VERSION 5.8 ;
BUSBITCHARS "[]" ;
DIVIDERCHAR "/" ;
UNITS
    DATABASE MICRONS 1000 ;
END UNITS

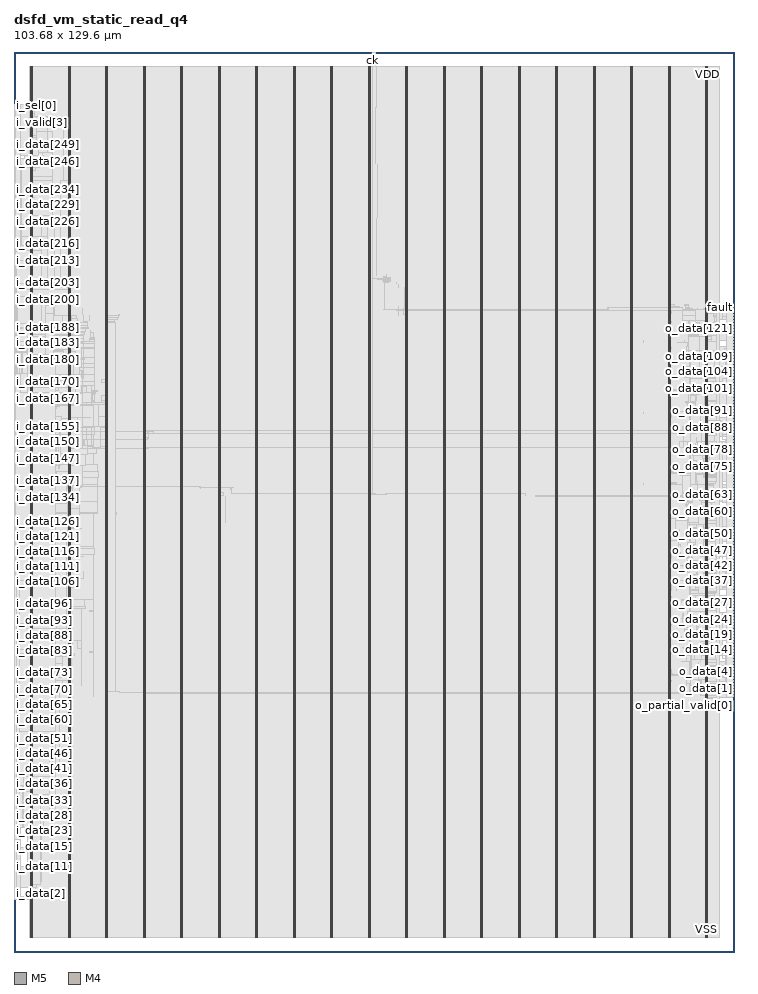
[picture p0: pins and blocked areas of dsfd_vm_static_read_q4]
MACRO dsfd_vm_static_read_q4
  FOREIGN dsfd_vm_static_read_q4 0 0 ;
  CLASS BLOCK ;
  SIZE 103.68 BY 129.6 ;
  PIN ck
    DIRECTION INPUT ;
    USE SIGNAL ;
    PORT
      LAYER M5 ;
        RECT  51.6 129.516 51.624 129.6 ;
    END
  END ck
  PIN fault
    DIRECTION OUTPUT ;
    USE SIGNAL ;
    PORT
      LAYER M4 ;
        RECT  103.596 92.832 103.68 92.856 ;
    END
  END fault
  PIN i_data[0]
    DIRECTION INPUT ;
    USE SIGNAL ;
    PORT
      LAYER M4 ;
        RECT  0 7.536 0.084 7.56 ;
    END
  END i_data[0]
  PIN i_data[100]
    DIRECTION INPUT ;
    USE SIGNAL ;
    PORT
      LAYER M4 ;
        RECT  0 50.736 0.084 50.76 ;
    END
  END i_data[100]
  PIN i_data[101]
    DIRECTION INPUT ;
    USE SIGNAL ;
    PORT
      LAYER M4 ;
        RECT  0 51.168 0.084 51.192 ;
    END
  END i_data[101]
  PIN i_data[102]
    DIRECTION INPUT ;
    USE SIGNAL ;
    PORT
      LAYER M4 ;
        RECT  0 51.6 0.084 51.624 ;
    END
  END i_data[102]
  PIN i_data[103]
    DIRECTION INPUT ;
    USE SIGNAL ;
    PORT
      LAYER M4 ;
        RECT  0 52.032 0.084 52.056 ;
    END
  END i_data[103]
  PIN i_data[104]
    DIRECTION INPUT ;
    USE SIGNAL ;
    PORT
      LAYER M4 ;
        RECT  0 52.464 0.084 52.488 ;
    END
  END i_data[104]
  PIN i_data[105]
    DIRECTION INPUT ;
    USE SIGNAL ;
    PORT
      LAYER M4 ;
        RECT  0 52.896 0.084 52.92 ;
    END
  END i_data[105]
  PIN i_data[106]
    DIRECTION INPUT ;
    USE SIGNAL ;
    PORT
      LAYER M4 ;
        RECT  0 53.328 0.084 53.352 ;
    END
  END i_data[106]
  PIN i_data[107]
    DIRECTION INPUT ;
    USE SIGNAL ;
    PORT
      LAYER M4 ;
        RECT  0 53.76 0.084 53.784 ;
    END
  END i_data[107]
  PIN i_data[108]
    DIRECTION INPUT ;
    USE SIGNAL ;
    PORT
      LAYER M4 ;
        RECT  0 54.192 0.084 54.216 ;
    END
  END i_data[108]
  PIN i_data[109]
    DIRECTION INPUT ;
    USE SIGNAL ;
    PORT
      LAYER M4 ;
        RECT  0 54.624 0.084 54.648 ;
    END
  END i_data[109]
  PIN i_data[10]
    DIRECTION INPUT ;
    USE SIGNAL ;
    PORT
      LAYER M4 ;
        RECT  0 11.856 0.084 11.88 ;
    END
  END i_data[10]
  PIN i_data[110]
    DIRECTION INPUT ;
    USE SIGNAL ;
    PORT
      LAYER M4 ;
        RECT  0 55.056 0.084 55.08 ;
    END
  END i_data[110]
  PIN i_data[111]
    DIRECTION INPUT ;
    USE SIGNAL ;
    PORT
      LAYER M4 ;
        RECT  0 55.488 0.084 55.512 ;
    END
  END i_data[111]
  PIN i_data[112]
    DIRECTION INPUT ;
    USE SIGNAL ;
    PORT
      LAYER M4 ;
        RECT  0 55.92 0.084 55.944 ;
    END
  END i_data[112]
  PIN i_data[113]
    DIRECTION INPUT ;
    USE SIGNAL ;
    PORT
      LAYER M4 ;
        RECT  0 56.352 0.084 56.376 ;
    END
  END i_data[113]
  PIN i_data[114]
    DIRECTION INPUT ;
    USE SIGNAL ;
    PORT
      LAYER M4 ;
        RECT  0 56.784 0.084 56.808 ;
    END
  END i_data[114]
  PIN i_data[115]
    DIRECTION INPUT ;
    USE SIGNAL ;
    PORT
      LAYER M4 ;
        RECT  0 57.216 0.084 57.24 ;
    END
  END i_data[115]
  PIN i_data[116]
    DIRECTION INPUT ;
    USE SIGNAL ;
    PORT
      LAYER M4 ;
        RECT  0 57.648 0.084 57.672 ;
    END
  END i_data[116]
  PIN i_data[117]
    DIRECTION INPUT ;
    USE SIGNAL ;
    PORT
      LAYER M4 ;
        RECT  0 58.08 0.084 58.104 ;
    END
  END i_data[117]
  PIN i_data[118]
    DIRECTION INPUT ;
    USE SIGNAL ;
    PORT
      LAYER M4 ;
        RECT  0 58.512 0.084 58.536 ;
    END
  END i_data[118]
  PIN i_data[119]
    DIRECTION INPUT ;
    USE SIGNAL ;
    PORT
      LAYER M4 ;
        RECT  0 58.944 0.084 58.968 ;
    END
  END i_data[119]
  PIN i_data[11]
    DIRECTION INPUT ;
    USE SIGNAL ;
    PORT
      LAYER M4 ;
        RECT  0 12.288 0.084 12.312 ;
    END
  END i_data[11]
  PIN i_data[120]
    DIRECTION INPUT ;
    USE SIGNAL ;
    PORT
      LAYER M4 ;
        RECT  0 59.376 0.084 59.4 ;
    END
  END i_data[120]
  PIN i_data[121]
    DIRECTION INPUT ;
    USE SIGNAL ;
    PORT
      LAYER M4 ;
        RECT  0 59.808 0.084 59.832 ;
    END
  END i_data[121]
  PIN i_data[122]
    DIRECTION INPUT ;
    USE SIGNAL ;
    PORT
      LAYER M4 ;
        RECT  0 60.24 0.084 60.264 ;
    END
  END i_data[122]
  PIN i_data[123]
    DIRECTION INPUT ;
    USE SIGNAL ;
    PORT
      LAYER M4 ;
        RECT  0 60.672 0.084 60.696 ;
    END
  END i_data[123]
  PIN i_data[124]
    DIRECTION INPUT ;
    USE SIGNAL ;
    PORT
      LAYER M4 ;
        RECT  0 61.104 0.084 61.128 ;
    END
  END i_data[124]
  PIN i_data[125]
    DIRECTION INPUT ;
    USE SIGNAL ;
    PORT
      LAYER M4 ;
        RECT  0 61.536 0.084 61.56 ;
    END
  END i_data[125]
  PIN i_data[126]
    DIRECTION INPUT ;
    USE SIGNAL ;
    PORT
      LAYER M4 ;
        RECT  0 61.968 0.084 61.992 ;
    END
  END i_data[126]
  PIN i_data[127]
    DIRECTION INPUT ;
    USE SIGNAL ;
    PORT
      LAYER M4 ;
        RECT  0 62.4 0.084 62.424 ;
    END
  END i_data[127]
  PIN i_data[128]
    DIRECTION INPUT ;
    USE SIGNAL ;
    PORT
      LAYER M4 ;
        RECT  0 62.832 0.084 62.856 ;
    END
  END i_data[128]
  PIN i_data[129]
    DIRECTION INPUT ;
    USE SIGNAL ;
    PORT
      LAYER M4 ;
        RECT  0 63.264 0.084 63.288 ;
    END
  END i_data[129]
  PIN i_data[12]
    DIRECTION INPUT ;
    USE SIGNAL ;
    PORT
      LAYER M4 ;
        RECT  0 12.72 0.084 12.744 ;
    END
  END i_data[12]
  PIN i_data[130]
    DIRECTION INPUT ;
    USE SIGNAL ;
    PORT
      LAYER M4 ;
        RECT  0 63.696 0.084 63.72 ;
    END
  END i_data[130]
  PIN i_data[131]
    DIRECTION INPUT ;
    USE SIGNAL ;
    PORT
      LAYER M4 ;
        RECT  0 64.128 0.084 64.152 ;
    END
  END i_data[131]
  PIN i_data[132]
    DIRECTION INPUT ;
    USE SIGNAL ;
    PORT
      LAYER M4 ;
        RECT  0 64.56 0.084 64.584 ;
    END
  END i_data[132]
  PIN i_data[133]
    DIRECTION INPUT ;
    USE SIGNAL ;
    PORT
      LAYER M4 ;
        RECT  0 64.992 0.084 65.016 ;
    END
  END i_data[133]
  PIN i_data[134]
    DIRECTION INPUT ;
    USE SIGNAL ;
    PORT
      LAYER M4 ;
        RECT  0 65.424 0.084 65.448 ;
    END
  END i_data[134]
  PIN i_data[135]
    DIRECTION INPUT ;
    USE SIGNAL ;
    PORT
      LAYER M4 ;
        RECT  0 65.856 0.084 65.88 ;
    END
  END i_data[135]
  PIN i_data[136]
    DIRECTION INPUT ;
    USE SIGNAL ;
    PORT
      LAYER M4 ;
        RECT  0 66.288 0.084 66.312 ;
    END
  END i_data[136]
  PIN i_data[137]
    DIRECTION INPUT ;
    USE SIGNAL ;
    PORT
      LAYER M4 ;
        RECT  0 66.72 0.084 66.744 ;
    END
  END i_data[137]
  PIN i_data[138]
    DIRECTION INPUT ;
    USE SIGNAL ;
    PORT
      LAYER M4 ;
        RECT  0 67.152 0.084 67.176 ;
    END
  END i_data[138]
  PIN i_data[139]
    DIRECTION INPUT ;
    USE SIGNAL ;
    PORT
      LAYER M4 ;
        RECT  0 67.584 0.084 67.608 ;
    END
  END i_data[139]
  PIN i_data[13]
    DIRECTION INPUT ;
    USE SIGNAL ;
    PORT
      LAYER M4 ;
        RECT  0 13.152 0.084 13.176 ;
    END
  END i_data[13]
  PIN i_data[140]
    DIRECTION INPUT ;
    USE SIGNAL ;
    PORT
      LAYER M4 ;
        RECT  0 68.016 0.084 68.04 ;
    END
  END i_data[140]
  PIN i_data[141]
    DIRECTION INPUT ;
    USE SIGNAL ;
    PORT
      LAYER M4 ;
        RECT  0 68.448 0.084 68.472 ;
    END
  END i_data[141]
  PIN i_data[142]
    DIRECTION INPUT ;
    USE SIGNAL ;
    PORT
      LAYER M4 ;
        RECT  0 68.88 0.084 68.904 ;
    END
  END i_data[142]
  PIN i_data[143]
    DIRECTION INPUT ;
    USE SIGNAL ;
    PORT
      LAYER M4 ;
        RECT  0 69.312 0.084 69.336 ;
    END
  END i_data[143]
  PIN i_data[144]
    DIRECTION INPUT ;
    USE SIGNAL ;
    PORT
      LAYER M4 ;
        RECT  0 69.744 0.084 69.768 ;
    END
  END i_data[144]
  PIN i_data[145]
    DIRECTION INPUT ;
    USE SIGNAL ;
    PORT
      LAYER M4 ;
        RECT  0 70.176 0.084 70.2 ;
    END
  END i_data[145]
  PIN i_data[146]
    DIRECTION INPUT ;
    USE SIGNAL ;
    PORT
      LAYER M4 ;
        RECT  0 70.608 0.084 70.632 ;
    END
  END i_data[146]
  PIN i_data[147]
    DIRECTION INPUT ;
    USE SIGNAL ;
    PORT
      LAYER M4 ;
        RECT  0 71.04 0.084 71.064 ;
    END
  END i_data[147]
  PIN i_data[148]
    DIRECTION INPUT ;
    USE SIGNAL ;
    PORT
      LAYER M4 ;
        RECT  0 71.472 0.084 71.496 ;
    END
  END i_data[148]
  PIN i_data[149]
    DIRECTION INPUT ;
    USE SIGNAL ;
    PORT
      LAYER M4 ;
        RECT  0 71.904 0.084 71.928 ;
    END
  END i_data[149]
  PIN i_data[14]
    DIRECTION INPUT ;
    USE SIGNAL ;
    PORT
      LAYER M4 ;
        RECT  0 13.584 0.084 13.608 ;
    END
  END i_data[14]
  PIN i_data[150]
    DIRECTION INPUT ;
    USE SIGNAL ;
    PORT
      LAYER M4 ;
        RECT  0 72.336 0.084 72.36 ;
    END
  END i_data[150]
  PIN i_data[151]
    DIRECTION INPUT ;
    USE SIGNAL ;
    PORT
      LAYER M4 ;
        RECT  0 72.768 0.084 72.792 ;
    END
  END i_data[151]
  PIN i_data[152]
    DIRECTION INPUT ;
    USE SIGNAL ;
    PORT
      LAYER M4 ;
        RECT  0 73.2 0.084 73.224 ;
    END
  END i_data[152]
  PIN i_data[153]
    DIRECTION INPUT ;
    USE SIGNAL ;
    PORT
      LAYER M4 ;
        RECT  0 73.632 0.084 73.656 ;
    END
  END i_data[153]
  PIN i_data[154]
    DIRECTION INPUT ;
    USE SIGNAL ;
    PORT
      LAYER M4 ;
        RECT  0 74.064 0.084 74.088 ;
    END
  END i_data[154]
  PIN i_data[155]
    DIRECTION INPUT ;
    USE SIGNAL ;
    PORT
      LAYER M4 ;
        RECT  0 74.496 0.084 74.52 ;
    END
  END i_data[155]
  PIN i_data[156]
    DIRECTION INPUT ;
    USE SIGNAL ;
    PORT
      LAYER M4 ;
        RECT  0 74.928 0.084 74.952 ;
    END
  END i_data[156]
  PIN i_data[157]
    DIRECTION INPUT ;
    USE SIGNAL ;
    PORT
      LAYER M4 ;
        RECT  0 75.36 0.084 75.384 ;
    END
  END i_data[157]
  PIN i_data[158]
    DIRECTION INPUT ;
    USE SIGNAL ;
    PORT
      LAYER M4 ;
        RECT  0 75.792 0.084 75.816 ;
    END
  END i_data[158]
  PIN i_data[159]
    DIRECTION INPUT ;
    USE SIGNAL ;
    PORT
      LAYER M4 ;
        RECT  0 76.224 0.084 76.248 ;
    END
  END i_data[159]
  PIN i_data[15]
    DIRECTION INPUT ;
    USE SIGNAL ;
    PORT
      LAYER M4 ;
        RECT  0 14.016 0.084 14.04 ;
    END
  END i_data[15]
  PIN i_data[160]
    DIRECTION INPUT ;
    USE SIGNAL ;
    PORT
      LAYER M4 ;
        RECT  0 76.656 0.084 76.68 ;
    END
  END i_data[160]
  PIN i_data[161]
    DIRECTION INPUT ;
    USE SIGNAL ;
    PORT
      LAYER M4 ;
        RECT  0 77.088 0.084 77.112 ;
    END
  END i_data[161]
  PIN i_data[162]
    DIRECTION INPUT ;
    USE SIGNAL ;
    PORT
      LAYER M4 ;
        RECT  0 77.52 0.084 77.544 ;
    END
  END i_data[162]
  PIN i_data[163]
    DIRECTION INPUT ;
    USE SIGNAL ;
    PORT
      LAYER M4 ;
        RECT  0 77.952 0.084 77.976 ;
    END
  END i_data[163]
  PIN i_data[164]
    DIRECTION INPUT ;
    USE SIGNAL ;
    PORT
      LAYER M4 ;
        RECT  0 78.384 0.084 78.408 ;
    END
  END i_data[164]
  PIN i_data[165]
    DIRECTION INPUT ;
    USE SIGNAL ;
    PORT
      LAYER M4 ;
        RECT  0 78.816 0.084 78.84 ;
    END
  END i_data[165]
  PIN i_data[166]
    DIRECTION INPUT ;
    USE SIGNAL ;
    PORT
      LAYER M4 ;
        RECT  0 79.248 0.084 79.272 ;
    END
  END i_data[166]
  PIN i_data[167]
    DIRECTION INPUT ;
    USE SIGNAL ;
    PORT
      LAYER M4 ;
        RECT  0 79.68 0.084 79.704 ;
    END
  END i_data[167]
  PIN i_data[168]
    DIRECTION INPUT ;
    USE SIGNAL ;
    PORT
      LAYER M4 ;
        RECT  0 80.112 0.084 80.136 ;
    END
  END i_data[168]
  PIN i_data[169]
    DIRECTION INPUT ;
    USE SIGNAL ;
    PORT
      LAYER M4 ;
        RECT  0 80.544 0.084 80.568 ;
    END
  END i_data[169]
  PIN i_data[16]
    DIRECTION INPUT ;
    USE SIGNAL ;
    PORT
      LAYER M4 ;
        RECT  0 14.448 0.084 14.472 ;
    END
  END i_data[16]
  PIN i_data[170]
    DIRECTION INPUT ;
    USE SIGNAL ;
    PORT
      LAYER M4 ;
        RECT  0 80.976 0.084 81 ;
    END
  END i_data[170]
  PIN i_data[171]
    DIRECTION INPUT ;
    USE SIGNAL ;
    PORT
      LAYER M4 ;
        RECT  0 81.408 0.084 81.432 ;
    END
  END i_data[171]
  PIN i_data[172]
    DIRECTION INPUT ;
    USE SIGNAL ;
    PORT
      LAYER M4 ;
        RECT  0 81.84 0.084 81.864 ;
    END
  END i_data[172]
  PIN i_data[173]
    DIRECTION INPUT ;
    USE SIGNAL ;
    PORT
      LAYER M4 ;
        RECT  0 82.272 0.084 82.296 ;
    END
  END i_data[173]
  PIN i_data[174]
    DIRECTION INPUT ;
    USE SIGNAL ;
    PORT
      LAYER M4 ;
        RECT  0 82.704 0.084 82.728 ;
    END
  END i_data[174]
  PIN i_data[175]
    DIRECTION INPUT ;
    USE SIGNAL ;
    PORT
      LAYER M4 ;
        RECT  0 83.136 0.084 83.16 ;
    END
  END i_data[175]
  PIN i_data[176]
    DIRECTION INPUT ;
    USE SIGNAL ;
    PORT
      LAYER M4 ;
        RECT  0 83.568 0.084 83.592 ;
    END
  END i_data[176]
  PIN i_data[177]
    DIRECTION INPUT ;
    USE SIGNAL ;
    PORT
      LAYER M4 ;
        RECT  0 84 0.084 84.024 ;
    END
  END i_data[177]
  PIN i_data[178]
    DIRECTION INPUT ;
    USE SIGNAL ;
    PORT
      LAYER M4 ;
        RECT  0 84.432 0.084 84.456 ;
    END
  END i_data[178]
  PIN i_data[179]
    DIRECTION INPUT ;
    USE SIGNAL ;
    PORT
      LAYER M4 ;
        RECT  0 84.864 0.084 84.888 ;
    END
  END i_data[179]
  PIN i_data[17]
    DIRECTION INPUT ;
    USE SIGNAL ;
    PORT
      LAYER M4 ;
        RECT  0 14.88 0.084 14.904 ;
    END
  END i_data[17]
  PIN i_data[180]
    DIRECTION INPUT ;
    USE SIGNAL ;
    PORT
      LAYER M4 ;
        RECT  0 85.296 0.084 85.32 ;
    END
  END i_data[180]
  PIN i_data[181]
    DIRECTION INPUT ;
    USE SIGNAL ;
    PORT
      LAYER M4 ;
        RECT  0 85.728 0.084 85.752 ;
    END
  END i_data[181]
  PIN i_data[182]
    DIRECTION INPUT ;
    USE SIGNAL ;
    PORT
      LAYER M4 ;
        RECT  0 86.16 0.084 86.184 ;
    END
  END i_data[182]
  PIN i_data[183]
    DIRECTION INPUT ;
    USE SIGNAL ;
    PORT
      LAYER M4 ;
        RECT  0 86.592 0.084 86.616 ;
    END
  END i_data[183]
  PIN i_data[184]
    DIRECTION INPUT ;
    USE SIGNAL ;
    PORT
      LAYER M4 ;
        RECT  0 87.024 0.084 87.048 ;
    END
  END i_data[184]
  PIN i_data[185]
    DIRECTION INPUT ;
    USE SIGNAL ;
    PORT
      LAYER M4 ;
        RECT  0 87.456 0.084 87.48 ;
    END
  END i_data[185]
  PIN i_data[186]
    DIRECTION INPUT ;
    USE SIGNAL ;
    PORT
      LAYER M4 ;
        RECT  0 87.888 0.084 87.912 ;
    END
  END i_data[186]
  PIN i_data[187]
    DIRECTION INPUT ;
    USE SIGNAL ;
    PORT
      LAYER M4 ;
        RECT  0 88.32 0.084 88.344 ;
    END
  END i_data[187]
  PIN i_data[188]
    DIRECTION INPUT ;
    USE SIGNAL ;
    PORT
      LAYER M4 ;
        RECT  0 88.752 0.084 88.776 ;
    END
  END i_data[188]
  PIN i_data[189]
    DIRECTION INPUT ;
    USE SIGNAL ;
    PORT
      LAYER M4 ;
        RECT  0 89.184 0.084 89.208 ;
    END
  END i_data[189]
  PIN i_data[18]
    DIRECTION INPUT ;
    USE SIGNAL ;
    PORT
      LAYER M4 ;
        RECT  0 15.312 0.084 15.336 ;
    END
  END i_data[18]
  PIN i_data[190]
    DIRECTION INPUT ;
    USE SIGNAL ;
    PORT
      LAYER M4 ;
        RECT  0 89.616 0.084 89.64 ;
    END
  END i_data[190]
  PIN i_data[191]
    DIRECTION INPUT ;
    USE SIGNAL ;
    PORT
      LAYER M4 ;
        RECT  0 90.048 0.084 90.072 ;
    END
  END i_data[191]
  PIN i_data[192]
    DIRECTION INPUT ;
    USE SIGNAL ;
    PORT
      LAYER M4 ;
        RECT  0 90.48 0.084 90.504 ;
    END
  END i_data[192]
  PIN i_data[193]
    DIRECTION INPUT ;
    USE SIGNAL ;
    PORT
      LAYER M4 ;
        RECT  0 90.912 0.084 90.936 ;
    END
  END i_data[193]
  PIN i_data[194]
    DIRECTION INPUT ;
    USE SIGNAL ;
    PORT
      LAYER M4 ;
        RECT  0 91.344 0.084 91.368 ;
    END
  END i_data[194]
  PIN i_data[195]
    DIRECTION INPUT ;
    USE SIGNAL ;
    PORT
      LAYER M4 ;
        RECT  0 91.776 0.084 91.8 ;
    END
  END i_data[195]
  PIN i_data[196]
    DIRECTION INPUT ;
    USE SIGNAL ;
    PORT
      LAYER M4 ;
        RECT  0 92.208 0.084 92.232 ;
    END
  END i_data[196]
  PIN i_data[197]
    DIRECTION INPUT ;
    USE SIGNAL ;
    PORT
      LAYER M4 ;
        RECT  0 92.64 0.084 92.664 ;
    END
  END i_data[197]
  PIN i_data[198]
    DIRECTION INPUT ;
    USE SIGNAL ;
    PORT
      LAYER M4 ;
        RECT  0 93.072 0.084 93.096 ;
    END
  END i_data[198]
  PIN i_data[199]
    DIRECTION INPUT ;
    USE SIGNAL ;
    PORT
      LAYER M4 ;
        RECT  0 93.504 0.084 93.528 ;
    END
  END i_data[199]
  PIN i_data[19]
    DIRECTION INPUT ;
    USE SIGNAL ;
    PORT
      LAYER M4 ;
        RECT  0 15.744 0.084 15.768 ;
    END
  END i_data[19]
  PIN i_data[1]
    DIRECTION INPUT ;
    USE SIGNAL ;
    PORT
      LAYER M4 ;
        RECT  0 7.968 0.084 7.992 ;
    END
  END i_data[1]
  PIN i_data[200]
    DIRECTION INPUT ;
    USE SIGNAL ;
    PORT
      LAYER M4 ;
        RECT  0 93.936 0.084 93.96 ;
    END
  END i_data[200]
  PIN i_data[201]
    DIRECTION INPUT ;
    USE SIGNAL ;
    PORT
      LAYER M4 ;
        RECT  0 94.368 0.084 94.392 ;
    END
  END i_data[201]
  PIN i_data[202]
    DIRECTION INPUT ;
    USE SIGNAL ;
    PORT
      LAYER M4 ;
        RECT  0 94.8 0.084 94.824 ;
    END
  END i_data[202]
  PIN i_data[203]
    DIRECTION INPUT ;
    USE SIGNAL ;
    PORT
      LAYER M4 ;
        RECT  0 95.232 0.084 95.256 ;
    END
  END i_data[203]
  PIN i_data[204]
    DIRECTION INPUT ;
    USE SIGNAL ;
    PORT
      LAYER M4 ;
        RECT  0 95.664 0.084 95.688 ;
    END
  END i_data[204]
  PIN i_data[205]
    DIRECTION INPUT ;
    USE SIGNAL ;
    PORT
      LAYER M4 ;
        RECT  0 96.096 0.084 96.12 ;
    END
  END i_data[205]
  PIN i_data[206]
    DIRECTION INPUT ;
    USE SIGNAL ;
    PORT
      LAYER M4 ;
        RECT  0 96.528 0.084 96.552 ;
    END
  END i_data[206]
  PIN i_data[207]
    DIRECTION INPUT ;
    USE SIGNAL ;
    PORT
      LAYER M4 ;
        RECT  0 96.96 0.084 96.984 ;
    END
  END i_data[207]
  PIN i_data[208]
    DIRECTION INPUT ;
    USE SIGNAL ;
    PORT
      LAYER M4 ;
        RECT  0 97.392 0.084 97.416 ;
    END
  END i_data[208]
  PIN i_data[209]
    DIRECTION INPUT ;
    USE SIGNAL ;
    PORT
      LAYER M4 ;
        RECT  0 97.824 0.084 97.848 ;
    END
  END i_data[209]
  PIN i_data[20]
    DIRECTION INPUT ;
    USE SIGNAL ;
    PORT
      LAYER M4 ;
        RECT  0 16.176 0.084 16.2 ;
    END
  END i_data[20]
  PIN i_data[210]
    DIRECTION INPUT ;
    USE SIGNAL ;
    PORT
      LAYER M4 ;
        RECT  0 98.256 0.084 98.28 ;
    END
  END i_data[210]
  PIN i_data[211]
    DIRECTION INPUT ;
    USE SIGNAL ;
    PORT
      LAYER M4 ;
        RECT  0 98.688 0.084 98.712 ;
    END
  END i_data[211]
  PIN i_data[212]
    DIRECTION INPUT ;
    USE SIGNAL ;
    PORT
      LAYER M4 ;
        RECT  0 99.12 0.084 99.144 ;
    END
  END i_data[212]
  PIN i_data[213]
    DIRECTION INPUT ;
    USE SIGNAL ;
    PORT
      LAYER M4 ;
        RECT  0 99.552 0.084 99.576 ;
    END
  END i_data[213]
  PIN i_data[214]
    DIRECTION INPUT ;
    USE SIGNAL ;
    PORT
      LAYER M4 ;
        RECT  0 99.984 0.084 100.008 ;
    END
  END i_data[214]
  PIN i_data[215]
    DIRECTION INPUT ;
    USE SIGNAL ;
    PORT
      LAYER M4 ;
        RECT  0 100.416 0.084 100.44 ;
    END
  END i_data[215]
  PIN i_data[216]
    DIRECTION INPUT ;
    USE SIGNAL ;
    PORT
      LAYER M4 ;
        RECT  0 100.848 0.084 100.872 ;
    END
  END i_data[216]
  PIN i_data[217]
    DIRECTION INPUT ;
    USE SIGNAL ;
    PORT
      LAYER M4 ;
        RECT  0 101.28 0.084 101.304 ;
    END
  END i_data[217]
  PIN i_data[218]
    DIRECTION INPUT ;
    USE SIGNAL ;
    PORT
      LAYER M4 ;
        RECT  0 101.712 0.084 101.736 ;
    END
  END i_data[218]
  PIN i_data[219]
    DIRECTION INPUT ;
    USE SIGNAL ;
    PORT
      LAYER M4 ;
        RECT  0 102.144 0.084 102.168 ;
    END
  END i_data[219]
  PIN i_data[21]
    DIRECTION INPUT ;
    USE SIGNAL ;
    PORT
      LAYER M4 ;
        RECT  0 16.608 0.084 16.632 ;
    END
  END i_data[21]
  PIN i_data[220]
    DIRECTION INPUT ;
    USE SIGNAL ;
    PORT
      LAYER M4 ;
        RECT  0 102.576 0.084 102.6 ;
    END
  END i_data[220]
  PIN i_data[221]
    DIRECTION INPUT ;
    USE SIGNAL ;
    PORT
      LAYER M4 ;
        RECT  0 103.008 0.084 103.032 ;
    END
  END i_data[221]
  PIN i_data[222]
    DIRECTION INPUT ;
    USE SIGNAL ;
    PORT
      LAYER M4 ;
        RECT  0 103.44 0.084 103.464 ;
    END
  END i_data[222]
  PIN i_data[223]
    DIRECTION INPUT ;
    USE SIGNAL ;
    PORT
      LAYER M4 ;
        RECT  0 103.872 0.084 103.896 ;
    END
  END i_data[223]
  PIN i_data[224]
    DIRECTION INPUT ;
    USE SIGNAL ;
    PORT
      LAYER M4 ;
        RECT  0 104.304 0.084 104.328 ;
    END
  END i_data[224]
  PIN i_data[225]
    DIRECTION INPUT ;
    USE SIGNAL ;
    PORT
      LAYER M4 ;
        RECT  0 104.736 0.084 104.76 ;
    END
  END i_data[225]
  PIN i_data[226]
    DIRECTION INPUT ;
    USE SIGNAL ;
    PORT
      LAYER M4 ;
        RECT  0 105.168 0.084 105.192 ;
    END
  END i_data[226]
  PIN i_data[227]
    DIRECTION INPUT ;
    USE SIGNAL ;
    PORT
      LAYER M4 ;
        RECT  0 105.6 0.084 105.624 ;
    END
  END i_data[227]
  PIN i_data[228]
    DIRECTION INPUT ;
    USE SIGNAL ;
    PORT
      LAYER M4 ;
        RECT  0 106.032 0.084 106.056 ;
    END
  END i_data[228]
  PIN i_data[229]
    DIRECTION INPUT ;
    USE SIGNAL ;
    PORT
      LAYER M4 ;
        RECT  0 106.464 0.084 106.488 ;
    END
  END i_data[229]
  PIN i_data[22]
    DIRECTION INPUT ;
    USE SIGNAL ;
    PORT
      LAYER M4 ;
        RECT  0 17.04 0.084 17.064 ;
    END
  END i_data[22]
  PIN i_data[230]
    DIRECTION INPUT ;
    USE SIGNAL ;
    PORT
      LAYER M4 ;
        RECT  0 106.896 0.084 106.92 ;
    END
  END i_data[230]
  PIN i_data[231]
    DIRECTION INPUT ;
    USE SIGNAL ;
    PORT
      LAYER M4 ;
        RECT  0 107.328 0.084 107.352 ;
    END
  END i_data[231]
  PIN i_data[232]
    DIRECTION INPUT ;
    USE SIGNAL ;
    PORT
      LAYER M4 ;
        RECT  0 107.76 0.084 107.784 ;
    END
  END i_data[232]
  PIN i_data[233]
    DIRECTION INPUT ;
    USE SIGNAL ;
    PORT
      LAYER M4 ;
        RECT  0 108.192 0.084 108.216 ;
    END
  END i_data[233]
  PIN i_data[234]
    DIRECTION INPUT ;
    USE SIGNAL ;
    PORT
      LAYER M4 ;
        RECT  0 108.624 0.084 108.648 ;
    END
  END i_data[234]
  PIN i_data[235]
    DIRECTION INPUT ;
    USE SIGNAL ;
    PORT
      LAYER M4 ;
        RECT  0 109.056 0.084 109.08 ;
    END
  END i_data[235]
  PIN i_data[236]
    DIRECTION INPUT ;
    USE SIGNAL ;
    PORT
      LAYER M4 ;
        RECT  0 109.488 0.084 109.512 ;
    END
  END i_data[236]
  PIN i_data[237]
    DIRECTION INPUT ;
    USE SIGNAL ;
    PORT
      LAYER M4 ;
        RECT  0 109.92 0.084 109.944 ;
    END
  END i_data[237]
  PIN i_data[238]
    DIRECTION INPUT ;
    USE SIGNAL ;
    PORT
      LAYER M4 ;
        RECT  0 110.352 0.084 110.376 ;
    END
  END i_data[238]
  PIN i_data[239]
    DIRECTION INPUT ;
    USE SIGNAL ;
    PORT
      LAYER M4 ;
        RECT  0 110.784 0.084 110.808 ;
    END
  END i_data[239]
  PIN i_data[23]
    DIRECTION INPUT ;
    USE SIGNAL ;
    PORT
      LAYER M4 ;
        RECT  0 17.472 0.084 17.496 ;
    END
  END i_data[23]
  PIN i_data[240]
    DIRECTION INPUT ;
    USE SIGNAL ;
    PORT
      LAYER M4 ;
        RECT  0 111.216 0.084 111.24 ;
    END
  END i_data[240]
  PIN i_data[241]
    DIRECTION INPUT ;
    USE SIGNAL ;
    PORT
      LAYER M4 ;
        RECT  0 111.648 0.084 111.672 ;
    END
  END i_data[241]
  PIN i_data[242]
    DIRECTION INPUT ;
    USE SIGNAL ;
    PORT
      LAYER M4 ;
        RECT  0 112.08 0.084 112.104 ;
    END
  END i_data[242]
  PIN i_data[243]
    DIRECTION INPUT ;
    USE SIGNAL ;
    PORT
      LAYER M4 ;
        RECT  0 112.512 0.084 112.536 ;
    END
  END i_data[243]
  PIN i_data[244]
    DIRECTION INPUT ;
    USE SIGNAL ;
    PORT
      LAYER M4 ;
        RECT  0 112.944 0.084 112.968 ;
    END
  END i_data[244]
  PIN i_data[245]
    DIRECTION INPUT ;
    USE SIGNAL ;
    PORT
      LAYER M4 ;
        RECT  0 113.376 0.084 113.4 ;
    END
  END i_data[245]
  PIN i_data[246]
    DIRECTION INPUT ;
    USE SIGNAL ;
    PORT
      LAYER M4 ;
        RECT  0 113.808 0.084 113.832 ;
    END
  END i_data[246]
  PIN i_data[247]
    DIRECTION INPUT ;
    USE SIGNAL ;
    PORT
      LAYER M4 ;
        RECT  0 114.24 0.084 114.264 ;
    END
  END i_data[247]
  PIN i_data[248]
    DIRECTION INPUT ;
    USE SIGNAL ;
    PORT
      LAYER M4 ;
        RECT  0 114.672 0.084 114.696 ;
    END
  END i_data[248]
  PIN i_data[249]
    DIRECTION INPUT ;
    USE SIGNAL ;
    PORT
      LAYER M4 ;
        RECT  0 115.104 0.084 115.128 ;
    END
  END i_data[249]
  PIN i_data[24]
    DIRECTION INPUT ;
    USE SIGNAL ;
    PORT
      LAYER M4 ;
        RECT  0 17.904 0.084 17.928 ;
    END
  END i_data[24]
  PIN i_data[250]
    DIRECTION INPUT ;
    USE SIGNAL ;
    PORT
      LAYER M4 ;
        RECT  0 115.536 0.084 115.56 ;
    END
  END i_data[250]
  PIN i_data[251]
    DIRECTION INPUT ;
    USE SIGNAL ;
    PORT
      LAYER M4 ;
        RECT  0 115.968 0.084 115.992 ;
    END
  END i_data[251]
  PIN i_data[252]
    DIRECTION INPUT ;
    USE SIGNAL ;
    PORT
      LAYER M4 ;
        RECT  0 116.4 0.084 116.424 ;
    END
  END i_data[252]
  PIN i_data[253]
    DIRECTION INPUT ;
    USE SIGNAL ;
    PORT
      LAYER M4 ;
        RECT  0 116.832 0.084 116.856 ;
    END
  END i_data[253]
  PIN i_data[254]
    DIRECTION INPUT ;
    USE SIGNAL ;
    PORT
      LAYER M4 ;
        RECT  0 117.264 0.084 117.288 ;
    END
  END i_data[254]
  PIN i_data[255]
    DIRECTION INPUT ;
    USE SIGNAL ;
    PORT
      LAYER M4 ;
        RECT  0 117.696 0.084 117.72 ;
    END
  END i_data[255]
  PIN i_data[25]
    DIRECTION INPUT ;
    USE SIGNAL ;
    PORT
      LAYER M4 ;
        RECT  0 18.336 0.084 18.36 ;
    END
  END i_data[25]
  PIN i_data[26]
    DIRECTION INPUT ;
    USE SIGNAL ;
    PORT
      LAYER M4 ;
        RECT  0 18.768 0.084 18.792 ;
    END
  END i_data[26]
  PIN i_data[27]
    DIRECTION INPUT ;
    USE SIGNAL ;
    PORT
      LAYER M4 ;
        RECT  0 19.2 0.084 19.224 ;
    END
  END i_data[27]
  PIN i_data[28]
    DIRECTION INPUT ;
    USE SIGNAL ;
    PORT
      LAYER M4 ;
        RECT  0 19.632 0.084 19.656 ;
    END
  END i_data[28]
  PIN i_data[29]
    DIRECTION INPUT ;
    USE SIGNAL ;
    PORT
      LAYER M4 ;
        RECT  0 20.064 0.084 20.088 ;
    END
  END i_data[29]
  PIN i_data[2]
    DIRECTION INPUT ;
    USE SIGNAL ;
    PORT
      LAYER M4 ;
        RECT  0 8.4 0.084 8.424 ;
    END
  END i_data[2]
  PIN i_data[30]
    DIRECTION INPUT ;
    USE SIGNAL ;
    PORT
      LAYER M4 ;
        RECT  0 20.496 0.084 20.52 ;
    END
  END i_data[30]
  PIN i_data[31]
    DIRECTION INPUT ;
    USE SIGNAL ;
    PORT
      LAYER M4 ;
        RECT  0 20.928 0.084 20.952 ;
    END
  END i_data[31]
  PIN i_data[32]
    DIRECTION INPUT ;
    USE SIGNAL ;
    PORT
      LAYER M4 ;
        RECT  0 21.36 0.084 21.384 ;
    END
  END i_data[32]
  PIN i_data[33]
    DIRECTION INPUT ;
    USE SIGNAL ;
    PORT
      LAYER M4 ;
        RECT  0 21.792 0.084 21.816 ;
    END
  END i_data[33]
  PIN i_data[34]
    DIRECTION INPUT ;
    USE SIGNAL ;
    PORT
      LAYER M4 ;
        RECT  0 22.224 0.084 22.248 ;
    END
  END i_data[34]
  PIN i_data[35]
    DIRECTION INPUT ;
    USE SIGNAL ;
    PORT
      LAYER M4 ;
        RECT  0 22.656 0.084 22.68 ;
    END
  END i_data[35]
  PIN i_data[36]
    DIRECTION INPUT ;
    USE SIGNAL ;
    PORT
      LAYER M4 ;
        RECT  0 23.088 0.084 23.112 ;
    END
  END i_data[36]
  PIN i_data[37]
    DIRECTION INPUT ;
    USE SIGNAL ;
    PORT
      LAYER M4 ;
        RECT  0 23.52 0.084 23.544 ;
    END
  END i_data[37]
  PIN i_data[38]
    DIRECTION INPUT ;
    USE SIGNAL ;
    PORT
      LAYER M4 ;
        RECT  0 23.952 0.084 23.976 ;
    END
  END i_data[38]
  PIN i_data[39]
    DIRECTION INPUT ;
    USE SIGNAL ;
    PORT
      LAYER M4 ;
        RECT  0 24.384 0.084 24.408 ;
    END
  END i_data[39]
  PIN i_data[3]
    DIRECTION INPUT ;
    USE SIGNAL ;
    PORT
      LAYER M4 ;
        RECT  0 8.832 0.084 8.856 ;
    END
  END i_data[3]
  PIN i_data[40]
    DIRECTION INPUT ;
    USE SIGNAL ;
    PORT
      LAYER M4 ;
        RECT  0 24.816 0.084 24.84 ;
    END
  END i_data[40]
  PIN i_data[41]
    DIRECTION INPUT ;
    USE SIGNAL ;
    PORT
      LAYER M4 ;
        RECT  0 25.248 0.084 25.272 ;
    END
  END i_data[41]
  PIN i_data[42]
    DIRECTION INPUT ;
    USE SIGNAL ;
    PORT
      LAYER M4 ;
        RECT  0 25.68 0.084 25.704 ;
    END
  END i_data[42]
  PIN i_data[43]
    DIRECTION INPUT ;
    USE SIGNAL ;
    PORT
      LAYER M4 ;
        RECT  0 26.112 0.084 26.136 ;
    END
  END i_data[43]
  PIN i_data[44]
    DIRECTION INPUT ;
    USE SIGNAL ;
    PORT
      LAYER M4 ;
        RECT  0 26.544 0.084 26.568 ;
    END
  END i_data[44]
  PIN i_data[45]
    DIRECTION INPUT ;
    USE SIGNAL ;
    PORT
      LAYER M4 ;
        RECT  0 26.976 0.084 27 ;
    END
  END i_data[45]
  PIN i_data[46]
    DIRECTION INPUT ;
    USE SIGNAL ;
    PORT
      LAYER M4 ;
        RECT  0 27.408 0.084 27.432 ;
    END
  END i_data[46]
  PIN i_data[47]
    DIRECTION INPUT ;
    USE SIGNAL ;
    PORT
      LAYER M4 ;
        RECT  0 27.84 0.084 27.864 ;
    END
  END i_data[47]
  PIN i_data[48]
    DIRECTION INPUT ;
    USE SIGNAL ;
    PORT
      LAYER M4 ;
        RECT  0 28.272 0.084 28.296 ;
    END
  END i_data[48]
  PIN i_data[49]
    DIRECTION INPUT ;
    USE SIGNAL ;
    PORT
      LAYER M4 ;
        RECT  0 28.704 0.084 28.728 ;
    END
  END i_data[49]
  PIN i_data[4]
    DIRECTION INPUT ;
    USE SIGNAL ;
    PORT
      LAYER M4 ;
        RECT  0 9.264 0.084 9.288 ;
    END
  END i_data[4]
  PIN i_data[50]
    DIRECTION INPUT ;
    USE SIGNAL ;
    PORT
      LAYER M4 ;
        RECT  0 29.136 0.084 29.16 ;
    END
  END i_data[50]
  PIN i_data[51]
    DIRECTION INPUT ;
    USE SIGNAL ;
    PORT
      LAYER M4 ;
        RECT  0 29.568 0.084 29.592 ;
    END
  END i_data[51]
  PIN i_data[52]
    DIRECTION INPUT ;
    USE SIGNAL ;
    PORT
      LAYER M4 ;
        RECT  0 30 0.084 30.024 ;
    END
  END i_data[52]
  PIN i_data[53]
    DIRECTION INPUT ;
    USE SIGNAL ;
    PORT
      LAYER M4 ;
        RECT  0 30.432 0.084 30.456 ;
    END
  END i_data[53]
  PIN i_data[54]
    DIRECTION INPUT ;
    USE SIGNAL ;
    PORT
      LAYER M4 ;
        RECT  0 30.864 0.084 30.888 ;
    END
  END i_data[54]
  PIN i_data[55]
    DIRECTION INPUT ;
    USE SIGNAL ;
    PORT
      LAYER M4 ;
        RECT  0 31.296 0.084 31.32 ;
    END
  END i_data[55]
  PIN i_data[56]
    DIRECTION INPUT ;
    USE SIGNAL ;
    PORT
      LAYER M4 ;
        RECT  0 31.728 0.084 31.752 ;
    END
  END i_data[56]
  PIN i_data[57]
    DIRECTION INPUT ;
    USE SIGNAL ;
    PORT
      LAYER M4 ;
        RECT  0 32.16 0.084 32.184 ;
    END
  END i_data[57]
  PIN i_data[58]
    DIRECTION INPUT ;
    USE SIGNAL ;
    PORT
      LAYER M4 ;
        RECT  0 32.592 0.084 32.616 ;
    END
  END i_data[58]
  PIN i_data[59]
    DIRECTION INPUT ;
    USE SIGNAL ;
    PORT
      LAYER M4 ;
        RECT  0 33.024 0.084 33.048 ;
    END
  END i_data[59]
  PIN i_data[5]
    DIRECTION INPUT ;
    USE SIGNAL ;
    PORT
      LAYER M4 ;
        RECT  0 9.696 0.084 9.72 ;
    END
  END i_data[5]
  PIN i_data[60]
    DIRECTION INPUT ;
    USE SIGNAL ;
    PORT
      LAYER M4 ;
        RECT  0 33.456 0.084 33.48 ;
    END
  END i_data[60]
  PIN i_data[61]
    DIRECTION INPUT ;
    USE SIGNAL ;
    PORT
      LAYER M4 ;
        RECT  0 33.888 0.084 33.912 ;
    END
  END i_data[61]
  PIN i_data[62]
    DIRECTION INPUT ;
    USE SIGNAL ;
    PORT
      LAYER M4 ;
        RECT  0 34.32 0.084 34.344 ;
    END
  END i_data[62]
  PIN i_data[63]
    DIRECTION INPUT ;
    USE SIGNAL ;
    PORT
      LAYER M4 ;
        RECT  0 34.752 0.084 34.776 ;
    END
  END i_data[63]
  PIN i_data[64]
    DIRECTION INPUT ;
    USE SIGNAL ;
    PORT
      LAYER M4 ;
        RECT  0 35.184 0.084 35.208 ;
    END
  END i_data[64]
  PIN i_data[65]
    DIRECTION INPUT ;
    USE SIGNAL ;
    PORT
      LAYER M4 ;
        RECT  0 35.616 0.084 35.64 ;
    END
  END i_data[65]
  PIN i_data[66]
    DIRECTION INPUT ;
    USE SIGNAL ;
    PORT
      LAYER M4 ;
        RECT  0 36.048 0.084 36.072 ;
    END
  END i_data[66]
  PIN i_data[67]
    DIRECTION INPUT ;
    USE SIGNAL ;
    PORT
      LAYER M4 ;
        RECT  0 36.48 0.084 36.504 ;
    END
  END i_data[67]
  PIN i_data[68]
    DIRECTION INPUT ;
    USE SIGNAL ;
    PORT
      LAYER M4 ;
        RECT  0 36.912 0.084 36.936 ;
    END
  END i_data[68]
  PIN i_data[69]
    DIRECTION INPUT ;
    USE SIGNAL ;
    PORT
      LAYER M4 ;
        RECT  0 37.344 0.084 37.368 ;
    END
  END i_data[69]
  PIN i_data[6]
    DIRECTION INPUT ;
    USE SIGNAL ;
    PORT
      LAYER M4 ;
        RECT  0 10.128 0.084 10.152 ;
    END
  END i_data[6]
  PIN i_data[70]
    DIRECTION INPUT ;
    USE SIGNAL ;
    PORT
      LAYER M4 ;
        RECT  0 37.776 0.084 37.8 ;
    END
  END i_data[70]
  PIN i_data[71]
    DIRECTION INPUT ;
    USE SIGNAL ;
    PORT
      LAYER M4 ;
        RECT  0 38.208 0.084 38.232 ;
    END
  END i_data[71]
  PIN i_data[72]
    DIRECTION INPUT ;
    USE SIGNAL ;
    PORT
      LAYER M4 ;
        RECT  0 38.64 0.084 38.664 ;
    END
  END i_data[72]
  PIN i_data[73]
    DIRECTION INPUT ;
    USE SIGNAL ;
    PORT
      LAYER M4 ;
        RECT  0 39.072 0.084 39.096 ;
    END
  END i_data[73]
  PIN i_data[74]
    DIRECTION INPUT ;
    USE SIGNAL ;
    PORT
      LAYER M4 ;
        RECT  0 39.504 0.084 39.528 ;
    END
  END i_data[74]
  PIN i_data[75]
    DIRECTION INPUT ;
    USE SIGNAL ;
    PORT
      LAYER M4 ;
        RECT  0 39.936 0.084 39.96 ;
    END
  END i_data[75]
  PIN i_data[76]
    DIRECTION INPUT ;
    USE SIGNAL ;
    PORT
      LAYER M4 ;
        RECT  0 40.368 0.084 40.392 ;
    END
  END i_data[76]
  PIN i_data[77]
    DIRECTION INPUT ;
    USE SIGNAL ;
    PORT
      LAYER M4 ;
        RECT  0 40.8 0.084 40.824 ;
    END
  END i_data[77]
  PIN i_data[78]
    DIRECTION INPUT ;
    USE SIGNAL ;
    PORT
      LAYER M4 ;
        RECT  0 41.232 0.084 41.256 ;
    END
  END i_data[78]
  PIN i_data[79]
    DIRECTION INPUT ;
    USE SIGNAL ;
    PORT
      LAYER M4 ;
        RECT  0 41.664 0.084 41.688 ;
    END
  END i_data[79]
  PIN i_data[7]
    DIRECTION INPUT ;
    USE SIGNAL ;
    PORT
      LAYER M4 ;
        RECT  0 10.56 0.084 10.584 ;
    END
  END i_data[7]
  PIN i_data[80]
    DIRECTION INPUT ;
    USE SIGNAL ;
    PORT
      LAYER M4 ;
        RECT  0 42.096 0.084 42.12 ;
    END
  END i_data[80]
  PIN i_data[81]
    DIRECTION INPUT ;
    USE SIGNAL ;
    PORT
      LAYER M4 ;
        RECT  0 42.528 0.084 42.552 ;
    END
  END i_data[81]
  PIN i_data[82]
    DIRECTION INPUT ;
    USE SIGNAL ;
    PORT
      LAYER M4 ;
        RECT  0 42.96 0.084 42.984 ;
    END
  END i_data[82]
  PIN i_data[83]
    DIRECTION INPUT ;
    USE SIGNAL ;
    PORT
      LAYER M4 ;
        RECT  0 43.392 0.084 43.416 ;
    END
  END i_data[83]
  PIN i_data[84]
    DIRECTION INPUT ;
    USE SIGNAL ;
    PORT
      LAYER M4 ;
        RECT  0 43.824 0.084 43.848 ;
    END
  END i_data[84]
  PIN i_data[85]
    DIRECTION INPUT ;
    USE SIGNAL ;
    PORT
      LAYER M4 ;
        RECT  0 44.256 0.084 44.28 ;
    END
  END i_data[85]
  PIN i_data[86]
    DIRECTION INPUT ;
    USE SIGNAL ;
    PORT
      LAYER M4 ;
        RECT  0 44.688 0.084 44.712 ;
    END
  END i_data[86]
  PIN i_data[87]
    DIRECTION INPUT ;
    USE SIGNAL ;
    PORT
      LAYER M4 ;
        RECT  0 45.12 0.084 45.144 ;
    END
  END i_data[87]
  PIN i_data[88]
    DIRECTION INPUT ;
    USE SIGNAL ;
    PORT
      LAYER M4 ;
        RECT  0 45.552 0.084 45.576 ;
    END
  END i_data[88]
  PIN i_data[89]
    DIRECTION INPUT ;
    USE SIGNAL ;
    PORT
      LAYER M4 ;
        RECT  0 45.984 0.084 46.008 ;
    END
  END i_data[89]
  PIN i_data[8]
    DIRECTION INPUT ;
    USE SIGNAL ;
    PORT
      LAYER M4 ;
        RECT  0 10.992 0.084 11.016 ;
    END
  END i_data[8]
  PIN i_data[90]
    DIRECTION INPUT ;
    USE SIGNAL ;
    PORT
      LAYER M4 ;
        RECT  0 46.416 0.084 46.44 ;
    END
  END i_data[90]
  PIN i_data[91]
    DIRECTION INPUT ;
    USE SIGNAL ;
    PORT
      LAYER M4 ;
        RECT  0 46.848 0.084 46.872 ;
    END
  END i_data[91]
  PIN i_data[92]
    DIRECTION INPUT ;
    USE SIGNAL ;
    PORT
      LAYER M4 ;
        RECT  0 47.28 0.084 47.304 ;
    END
  END i_data[92]
  PIN i_data[93]
    DIRECTION INPUT ;
    USE SIGNAL ;
    PORT
      LAYER M4 ;
        RECT  0 47.712 0.084 47.736 ;
    END
  END i_data[93]
  PIN i_data[94]
    DIRECTION INPUT ;
    USE SIGNAL ;
    PORT
      LAYER M4 ;
        RECT  0 48.144 0.084 48.168 ;
    END
  END i_data[94]
  PIN i_data[95]
    DIRECTION INPUT ;
    USE SIGNAL ;
    PORT
      LAYER M4 ;
        RECT  0 48.576 0.084 48.6 ;
    END
  END i_data[95]
  PIN i_data[96]
    DIRECTION INPUT ;
    USE SIGNAL ;
    PORT
      LAYER M4 ;
        RECT  0 49.008 0.084 49.032 ;
    END
  END i_data[96]
  PIN i_data[97]
    DIRECTION INPUT ;
    USE SIGNAL ;
    PORT
      LAYER M4 ;
        RECT  0 49.44 0.084 49.464 ;
    END
  END i_data[97]
  PIN i_data[98]
    DIRECTION INPUT ;
    USE SIGNAL ;
    PORT
      LAYER M4 ;
        RECT  0 49.872 0.084 49.896 ;
    END
  END i_data[98]
  PIN i_data[99]
    DIRECTION INPUT ;
    USE SIGNAL ;
    PORT
      LAYER M4 ;
        RECT  0 50.304 0.084 50.328 ;
    END
  END i_data[99]
  PIN i_data[9]
    DIRECTION INPUT ;
    USE SIGNAL ;
    PORT
      LAYER M4 ;
        RECT  0 11.424 0.084 11.448 ;
    END
  END i_data[9]
  PIN i_expected[0]
    DIRECTION INPUT ;
    USE SIGNAL ;
    PORT
      LAYER M4 ;
        RECT  0 119.856 0.084 119.88 ;
    END
  END i_expected[0]
  PIN i_expected[1]
    DIRECTION INPUT ;
    USE SIGNAL ;
    PORT
      LAYER M4 ;
        RECT  0 120.288 0.084 120.312 ;
    END
  END i_expected[1]
  PIN i_sel[0]
    DIRECTION INPUT ;
    USE SIGNAL ;
    PORT
      LAYER M4 ;
        RECT  0 120.72 0.084 120.744 ;
    END
  END i_sel[0]
  PIN i_sel[1]
    DIRECTION INPUT ;
    USE SIGNAL ;
    PORT
      LAYER M4 ;
        RECT  0 121.152 0.084 121.176 ;
    END
  END i_sel[1]
  PIN i_sel[2]
    DIRECTION INPUT ;
    USE SIGNAL ;
    PORT
      LAYER M4 ;
        RECT  0 121.584 0.084 121.608 ;
    END
  END i_sel[2]
  PIN i_sel[3]
    DIRECTION INPUT ;
    USE SIGNAL ;
    PORT
      LAYER M4 ;
        RECT  0 122.016 0.084 122.04 ;
    END
  END i_sel[3]
  PIN i_valid[0]
    DIRECTION INPUT ;
    USE SIGNAL ;
    PORT
      LAYER M4 ;
        RECT  0 118.128 0.084 118.152 ;
    END
  END i_valid[0]
  PIN i_valid[1]
    DIRECTION INPUT ;
    USE SIGNAL ;
    PORT
      LAYER M4 ;
        RECT  0 118.56 0.084 118.584 ;
    END
  END i_valid[1]
  PIN i_valid[2]
    DIRECTION INPUT ;
    USE SIGNAL ;
    PORT
      LAYER M4 ;
        RECT  0 118.992 0.084 119.016 ;
    END
  END i_valid[2]
  PIN i_valid[3]
    DIRECTION INPUT ;
    USE SIGNAL ;
    PORT
      LAYER M4 ;
        RECT  0 119.424 0.084 119.448 ;
    END
  END i_valid[3]
  PIN o_data[0]
    DIRECTION OUTPUT ;
    USE SIGNAL ;
    PORT
      LAYER M4 ;
        RECT  103.596 37.536 103.68 37.56 ;
    END
  END o_data[0]
  PIN o_data[100]
    DIRECTION OUTPUT ;
    USE SIGNAL ;
    PORT
      LAYER M4 ;
        RECT  103.596 80.736 103.68 80.76 ;
    END
  END o_data[100]
  PIN o_data[101]
    DIRECTION OUTPUT ;
    USE SIGNAL ;
    PORT
      LAYER M4 ;
        RECT  103.596 81.168 103.68 81.192 ;
    END
  END o_data[101]
  PIN o_data[102]
    DIRECTION OUTPUT ;
    USE SIGNAL ;
    PORT
      LAYER M4 ;
        RECT  103.596 81.6 103.68 81.624 ;
    END
  END o_data[102]
  PIN o_data[103]
    DIRECTION OUTPUT ;
    USE SIGNAL ;
    PORT
      LAYER M4 ;
        RECT  103.596 82.032 103.68 82.056 ;
    END
  END o_data[103]
  PIN o_data[104]
    DIRECTION OUTPUT ;
    USE SIGNAL ;
    PORT
      LAYER M4 ;
        RECT  103.596 82.464 103.68 82.488 ;
    END
  END o_data[104]
  PIN o_data[105]
    DIRECTION OUTPUT ;
    USE SIGNAL ;
    PORT
      LAYER M4 ;
        RECT  103.596 82.896 103.68 82.92 ;
    END
  END o_data[105]
  PIN o_data[106]
    DIRECTION OUTPUT ;
    USE SIGNAL ;
    PORT
      LAYER M4 ;
        RECT  103.596 83.328 103.68 83.352 ;
    END
  END o_data[106]
  PIN o_data[107]
    DIRECTION OUTPUT ;
    USE SIGNAL ;
    PORT
      LAYER M4 ;
        RECT  103.596 83.76 103.68 83.784 ;
    END
  END o_data[107]
  PIN o_data[108]
    DIRECTION OUTPUT ;
    USE SIGNAL ;
    PORT
      LAYER M4 ;
        RECT  103.596 84.192 103.68 84.216 ;
    END
  END o_data[108]
  PIN o_data[109]
    DIRECTION OUTPUT ;
    USE SIGNAL ;
    PORT
      LAYER M4 ;
        RECT  103.596 84.624 103.68 84.648 ;
    END
  END o_data[109]
  PIN o_data[10]
    DIRECTION OUTPUT ;
    USE SIGNAL ;
    PORT
      LAYER M4 ;
        RECT  103.596 41.856 103.68 41.88 ;
    END
  END o_data[10]
  PIN o_data[110]
    DIRECTION OUTPUT ;
    USE SIGNAL ;
    PORT
      LAYER M4 ;
        RECT  103.596 85.056 103.68 85.08 ;
    END
  END o_data[110]
  PIN o_data[111]
    DIRECTION OUTPUT ;
    USE SIGNAL ;
    PORT
      LAYER M4 ;
        RECT  103.596 85.488 103.68 85.512 ;
    END
  END o_data[111]
  PIN o_data[112]
    DIRECTION OUTPUT ;
    USE SIGNAL ;
    PORT
      LAYER M4 ;
        RECT  103.596 85.92 103.68 85.944 ;
    END
  END o_data[112]
  PIN o_data[113]
    DIRECTION OUTPUT ;
    USE SIGNAL ;
    PORT
      LAYER M4 ;
        RECT  103.596 86.352 103.68 86.376 ;
    END
  END o_data[113]
  PIN o_data[114]
    DIRECTION OUTPUT ;
    USE SIGNAL ;
    PORT
      LAYER M4 ;
        RECT  103.596 86.784 103.68 86.808 ;
    END
  END o_data[114]
  PIN o_data[115]
    DIRECTION OUTPUT ;
    USE SIGNAL ;
    PORT
      LAYER M4 ;
        RECT  103.596 87.216 103.68 87.24 ;
    END
  END o_data[115]
  PIN o_data[116]
    DIRECTION OUTPUT ;
    USE SIGNAL ;
    PORT
      LAYER M4 ;
        RECT  103.596 87.648 103.68 87.672 ;
    END
  END o_data[116]
  PIN o_data[117]
    DIRECTION OUTPUT ;
    USE SIGNAL ;
    PORT
      LAYER M4 ;
        RECT  103.596 88.08 103.68 88.104 ;
    END
  END o_data[117]
  PIN o_data[118]
    DIRECTION OUTPUT ;
    USE SIGNAL ;
    PORT
      LAYER M4 ;
        RECT  103.596 88.512 103.68 88.536 ;
    END
  END o_data[118]
  PIN o_data[119]
    DIRECTION OUTPUT ;
    USE SIGNAL ;
    PORT
      LAYER M4 ;
        RECT  103.596 88.944 103.68 88.968 ;
    END
  END o_data[119]
  PIN o_data[11]
    DIRECTION OUTPUT ;
    USE SIGNAL ;
    PORT
      LAYER M4 ;
        RECT  103.596 42.288 103.68 42.312 ;
    END
  END o_data[11]
  PIN o_data[120]
    DIRECTION OUTPUT ;
    USE SIGNAL ;
    PORT
      LAYER M4 ;
        RECT  103.596 89.376 103.68 89.4 ;
    END
  END o_data[120]
  PIN o_data[121]
    DIRECTION OUTPUT ;
    USE SIGNAL ;
    PORT
      LAYER M4 ;
        RECT  103.596 89.808 103.68 89.832 ;
    END
  END o_data[121]
  PIN o_data[122]
    DIRECTION OUTPUT ;
    USE SIGNAL ;
    PORT
      LAYER M4 ;
        RECT  103.596 90.24 103.68 90.264 ;
    END
  END o_data[122]
  PIN o_data[123]
    DIRECTION OUTPUT ;
    USE SIGNAL ;
    PORT
      LAYER M4 ;
        RECT  103.596 90.672 103.68 90.696 ;
    END
  END o_data[123]
  PIN o_data[124]
    DIRECTION OUTPUT ;
    USE SIGNAL ;
    PORT
      LAYER M4 ;
        RECT  103.596 91.104 103.68 91.128 ;
    END
  END o_data[124]
  PIN o_data[125]
    DIRECTION OUTPUT ;
    USE SIGNAL ;
    PORT
      LAYER M4 ;
        RECT  103.596 91.536 103.68 91.56 ;
    END
  END o_data[125]
  PIN o_data[126]
    DIRECTION OUTPUT ;
    USE SIGNAL ;
    PORT
      LAYER M4 ;
        RECT  103.596 91.968 103.68 91.992 ;
    END
  END o_data[126]
  PIN o_data[127]
    DIRECTION OUTPUT ;
    USE SIGNAL ;
    PORT
      LAYER M4 ;
        RECT  103.596 92.4 103.68 92.424 ;
    END
  END o_data[127]
  PIN o_data[12]
    DIRECTION OUTPUT ;
    USE SIGNAL ;
    PORT
      LAYER M4 ;
        RECT  103.596 42.72 103.68 42.744 ;
    END
  END o_data[12]
  PIN o_data[13]
    DIRECTION OUTPUT ;
    USE SIGNAL ;
    PORT
      LAYER M4 ;
        RECT  103.596 43.152 103.68 43.176 ;
    END
  END o_data[13]
  PIN o_data[14]
    DIRECTION OUTPUT ;
    USE SIGNAL ;
    PORT
      LAYER M4 ;
        RECT  103.596 43.584 103.68 43.608 ;
    END
  END o_data[14]
  PIN o_data[15]
    DIRECTION OUTPUT ;
    USE SIGNAL ;
    PORT
      LAYER M4 ;
        RECT  103.596 44.016 103.68 44.04 ;
    END
  END o_data[15]
  PIN o_data[16]
    DIRECTION OUTPUT ;
    USE SIGNAL ;
    PORT
      LAYER M4 ;
        RECT  103.596 44.448 103.68 44.472 ;
    END
  END o_data[16]
  PIN o_data[17]
    DIRECTION OUTPUT ;
    USE SIGNAL ;
    PORT
      LAYER M4 ;
        RECT  103.596 44.88 103.68 44.904 ;
    END
  END o_data[17]
  PIN o_data[18]
    DIRECTION OUTPUT ;
    USE SIGNAL ;
    PORT
      LAYER M4 ;
        RECT  103.596 45.312 103.68 45.336 ;
    END
  END o_data[18]
  PIN o_data[19]
    DIRECTION OUTPUT ;
    USE SIGNAL ;
    PORT
      LAYER M4 ;
        RECT  103.596 45.744 103.68 45.768 ;
    END
  END o_data[19]
  PIN o_data[1]
    DIRECTION OUTPUT ;
    USE SIGNAL ;
    PORT
      LAYER M4 ;
        RECT  103.596 37.968 103.68 37.992 ;
    END
  END o_data[1]
  PIN o_data[20]
    DIRECTION OUTPUT ;
    USE SIGNAL ;
    PORT
      LAYER M4 ;
        RECT  103.596 46.176 103.68 46.2 ;
    END
  END o_data[20]
  PIN o_data[21]
    DIRECTION OUTPUT ;
    USE SIGNAL ;
    PORT
      LAYER M4 ;
        RECT  103.596 46.608 103.68 46.632 ;
    END
  END o_data[21]
  PIN o_data[22]
    DIRECTION OUTPUT ;
    USE SIGNAL ;
    PORT
      LAYER M4 ;
        RECT  103.596 47.04 103.68 47.064 ;
    END
  END o_data[22]
  PIN o_data[23]
    DIRECTION OUTPUT ;
    USE SIGNAL ;
    PORT
      LAYER M4 ;
        RECT  103.596 47.472 103.68 47.496 ;
    END
  END o_data[23]
  PIN o_data[24]
    DIRECTION OUTPUT ;
    USE SIGNAL ;
    PORT
      LAYER M4 ;
        RECT  103.596 47.904 103.68 47.928 ;
    END
  END o_data[24]
  PIN o_data[25]
    DIRECTION OUTPUT ;
    USE SIGNAL ;
    PORT
      LAYER M4 ;
        RECT  103.596 48.336 103.68 48.36 ;
    END
  END o_data[25]
  PIN o_data[26]
    DIRECTION OUTPUT ;
    USE SIGNAL ;
    PORT
      LAYER M4 ;
        RECT  103.596 48.768 103.68 48.792 ;
    END
  END o_data[26]
  PIN o_data[27]
    DIRECTION OUTPUT ;
    USE SIGNAL ;
    PORT
      LAYER M4 ;
        RECT  103.596 49.2 103.68 49.224 ;
    END
  END o_data[27]
  PIN o_data[28]
    DIRECTION OUTPUT ;
    USE SIGNAL ;
    PORT
      LAYER M4 ;
        RECT  103.596 49.632 103.68 49.656 ;
    END
  END o_data[28]
  PIN o_data[29]
    DIRECTION OUTPUT ;
    USE SIGNAL ;
    PORT
      LAYER M4 ;
        RECT  103.596 50.064 103.68 50.088 ;
    END
  END o_data[29]
  PIN o_data[2]
    DIRECTION OUTPUT ;
    USE SIGNAL ;
    PORT
      LAYER M4 ;
        RECT  103.596 38.4 103.68 38.424 ;
    END
  END o_data[2]
  PIN o_data[30]
    DIRECTION OUTPUT ;
    USE SIGNAL ;
    PORT
      LAYER M4 ;
        RECT  103.596 50.496 103.68 50.52 ;
    END
  END o_data[30]
  PIN o_data[31]
    DIRECTION OUTPUT ;
    USE SIGNAL ;
    PORT
      LAYER M4 ;
        RECT  103.596 50.928 103.68 50.952 ;
    END
  END o_data[31]
  PIN o_data[32]
    DIRECTION OUTPUT ;
    USE SIGNAL ;
    PORT
      LAYER M4 ;
        RECT  103.596 51.36 103.68 51.384 ;
    END
  END o_data[32]
  PIN o_data[33]
    DIRECTION OUTPUT ;
    USE SIGNAL ;
    PORT
      LAYER M4 ;
        RECT  103.596 51.792 103.68 51.816 ;
    END
  END o_data[33]
  PIN o_data[34]
    DIRECTION OUTPUT ;
    USE SIGNAL ;
    PORT
      LAYER M4 ;
        RECT  103.596 52.224 103.68 52.248 ;
    END
  END o_data[34]
  PIN o_data[35]
    DIRECTION OUTPUT ;
    USE SIGNAL ;
    PORT
      LAYER M4 ;
        RECT  103.596 52.656 103.68 52.68 ;
    END
  END o_data[35]
  PIN o_data[36]
    DIRECTION OUTPUT ;
    USE SIGNAL ;
    PORT
      LAYER M4 ;
        RECT  103.596 53.088 103.68 53.112 ;
    END
  END o_data[36]
  PIN o_data[37]
    DIRECTION OUTPUT ;
    USE SIGNAL ;
    PORT
      LAYER M4 ;
        RECT  103.596 53.52 103.68 53.544 ;
    END
  END o_data[37]
  PIN o_data[38]
    DIRECTION OUTPUT ;
    USE SIGNAL ;
    PORT
      LAYER M4 ;
        RECT  103.596 53.952 103.68 53.976 ;
    END
  END o_data[38]
  PIN o_data[39]
    DIRECTION OUTPUT ;
    USE SIGNAL ;
    PORT
      LAYER M4 ;
        RECT  103.596 54.384 103.68 54.408 ;
    END
  END o_data[39]
  PIN o_data[3]
    DIRECTION OUTPUT ;
    USE SIGNAL ;
    PORT
      LAYER M4 ;
        RECT  103.596 38.832 103.68 38.856 ;
    END
  END o_data[3]
  PIN o_data[40]
    DIRECTION OUTPUT ;
    USE SIGNAL ;
    PORT
      LAYER M4 ;
        RECT  103.596 54.816 103.68 54.84 ;
    END
  END o_data[40]
  PIN o_data[41]
    DIRECTION OUTPUT ;
    USE SIGNAL ;
    PORT
      LAYER M4 ;
        RECT  103.596 55.248 103.68 55.272 ;
    END
  END o_data[41]
  PIN o_data[42]
    DIRECTION OUTPUT ;
    USE SIGNAL ;
    PORT
      LAYER M4 ;
        RECT  103.596 55.68 103.68 55.704 ;
    END
  END o_data[42]
  PIN o_data[43]
    DIRECTION OUTPUT ;
    USE SIGNAL ;
    PORT
      LAYER M4 ;
        RECT  103.596 56.112 103.68 56.136 ;
    END
  END o_data[43]
  PIN o_data[44]
    DIRECTION OUTPUT ;
    USE SIGNAL ;
    PORT
      LAYER M4 ;
        RECT  103.596 56.544 103.68 56.568 ;
    END
  END o_data[44]
  PIN o_data[45]
    DIRECTION OUTPUT ;
    USE SIGNAL ;
    PORT
      LAYER M4 ;
        RECT  103.596 56.976 103.68 57 ;
    END
  END o_data[45]
  PIN o_data[46]
    DIRECTION OUTPUT ;
    USE SIGNAL ;
    PORT
      LAYER M4 ;
        RECT  103.596 57.408 103.68 57.432 ;
    END
  END o_data[46]
  PIN o_data[47]
    DIRECTION OUTPUT ;
    USE SIGNAL ;
    PORT
      LAYER M4 ;
        RECT  103.596 57.84 103.68 57.864 ;
    END
  END o_data[47]
  PIN o_data[48]
    DIRECTION OUTPUT ;
    USE SIGNAL ;
    PORT
      LAYER M4 ;
        RECT  103.596 58.272 103.68 58.296 ;
    END
  END o_data[48]
  PIN o_data[49]
    DIRECTION OUTPUT ;
    USE SIGNAL ;
    PORT
      LAYER M4 ;
        RECT  103.596 58.704 103.68 58.728 ;
    END
  END o_data[49]
  PIN o_data[4]
    DIRECTION OUTPUT ;
    USE SIGNAL ;
    PORT
      LAYER M4 ;
        RECT  103.596 39.264 103.68 39.288 ;
    END
  END o_data[4]
  PIN o_data[50]
    DIRECTION OUTPUT ;
    USE SIGNAL ;
    PORT
      LAYER M4 ;
        RECT  103.596 59.136 103.68 59.16 ;
    END
  END o_data[50]
  PIN o_data[51]
    DIRECTION OUTPUT ;
    USE SIGNAL ;
    PORT
      LAYER M4 ;
        RECT  103.596 59.568 103.68 59.592 ;
    END
  END o_data[51]
  PIN o_data[52]
    DIRECTION OUTPUT ;
    USE SIGNAL ;
    PORT
      LAYER M4 ;
        RECT  103.596 60 103.68 60.024 ;
    END
  END o_data[52]
  PIN o_data[53]
    DIRECTION OUTPUT ;
    USE SIGNAL ;
    PORT
      LAYER M4 ;
        RECT  103.596 60.432 103.68 60.456 ;
    END
  END o_data[53]
  PIN o_data[54]
    DIRECTION OUTPUT ;
    USE SIGNAL ;
    PORT
      LAYER M4 ;
        RECT  103.596 60.864 103.68 60.888 ;
    END
  END o_data[54]
  PIN o_data[55]
    DIRECTION OUTPUT ;
    USE SIGNAL ;
    PORT
      LAYER M4 ;
        RECT  103.596 61.296 103.68 61.32 ;
    END
  END o_data[55]
  PIN o_data[56]
    DIRECTION OUTPUT ;
    USE SIGNAL ;
    PORT
      LAYER M4 ;
        RECT  103.596 61.728 103.68 61.752 ;
    END
  END o_data[56]
  PIN o_data[57]
    DIRECTION OUTPUT ;
    USE SIGNAL ;
    PORT
      LAYER M4 ;
        RECT  103.596 62.16 103.68 62.184 ;
    END
  END o_data[57]
  PIN o_data[58]
    DIRECTION OUTPUT ;
    USE SIGNAL ;
    PORT
      LAYER M4 ;
        RECT  103.596 62.592 103.68 62.616 ;
    END
  END o_data[58]
  PIN o_data[59]
    DIRECTION OUTPUT ;
    USE SIGNAL ;
    PORT
      LAYER M4 ;
        RECT  103.596 63.024 103.68 63.048 ;
    END
  END o_data[59]
  PIN o_data[5]
    DIRECTION OUTPUT ;
    USE SIGNAL ;
    PORT
      LAYER M4 ;
        RECT  103.596 39.696 103.68 39.72 ;
    END
  END o_data[5]
  PIN o_data[60]
    DIRECTION OUTPUT ;
    USE SIGNAL ;
    PORT
      LAYER M4 ;
        RECT  103.596 63.456 103.68 63.48 ;
    END
  END o_data[60]
  PIN o_data[61]
    DIRECTION OUTPUT ;
    USE SIGNAL ;
    PORT
      LAYER M4 ;
        RECT  103.596 63.888 103.68 63.912 ;
    END
  END o_data[61]
  PIN o_data[62]
    DIRECTION OUTPUT ;
    USE SIGNAL ;
    PORT
      LAYER M4 ;
        RECT  103.596 64.32 103.68 64.344 ;
    END
  END o_data[62]
  PIN o_data[63]
    DIRECTION OUTPUT ;
    USE SIGNAL ;
    PORT
      LAYER M4 ;
        RECT  103.596 64.752 103.68 64.776 ;
    END
  END o_data[63]
  PIN o_data[64]
    DIRECTION OUTPUT ;
    USE SIGNAL ;
    PORT
      LAYER M4 ;
        RECT  103.596 65.184 103.68 65.208 ;
    END
  END o_data[64]
  PIN o_data[65]
    DIRECTION OUTPUT ;
    USE SIGNAL ;
    PORT
      LAYER M4 ;
        RECT  103.596 65.616 103.68 65.64 ;
    END
  END o_data[65]
  PIN o_data[66]
    DIRECTION OUTPUT ;
    USE SIGNAL ;
    PORT
      LAYER M4 ;
        RECT  103.596 66.048 103.68 66.072 ;
    END
  END o_data[66]
  PIN o_data[67]
    DIRECTION OUTPUT ;
    USE SIGNAL ;
    PORT
      LAYER M4 ;
        RECT  103.596 66.48 103.68 66.504 ;
    END
  END o_data[67]
  PIN o_data[68]
    DIRECTION OUTPUT ;
    USE SIGNAL ;
    PORT
      LAYER M4 ;
        RECT  103.596 66.912 103.68 66.936 ;
    END
  END o_data[68]
  PIN o_data[69]
    DIRECTION OUTPUT ;
    USE SIGNAL ;
    PORT
      LAYER M4 ;
        RECT  103.596 67.344 103.68 67.368 ;
    END
  END o_data[69]
  PIN o_data[6]
    DIRECTION OUTPUT ;
    USE SIGNAL ;
    PORT
      LAYER M4 ;
        RECT  103.596 40.128 103.68 40.152 ;
    END
  END o_data[6]
  PIN o_data[70]
    DIRECTION OUTPUT ;
    USE SIGNAL ;
    PORT
      LAYER M4 ;
        RECT  103.596 67.776 103.68 67.8 ;
    END
  END o_data[70]
  PIN o_data[71]
    DIRECTION OUTPUT ;
    USE SIGNAL ;
    PORT
      LAYER M4 ;
        RECT  103.596 68.208 103.68 68.232 ;
    END
  END o_data[71]
  PIN o_data[72]
    DIRECTION OUTPUT ;
    USE SIGNAL ;
    PORT
      LAYER M4 ;
        RECT  103.596 68.64 103.68 68.664 ;
    END
  END o_data[72]
  PIN o_data[73]
    DIRECTION OUTPUT ;
    USE SIGNAL ;
    PORT
      LAYER M4 ;
        RECT  103.596 69.072 103.68 69.096 ;
    END
  END o_data[73]
  PIN o_data[74]
    DIRECTION OUTPUT ;
    USE SIGNAL ;
    PORT
      LAYER M4 ;
        RECT  103.596 69.504 103.68 69.528 ;
    END
  END o_data[74]
  PIN o_data[75]
    DIRECTION OUTPUT ;
    USE SIGNAL ;
    PORT
      LAYER M4 ;
        RECT  103.596 69.936 103.68 69.96 ;
    END
  END o_data[75]
  PIN o_data[76]
    DIRECTION OUTPUT ;
    USE SIGNAL ;
    PORT
      LAYER M4 ;
        RECT  103.596 70.368 103.68 70.392 ;
    END
  END o_data[76]
  PIN o_data[77]
    DIRECTION OUTPUT ;
    USE SIGNAL ;
    PORT
      LAYER M4 ;
        RECT  103.596 70.8 103.68 70.824 ;
    END
  END o_data[77]
  PIN o_data[78]
    DIRECTION OUTPUT ;
    USE SIGNAL ;
    PORT
      LAYER M4 ;
        RECT  103.596 71.232 103.68 71.256 ;
    END
  END o_data[78]
  PIN o_data[79]
    DIRECTION OUTPUT ;
    USE SIGNAL ;
    PORT
      LAYER M4 ;
        RECT  103.596 71.664 103.68 71.688 ;
    END
  END o_data[79]
  PIN o_data[7]
    DIRECTION OUTPUT ;
    USE SIGNAL ;
    PORT
      LAYER M4 ;
        RECT  103.596 40.56 103.68 40.584 ;
    END
  END o_data[7]
  PIN o_data[80]
    DIRECTION OUTPUT ;
    USE SIGNAL ;
    PORT
      LAYER M4 ;
        RECT  103.596 72.096 103.68 72.12 ;
    END
  END o_data[80]
  PIN o_data[81]
    DIRECTION OUTPUT ;
    USE SIGNAL ;
    PORT
      LAYER M4 ;
        RECT  103.596 72.528 103.68 72.552 ;
    END
  END o_data[81]
  PIN o_data[82]
    DIRECTION OUTPUT ;
    USE SIGNAL ;
    PORT
      LAYER M4 ;
        RECT  103.596 72.96 103.68 72.984 ;
    END
  END o_data[82]
  PIN o_data[83]
    DIRECTION OUTPUT ;
    USE SIGNAL ;
    PORT
      LAYER M4 ;
        RECT  103.596 73.392 103.68 73.416 ;
    END
  END o_data[83]
  PIN o_data[84]
    DIRECTION OUTPUT ;
    USE SIGNAL ;
    PORT
      LAYER M4 ;
        RECT  103.596 73.824 103.68 73.848 ;
    END
  END o_data[84]
  PIN o_data[85]
    DIRECTION OUTPUT ;
    USE SIGNAL ;
    PORT
      LAYER M4 ;
        RECT  103.596 74.256 103.68 74.28 ;
    END
  END o_data[85]
  PIN o_data[86]
    DIRECTION OUTPUT ;
    USE SIGNAL ;
    PORT
      LAYER M4 ;
        RECT  103.596 74.688 103.68 74.712 ;
    END
  END o_data[86]
  PIN o_data[87]
    DIRECTION OUTPUT ;
    USE SIGNAL ;
    PORT
      LAYER M4 ;
        RECT  103.596 75.12 103.68 75.144 ;
    END
  END o_data[87]
  PIN o_data[88]
    DIRECTION OUTPUT ;
    USE SIGNAL ;
    PORT
      LAYER M4 ;
        RECT  103.596 75.552 103.68 75.576 ;
    END
  END o_data[88]
  PIN o_data[89]
    DIRECTION OUTPUT ;
    USE SIGNAL ;
    PORT
      LAYER M4 ;
        RECT  103.596 75.984 103.68 76.008 ;
    END
  END o_data[89]
  PIN o_data[8]
    DIRECTION OUTPUT ;
    USE SIGNAL ;
    PORT
      LAYER M4 ;
        RECT  103.596 40.992 103.68 41.016 ;
    END
  END o_data[8]
  PIN o_data[90]
    DIRECTION OUTPUT ;
    USE SIGNAL ;
    PORT
      LAYER M4 ;
        RECT  103.596 76.416 103.68 76.44 ;
    END
  END o_data[90]
  PIN o_data[91]
    DIRECTION OUTPUT ;
    USE SIGNAL ;
    PORT
      LAYER M4 ;
        RECT  103.596 76.848 103.68 76.872 ;
    END
  END o_data[91]
  PIN o_data[92]
    DIRECTION OUTPUT ;
    USE SIGNAL ;
    PORT
      LAYER M4 ;
        RECT  103.596 77.28 103.68 77.304 ;
    END
  END o_data[92]
  PIN o_data[93]
    DIRECTION OUTPUT ;
    USE SIGNAL ;
    PORT
      LAYER M4 ;
        RECT  103.596 77.712 103.68 77.736 ;
    END
  END o_data[93]
  PIN o_data[94]
    DIRECTION OUTPUT ;
    USE SIGNAL ;
    PORT
      LAYER M4 ;
        RECT  103.596 78.144 103.68 78.168 ;
    END
  END o_data[94]
  PIN o_data[95]
    DIRECTION OUTPUT ;
    USE SIGNAL ;
    PORT
      LAYER M4 ;
        RECT  103.596 78.576 103.68 78.6 ;
    END
  END o_data[95]
  PIN o_data[96]
    DIRECTION OUTPUT ;
    USE SIGNAL ;
    PORT
      LAYER M4 ;
        RECT  103.596 79.008 103.68 79.032 ;
    END
  END o_data[96]
  PIN o_data[97]
    DIRECTION OUTPUT ;
    USE SIGNAL ;
    PORT
      LAYER M4 ;
        RECT  103.596 79.44 103.68 79.464 ;
    END
  END o_data[97]
  PIN o_data[98]
    DIRECTION OUTPUT ;
    USE SIGNAL ;
    PORT
      LAYER M4 ;
        RECT  103.596 79.872 103.68 79.896 ;
    END
  END o_data[98]
  PIN o_data[99]
    DIRECTION OUTPUT ;
    USE SIGNAL ;
    PORT
      LAYER M4 ;
        RECT  103.596 80.304 103.68 80.328 ;
    END
  END o_data[99]
  PIN o_data[9]
    DIRECTION OUTPUT ;
    USE SIGNAL ;
    PORT
      LAYER M4 ;
        RECT  103.596 41.424 103.68 41.448 ;
    END
  END o_data[9]
  PIN o_partial_valid[0]
    DIRECTION OUTPUT ;
    USE SIGNAL ;
    PORT
      LAYER M4 ;
        RECT  103.596 36.672 103.68 36.696 ;
    END
  END o_partial_valid[0]
  PIN o_partial_valid[1]
    DIRECTION OUTPUT ;
    USE SIGNAL ;
    PORT
      LAYER M4 ;
        RECT  103.596 37.104 103.68 37.128 ;
    END
  END o_partial_valid[1]
  PIN rst_n
    DIRECTION INPUT ;
    USE SIGNAL ;
    PORT
      LAYER M5 ;
        RECT  52.032 129.516 52.056 129.6 ;
    END
  END rst_n
  PIN VDD
    DIRECTION INOUT ;
    USE POWER ;
    PORT
      LAYER M5 ;
        RECT  99.792 2.151 99.912 127.449 ;
        RECT  94.392 2.151 94.512 127.449 ;
        RECT  88.992 2.151 89.112 127.449 ;
        RECT  83.592 2.151 83.712 127.449 ;
        RECT  78.192 2.151 78.312 127.449 ;
        RECT  72.792 2.151 72.912 127.449 ;
        RECT  67.392 2.151 67.512 127.449 ;
        RECT  61.992 2.151 62.112 127.449 ;
        RECT  56.592 2.151 56.712 127.449 ;
        RECT  51.192 2.151 51.312 127.449 ;
        RECT  45.792 2.151 45.912 127.449 ;
        RECT  40.392 2.151 40.512 127.449 ;
        RECT  34.992 2.151 35.112 127.449 ;
        RECT  29.592 2.151 29.712 127.449 ;
        RECT  24.192 2.151 24.312 127.449 ;
        RECT  18.792 2.151 18.912 127.449 ;
        RECT  13.392 2.151 13.512 127.449 ;
        RECT  7.992 2.151 8.112 127.449 ;
        RECT  2.592 2.151 2.712 127.449 ;
    END
  END VDD
  PIN VSS
    DIRECTION INOUT ;
    USE GROUND ;
    PORT
      LAYER M5 ;
        RECT  99.6 2.137 99.72 127.463 ;
        RECT  94.2 2.137 94.32 127.463 ;
        RECT  88.8 2.137 88.92 127.463 ;
        RECT  83.4 2.137 83.52 127.463 ;
        RECT  78 2.137 78.12 127.463 ;
        RECT  72.6 2.137 72.72 127.463 ;
        RECT  67.2 2.137 67.32 127.463 ;
        RECT  61.8 2.137 61.92 127.463 ;
        RECT  56.4 2.137 56.52 127.463 ;
        RECT  51 2.137 51.12 127.463 ;
        RECT  45.6 2.137 45.72 127.463 ;
        RECT  40.2 2.137 40.32 127.463 ;
        RECT  34.8 2.137 34.92 127.463 ;
        RECT  29.4 2.137 29.52 127.463 ;
        RECT  24 2.137 24.12 127.463 ;
        RECT  18.6 2.137 18.72 127.463 ;
        RECT  13.2 2.137 13.32 127.463 ;
        RECT  7.8 2.137 7.92 127.463 ;
        RECT  2.4 2.137 2.52 127.463 ;
    END
  END VSS
  # OT_OBS_CLOSED layer=M5 d_um=1.536 added=50
  OBS
    LAYER RVTN ;
     RECT  2.16 2.16 101.52 2.295 ;
     RECT  2.16 2.565 101.52 2.835 ;
     RECT  2.16 3.105 101.52 3.375 ;
     RECT  2.16 3.645 101.52 3.915 ;
     RECT  2.16 4.185 101.52 4.455 ;
     RECT  2.16 4.725 101.52 4.995 ;
     RECT  2.16 5.265 101.52 5.535 ;
     RECT  2.16 5.805 101.52 6.075 ;
     RECT  2.16 6.345 101.52 6.615 ;
     RECT  2.16 6.885 101.52 7.155 ;
     RECT  2.16 7.425 101.52 7.695 ;
     RECT  2.16 7.965 101.52 8.235 ;
     RECT  2.16 8.505 101.52 8.775 ;
     RECT  2.16 9.045 101.52 9.315 ;
     RECT  2.16 9.585 101.52 9.855 ;
     RECT  2.16 10.125 101.52 10.395 ;
     RECT  2.16 10.665 101.52 10.935 ;
     RECT  2.16 11.205 101.52 11.475 ;
     RECT  2.16 11.745 101.52 12.015 ;
     RECT  2.16 12.285 101.52 12.555 ;
     RECT  2.16 12.825 101.52 13.095 ;
     RECT  2.16 13.365 101.52 13.635 ;
     RECT  2.16 13.905 101.52 14.175 ;
     RECT  2.16 14.445 101.52 14.715 ;
     RECT  2.16 14.985 101.52 15.255 ;
     RECT  2.16 15.525 101.52 15.795 ;
     RECT  2.16 16.065 101.52 16.335 ;
     RECT  2.16 16.605 101.52 16.875 ;
     RECT  2.16 17.145 101.52 17.415 ;
     RECT  2.16 17.685 101.52 17.955 ;
     RECT  2.16 18.225 101.52 18.495 ;
     RECT  2.16 18.765 101.52 19.035 ;
     RECT  2.16 19.305 101.52 19.575 ;
     RECT  2.16 19.845 101.52 20.115 ;
     RECT  2.16 20.385 101.52 20.655 ;
     RECT  2.16 20.925 101.52 21.195 ;
     RECT  2.16 21.465 101.52 21.735 ;
     RECT  2.16 22.005 101.52 22.275 ;
     RECT  2.16 22.545 101.52 22.815 ;
     RECT  2.16 23.085 101.52 23.355 ;
     RECT  2.16 23.625 101.52 23.895 ;
     RECT  2.16 24.165 101.52 24.435 ;
     RECT  2.16 24.705 101.52 24.975 ;
     RECT  2.16 25.245 101.52 25.515 ;
     RECT  2.16 25.785 101.52 26.055 ;
     RECT  2.16 26.325 101.52 26.595 ;
     RECT  2.16 26.865 101.52 27.135 ;
     RECT  2.16 27.405 101.52 27.675 ;
     RECT  2.16 27.945 101.52 28.215 ;
     RECT  2.16 28.485 101.52 28.755 ;
     RECT  2.16 29.025 101.52 29.295 ;
     RECT  2.16 29.565 101.52 29.835 ;
     RECT  2.16 30.105 101.52 30.375 ;
     RECT  2.16 30.645 101.52 30.915 ;
     RECT  2.16 31.185 101.52 31.455 ;
     RECT  2.16 31.725 101.52 31.995 ;
     RECT  2.16 32.265 101.52 32.535 ;
     RECT  2.16 32.805 101.52 33.075 ;
     RECT  2.16 33.345 101.52 33.615 ;
     RECT  2.16 33.885 101.52 34.155 ;
     RECT  2.16 34.425 101.52 34.695 ;
     RECT  2.16 34.965 101.52 35.235 ;
     RECT  2.16 35.505 101.52 35.775 ;
     RECT  2.16 36.045 101.52 36.315 ;
     RECT  2.16 36.585 101.52 36.855 ;
     RECT  2.16 37.125 101.52 37.395 ;
     RECT  2.16 37.665 101.52 37.935 ;
     RECT  2.16 38.205 101.52 38.475 ;
     RECT  2.16 38.745 101.52 39.015 ;
     RECT  2.16 39.285 101.52 39.555 ;
     RECT  2.16 39.825 101.52 40.095 ;
     RECT  2.16 40.365 101.52 40.635 ;
     RECT  2.16 40.905 101.52 41.175 ;
     RECT  2.16 41.445 101.52 41.715 ;
     RECT  2.16 41.985 101.52 42.255 ;
     RECT  2.16 42.525 101.52 42.795 ;
     RECT  2.16 43.065 101.52 43.335 ;
     RECT  2.16 43.605 101.52 43.875 ;
     RECT  2.16 44.145 101.52 44.415 ;
     RECT  2.16 44.685 101.52 44.955 ;
     RECT  2.16 45.225 101.52 45.495 ;
     RECT  2.16 45.765 101.52 46.035 ;
     RECT  2.16 46.305 101.52 46.575 ;
     RECT  2.16 46.845 101.52 47.115 ;
     RECT  2.16 47.385 101.52 47.655 ;
     RECT  2.16 47.925 101.52 48.195 ;
     RECT  2.16 48.465 101.52 48.735 ;
     RECT  2.16 49.005 101.52 49.275 ;
     RECT  2.16 49.545 101.52 49.815 ;
     RECT  2.16 50.085 101.52 50.355 ;
     RECT  2.16 50.625 101.52 50.895 ;
     RECT  2.16 51.165 101.52 51.435 ;
     RECT  2.16 51.705 101.52 51.975 ;
     RECT  2.16 52.245 101.52 52.515 ;
     RECT  2.16 52.785 101.52 53.055 ;
     RECT  2.16 53.325 101.52 53.595 ;
     RECT  2.16 53.865 101.52 54.135 ;
     RECT  2.16 54.405 101.52 54.675 ;
     RECT  2.16 54.945 101.52 55.215 ;
     RECT  2.16 55.485 101.52 55.755 ;
     RECT  2.16 56.025 101.52 56.295 ;
     RECT  2.16 56.565 101.52 56.835 ;
     RECT  2.16 57.105 101.52 57.375 ;
     RECT  2.16 57.645 101.52 57.915 ;
     RECT  2.16 58.185 101.52 58.455 ;
     RECT  2.16 58.725 101.52 58.995 ;
     RECT  2.16 59.265 101.52 59.535 ;
     RECT  2.16 59.805 101.52 60.075 ;
     RECT  2.16 60.345 101.52 60.615 ;
     RECT  2.16 60.885 101.52 61.155 ;
     RECT  2.16 61.425 101.52 61.695 ;
     RECT  2.16 61.965 101.52 62.235 ;
     RECT  2.16 62.505 101.52 62.775 ;
     RECT  2.16 63.045 101.52 63.315 ;
     RECT  2.16 63.585 101.52 63.855 ;
     RECT  2.16 64.125 101.52 64.395 ;
     RECT  2.16 64.665 101.52 64.935 ;
     RECT  2.16 65.205 101.52 65.475 ;
     RECT  2.16 65.745 101.52 66.015 ;
     RECT  2.16 66.285 101.52 66.555 ;
     RECT  2.16 66.825 101.52 67.095 ;
     RECT  2.16 67.365 101.52 67.635 ;
     RECT  2.16 67.905 101.52 68.175 ;
     RECT  2.16 68.445 101.52 68.715 ;
     RECT  2.16 68.985 101.52 69.255 ;
     RECT  2.16 69.525 101.52 69.795 ;
     RECT  2.16 70.065 101.52 70.335 ;
     RECT  2.16 70.605 101.52 70.875 ;
     RECT  2.16 71.145 101.52 71.415 ;
     RECT  2.16 71.685 101.52 71.955 ;
     RECT  2.16 72.225 101.52 72.495 ;
     RECT  2.16 72.765 101.52 73.035 ;
     RECT  2.16 73.305 101.52 73.575 ;
     RECT  2.16 73.845 101.52 74.115 ;
     RECT  2.16 74.385 101.52 74.655 ;
     RECT  2.16 74.925 101.52 75.195 ;
     RECT  2.16 75.465 101.52 75.735 ;
     RECT  2.16 76.005 101.52 76.275 ;
     RECT  2.16 76.545 101.52 76.815 ;
     RECT  2.16 77.085 101.52 77.355 ;
     RECT  2.16 77.625 101.52 77.895 ;
     RECT  2.16 78.165 101.52 78.435 ;
     RECT  2.16 78.705 101.52 78.975 ;
     RECT  2.16 79.245 101.52 79.515 ;
     RECT  2.16 79.785 101.52 80.055 ;
     RECT  2.16 80.325 101.52 80.595 ;
     RECT  2.16 80.865 101.52 81.135 ;
     RECT  2.16 81.405 101.52 81.675 ;
     RECT  2.16 81.945 101.52 82.215 ;
     RECT  2.16 82.485 101.52 82.755 ;
     RECT  2.16 83.025 101.52 83.295 ;
     RECT  2.16 83.565 101.52 83.835 ;
     RECT  2.16 84.105 101.52 84.375 ;
     RECT  2.16 84.645 101.52 84.915 ;
     RECT  2.16 85.185 101.52 85.455 ;
     RECT  2.16 85.725 101.52 85.995 ;
     RECT  2.16 86.265 101.52 86.535 ;
     RECT  2.16 86.805 101.52 87.075 ;
     RECT  2.16 87.345 101.52 87.615 ;
     RECT  2.16 87.885 101.52 88.155 ;
     RECT  2.16 88.425 101.52 88.695 ;
     RECT  2.16 88.965 101.52 89.235 ;
     RECT  2.16 89.505 101.52 89.775 ;
     RECT  2.16 90.045 101.52 90.315 ;
     RECT  2.16 90.585 101.52 90.855 ;
     RECT  2.16 91.125 101.52 91.395 ;
     RECT  2.16 91.665 101.52 91.935 ;
     RECT  2.16 92.205 101.52 92.475 ;
     RECT  2.16 92.745 101.52 93.015 ;
     RECT  2.16 93.285 101.52 93.555 ;
     RECT  2.16 93.825 101.52 94.095 ;
     RECT  2.16 94.365 101.52 94.635 ;
     RECT  2.16 94.905 101.52 95.175 ;
     RECT  2.16 95.445 101.52 95.715 ;
     RECT  2.16 95.985 101.52 96.255 ;
     RECT  2.16 96.525 101.52 96.795 ;
     RECT  2.16 97.065 101.52 97.335 ;
     RECT  2.16 97.605 101.52 97.875 ;
     RECT  2.16 98.145 101.52 98.415 ;
     RECT  2.16 98.685 101.52 98.955 ;
     RECT  2.16 99.225 101.52 99.495 ;
     RECT  2.16 99.765 101.52 100.035 ;
     RECT  2.16 100.305 101.52 100.575 ;
     RECT  2.16 100.845 101.52 101.115 ;
     RECT  2.16 101.385 101.52 101.655 ;
     RECT  2.16 101.925 101.52 102.195 ;
     RECT  2.16 102.465 101.52 102.735 ;
     RECT  2.16 103.005 101.52 103.275 ;
     RECT  2.16 103.545 101.52 103.815 ;
     RECT  2.16 104.085 101.52 104.355 ;
     RECT  2.16 104.625 101.52 104.895 ;
     RECT  2.16 105.165 101.52 105.435 ;
     RECT  2.16 105.705 101.52 105.975 ;
     RECT  2.16 106.245 101.52 106.515 ;
     RECT  2.16 106.785 101.52 107.055 ;
     RECT  2.16 107.325 101.52 107.595 ;
     RECT  2.16 107.865 101.52 108.135 ;
     RECT  2.16 108.405 101.52 108.675 ;
     RECT  2.16 108.945 101.52 109.215 ;
     RECT  2.16 109.485 101.52 109.755 ;
     RECT  2.16 110.025 101.52 110.295 ;
     RECT  2.16 110.565 101.52 110.835 ;
     RECT  2.16 111.105 101.52 111.375 ;
     RECT  2.16 111.645 101.52 111.915 ;
     RECT  2.16 112.185 101.52 112.455 ;
     RECT  2.16 112.725 101.52 112.995 ;
     RECT  2.16 113.265 101.52 113.535 ;
     RECT  2.16 113.805 101.52 114.075 ;
     RECT  2.16 114.345 101.52 114.615 ;
     RECT  2.16 114.885 101.52 115.155 ;
     RECT  2.16 115.425 101.52 115.695 ;
     RECT  2.16 115.965 101.52 116.235 ;
     RECT  2.16 116.505 101.52 116.775 ;
     RECT  2.16 117.045 101.52 117.315 ;
     RECT  2.16 117.585 101.52 117.855 ;
     RECT  2.16 118.125 101.52 118.395 ;
     RECT  2.16 118.665 101.52 118.935 ;
     RECT  2.16 119.205 101.52 119.475 ;
     RECT  2.16 119.745 101.52 120.015 ;
     RECT  2.16 120.285 101.52 120.555 ;
     RECT  2.16 120.825 101.52 121.095 ;
     RECT  2.16 121.365 101.52 121.635 ;
     RECT  2.16 121.905 101.52 122.175 ;
     RECT  2.16 122.445 101.52 122.715 ;
     RECT  2.16 122.985 101.52 123.255 ;
     RECT  2.16 123.525 101.52 123.795 ;
     RECT  2.16 124.065 101.52 124.335 ;
     RECT  2.16 124.605 101.52 124.875 ;
     RECT  2.16 125.145 101.52 125.415 ;
     RECT  2.16 125.685 101.52 125.955 ;
     RECT  2.16 126.225 101.52 126.495 ;
     RECT  2.16 126.765 101.52 127.035 ;
     RECT  2.16 127.305 101.52 127.44 ;
    LAYER RVTP ;
     RECT  2.16 2.295 101.52 2.565 ;
     RECT  2.16 2.835 101.52 3.105 ;
     RECT  2.16 3.375 101.52 3.645 ;
     RECT  2.16 3.915 101.52 4.185 ;
     RECT  2.16 4.455 101.52 4.725 ;
     RECT  2.16 4.995 101.52 5.265 ;
     RECT  2.16 5.535 101.52 5.805 ;
     RECT  2.16 6.075 101.52 6.345 ;
     RECT  2.16 6.615 101.52 6.885 ;
     RECT  2.16 7.155 101.52 7.425 ;
     RECT  2.16 7.695 101.52 7.965 ;
     RECT  2.16 8.235 101.52 8.505 ;
     RECT  2.16 8.775 101.52 9.045 ;
     RECT  2.16 9.315 101.52 9.585 ;
     RECT  2.16 9.855 101.52 10.125 ;
     RECT  2.16 10.395 101.52 10.665 ;
     RECT  2.16 10.935 101.52 11.205 ;
     RECT  2.16 11.475 101.52 11.745 ;
     RECT  2.16 12.015 101.52 12.285 ;
     RECT  2.16 12.555 101.52 12.825 ;
     RECT  2.16 13.095 101.52 13.365 ;
     RECT  2.16 13.635 101.52 13.905 ;
     RECT  2.16 14.175 101.52 14.445 ;
     RECT  2.16 14.715 101.52 14.985 ;
     RECT  2.16 15.255 101.52 15.525 ;
     RECT  2.16 15.795 101.52 16.065 ;
     RECT  2.16 16.335 101.52 16.605 ;
     RECT  2.16 16.875 101.52 17.145 ;
     RECT  2.16 17.415 101.52 17.685 ;
     RECT  2.16 17.955 101.52 18.225 ;
     RECT  2.16 18.495 101.52 18.765 ;
     RECT  2.16 19.035 101.52 19.305 ;
     RECT  2.16 19.575 101.52 19.845 ;
     RECT  2.16 20.115 101.52 20.385 ;
     RECT  2.16 20.655 101.52 20.925 ;
     RECT  2.16 21.195 101.52 21.465 ;
     RECT  2.16 21.735 101.52 22.005 ;
     RECT  2.16 22.275 101.52 22.545 ;
     RECT  2.16 22.815 101.52 23.085 ;
     RECT  2.16 23.355 101.52 23.625 ;
     RECT  2.16 23.895 101.52 24.165 ;
     RECT  2.16 24.435 101.52 24.705 ;
     RECT  2.16 24.975 101.52 25.245 ;
     RECT  2.16 25.515 101.52 25.785 ;
     RECT  2.16 26.055 101.52 26.325 ;
     RECT  2.16 26.595 101.52 26.865 ;
     RECT  2.16 27.135 101.52 27.405 ;
     RECT  2.16 27.675 101.52 27.945 ;
     RECT  2.16 28.215 101.52 28.485 ;
     RECT  2.16 28.755 101.52 29.025 ;
     RECT  2.16 29.295 101.52 29.565 ;
     RECT  2.16 29.835 101.52 30.105 ;
     RECT  2.16 30.375 101.52 30.645 ;
     RECT  2.16 30.915 101.52 31.185 ;
     RECT  2.16 31.455 101.52 31.725 ;
     RECT  2.16 31.995 101.52 32.265 ;
     RECT  2.16 32.535 101.52 32.805 ;
     RECT  2.16 33.075 101.52 33.345 ;
     RECT  2.16 33.615 101.52 33.885 ;
     RECT  2.16 34.155 101.52 34.425 ;
     RECT  2.16 34.695 101.52 34.965 ;
     RECT  2.16 35.235 101.52 35.505 ;
     RECT  2.16 35.775 101.52 36.045 ;
     RECT  2.16 36.315 101.52 36.585 ;
     RECT  2.16 36.855 101.52 37.125 ;
     RECT  2.16 37.395 101.52 37.665 ;
     RECT  2.16 37.935 101.52 38.205 ;
     RECT  2.16 38.475 101.52 38.745 ;
     RECT  2.16 39.015 101.52 39.285 ;
     RECT  2.16 39.555 101.52 39.825 ;
     RECT  2.16 40.095 101.52 40.365 ;
     RECT  2.16 40.635 101.52 40.905 ;
     RECT  2.16 41.175 101.52 41.445 ;
     RECT  2.16 41.715 101.52 41.985 ;
     RECT  2.16 42.255 101.52 42.525 ;
     RECT  2.16 42.795 101.52 43.065 ;
     RECT  2.16 43.335 101.52 43.605 ;
     RECT  2.16 43.875 101.52 44.145 ;
     RECT  2.16 44.415 101.52 44.685 ;
     RECT  2.16 44.955 101.52 45.225 ;
     RECT  2.16 45.495 101.52 45.765 ;
     RECT  2.16 46.035 101.52 46.305 ;
     RECT  2.16 46.575 101.52 46.845 ;
     RECT  2.16 47.115 101.52 47.385 ;
     RECT  2.16 47.655 101.52 47.925 ;
     RECT  2.16 48.195 101.52 48.465 ;
     RECT  2.16 48.735 101.52 49.005 ;
     RECT  2.16 49.275 101.52 49.545 ;
     RECT  2.16 49.815 101.52 50.085 ;
     RECT  2.16 50.355 101.52 50.625 ;
     RECT  2.16 50.895 101.52 51.165 ;
     RECT  2.16 51.435 101.52 51.705 ;
     RECT  2.16 51.975 101.52 52.245 ;
     RECT  2.16 52.515 101.52 52.785 ;
     RECT  2.16 53.055 101.52 53.325 ;
     RECT  2.16 53.595 101.52 53.865 ;
     RECT  2.16 54.135 101.52 54.405 ;
     RECT  2.16 54.675 101.52 54.945 ;
     RECT  2.16 55.215 101.52 55.485 ;
     RECT  2.16 55.755 101.52 56.025 ;
     RECT  2.16 56.295 101.52 56.565 ;
     RECT  2.16 56.835 101.52 57.105 ;
     RECT  2.16 57.375 101.52 57.645 ;
     RECT  2.16 57.915 101.52 58.185 ;
     RECT  2.16 58.455 101.52 58.725 ;
     RECT  2.16 58.995 101.52 59.265 ;
     RECT  2.16 59.535 101.52 59.805 ;
     RECT  2.16 60.075 101.52 60.345 ;
     RECT  2.16 60.615 101.52 60.885 ;
     RECT  2.16 61.155 101.52 61.425 ;
     RECT  2.16 61.695 101.52 61.965 ;
     RECT  2.16 62.235 101.52 62.505 ;
     RECT  2.16 62.775 101.52 63.045 ;
     RECT  2.16 63.315 101.52 63.585 ;
     RECT  2.16 63.855 101.52 64.125 ;
     RECT  2.16 64.395 101.52 64.665 ;
     RECT  2.16 64.935 101.52 65.205 ;
     RECT  2.16 65.475 101.52 65.745 ;
     RECT  2.16 66.015 101.52 66.285 ;
     RECT  2.16 66.555 101.52 66.825 ;
     RECT  2.16 67.095 101.52 67.365 ;
     RECT  2.16 67.635 101.52 67.905 ;
     RECT  2.16 68.175 101.52 68.445 ;
     RECT  2.16 68.715 101.52 68.985 ;
     RECT  2.16 69.255 101.52 69.525 ;
     RECT  2.16 69.795 101.52 70.065 ;
     RECT  2.16 70.335 101.52 70.605 ;
     RECT  2.16 70.875 101.52 71.145 ;
     RECT  2.16 71.415 101.52 71.685 ;
     RECT  2.16 71.955 101.52 72.225 ;
     RECT  2.16 72.495 101.52 72.765 ;
     RECT  2.16 73.035 101.52 73.305 ;
     RECT  2.16 73.575 101.52 73.845 ;
     RECT  2.16 74.115 101.52 74.385 ;
     RECT  2.16 74.655 101.52 74.925 ;
     RECT  2.16 75.195 101.52 75.465 ;
     RECT  2.16 75.735 101.52 76.005 ;
     RECT  2.16 76.275 101.52 76.545 ;
     RECT  2.16 76.815 101.52 77.085 ;
     RECT  2.16 77.355 101.52 77.625 ;
     RECT  2.16 77.895 101.52 78.165 ;
     RECT  2.16 78.435 101.52 78.705 ;
     RECT  2.16 78.975 101.52 79.245 ;
     RECT  2.16 79.515 101.52 79.785 ;
     RECT  2.16 80.055 101.52 80.325 ;
     RECT  2.16 80.595 101.52 80.865 ;
     RECT  2.16 81.135 101.52 81.405 ;
     RECT  2.16 81.675 101.52 81.945 ;
     RECT  2.16 82.215 101.52 82.485 ;
     RECT  2.16 82.755 101.52 83.025 ;
     RECT  2.16 83.295 101.52 83.565 ;
     RECT  2.16 83.835 101.52 84.105 ;
     RECT  2.16 84.375 101.52 84.645 ;
     RECT  2.16 84.915 101.52 85.185 ;
     RECT  2.16 85.455 101.52 85.725 ;
     RECT  2.16 85.995 101.52 86.265 ;
     RECT  2.16 86.535 101.52 86.805 ;
     RECT  2.16 87.075 101.52 87.345 ;
     RECT  2.16 87.615 101.52 87.885 ;
     RECT  2.16 88.155 101.52 88.425 ;
     RECT  2.16 88.695 101.52 88.965 ;
     RECT  2.16 89.235 101.52 89.505 ;
     RECT  2.16 89.775 101.52 90.045 ;
     RECT  2.16 90.315 101.52 90.585 ;
     RECT  2.16 90.855 101.52 91.125 ;
     RECT  2.16 91.395 101.52 91.665 ;
     RECT  2.16 91.935 101.52 92.205 ;
     RECT  2.16 92.475 101.52 92.745 ;
     RECT  2.16 93.015 101.52 93.285 ;
     RECT  2.16 93.555 101.52 93.825 ;
     RECT  2.16 94.095 101.52 94.365 ;
     RECT  2.16 94.635 101.52 94.905 ;
     RECT  2.16 95.175 101.52 95.445 ;
     RECT  2.16 95.715 101.52 95.985 ;
     RECT  2.16 96.255 101.52 96.525 ;
     RECT  2.16 96.795 101.52 97.065 ;
     RECT  2.16 97.335 101.52 97.605 ;
     RECT  2.16 97.875 101.52 98.145 ;
     RECT  2.16 98.415 101.52 98.685 ;
     RECT  2.16 98.955 101.52 99.225 ;
     RECT  2.16 99.495 101.52 99.765 ;
     RECT  2.16 100.035 101.52 100.305 ;
     RECT  2.16 100.575 101.52 100.845 ;
     RECT  2.16 101.115 101.52 101.385 ;
     RECT  2.16 101.655 101.52 101.925 ;
     RECT  2.16 102.195 101.52 102.465 ;
     RECT  2.16 102.735 101.52 103.005 ;
     RECT  2.16 103.275 101.52 103.545 ;
     RECT  2.16 103.815 101.52 104.085 ;
     RECT  2.16 104.355 101.52 104.625 ;
     RECT  2.16 104.895 101.52 105.165 ;
     RECT  2.16 105.435 101.52 105.705 ;
     RECT  2.16 105.975 101.52 106.245 ;
     RECT  2.16 106.515 101.52 106.785 ;
     RECT  2.16 107.055 101.52 107.325 ;
     RECT  2.16 107.595 101.52 107.865 ;
     RECT  2.16 108.135 101.52 108.405 ;
     RECT  2.16 108.675 101.52 108.945 ;
     RECT  2.16 109.215 101.52 109.485 ;
     RECT  2.16 109.755 101.52 110.025 ;
     RECT  2.16 110.295 101.52 110.565 ;
     RECT  2.16 110.835 101.52 111.105 ;
     RECT  2.16 111.375 101.52 111.645 ;
     RECT  2.16 111.915 101.52 112.185 ;
     RECT  2.16 112.455 101.52 112.725 ;
     RECT  2.16 112.995 101.52 113.265 ;
     RECT  2.16 113.535 101.52 113.805 ;
     RECT  2.16 114.075 101.52 114.345 ;
     RECT  2.16 114.615 101.52 114.885 ;
     RECT  2.16 115.155 101.52 115.425 ;
     RECT  2.16 115.695 101.52 115.965 ;
     RECT  2.16 116.235 101.52 116.505 ;
     RECT  2.16 116.775 101.52 117.045 ;
     RECT  2.16 117.315 101.52 117.585 ;
     RECT  2.16 117.855 101.52 118.125 ;
     RECT  2.16 118.395 101.52 118.665 ;
     RECT  2.16 118.935 101.52 119.205 ;
     RECT  2.16 119.475 101.52 119.745 ;
     RECT  2.16 120.015 101.52 120.285 ;
     RECT  2.16 120.555 101.52 120.825 ;
     RECT  2.16 121.095 101.52 121.365 ;
     RECT  2.16 121.635 101.52 121.905 ;
     RECT  2.16 122.175 101.52 122.445 ;
     RECT  2.16 122.715 101.52 122.985 ;
     RECT  2.16 123.255 101.52 123.525 ;
     RECT  2.16 123.795 101.52 124.065 ;
     RECT  2.16 124.335 101.52 124.605 ;
     RECT  2.16 124.875 101.52 125.145 ;
     RECT  2.16 125.415 101.52 125.685 ;
     RECT  2.16 125.955 101.52 126.225 ;
     RECT  2.16 126.495 101.52 126.765 ;
     RECT  2.16 127.035 101.52 127.305 ;
    LAYER M1 ;
     RECT  2.16 2.151 101.52 127.449 ;
    LAYER M2 ;
     RECT  0.067 61.092 0.103 61.11 ;
     RECT  0.031 64.872 0.103 64.89 ;
     RECT  0.031 67.302 0.103 67.32 ;
     RECT  0.031 89.712 0.103 89.73 ;
     RECT  0.031 70.776 0.131 70.866 ;
     RECT  0.031 74.592 0.131 74.682 ;
     RECT  0.031 78.021 0.131 78.696 ;
     RECT  0.031 81.612 0.131 81.63 ;
     RECT  0.031 90.594 0.131 90.729 ;
     RECT  0.031 91.944 0.131 92.034 ;
     RECT  0.103 66.87 0.139 67.32 ;
     RECT  0.131 70.776 0.139 70.794 ;
     RECT  0.131 78.561 0.139 78.696 ;
     RECT  0.131 90.594 0.139 90.648 ;
     RECT  0.067 98.658 0.139 98.676 ;
     RECT  0.139 70.686 0.167 70.794 ;
     RECT  0.103 53.946 0.175 53.964 ;
     RECT  0.103 54.801 0.175 54.819 ;
     RECT  0.103 64.674 0.175 64.89 ;
     RECT  0.103 50.751 0.203 50.769 ;
     RECT  0.175 53.946 0.203 54.819 ;
     RECT  0.103 62.442 0.203 62.694 ;
     RECT  0.139 98.658 0.239 99.18 ;
     RECT  0.175 46.746 0.275 46.764 ;
     RECT  0.203 54.684 0.275 54.819 ;
     RECT  0.103 58.662 0.283 58.68 ;
     RECT  0.283 58.464 0.319 58.68 ;
     RECT  0.275 54.72 0.347 54.819 ;
     RECT  0.067 63.522 0.391 63.54 ;
     RECT  0.175 64.674 0.391 65.268 ;
     RECT  0.139 83.07 0.391 83.088 ;
     RECT  0.139 69.876 0.427 69.894 ;
     RECT  0.167 70.686 0.427 70.704 ;
     RECT  0.319 58.464 0.455 58.752 ;
     RECT  0.139 78.561 0.455 78.732 ;
     RECT  0.427 86.544 0.463 86.634 ;
     RECT  0.427 69.876 0.491 70.704 ;
     RECT  0.391 71.541 0.491 71.559 ;
     RECT  0.455 78.561 0.491 78.696 ;
     RECT  0.391 82.656 0.491 83.088 ;
     RECT  0.139 90.486 0.491 90.648 ;
     RECT  0.131 92.016 0.491 92.034 ;
     RECT  0.491 78.678 0.527 78.696 ;
     RECT  0.103 60.822 0.535 61.65 ;
     RECT  0.203 62.442 0.535 62.46 ;
     RECT  0.103 76.482 0.535 76.5 ;
     RECT  0.463 86.544 0.535 86.868 ;
     RECT  0.103 89.478 0.535 89.73 ;
     RECT  0.535 86.544 0.563 86.904 ;
     RECT  0.247 56.232 0.679 56.25 ;
     RECT  0.247 45.036 0.743 45.054 ;
     RECT  0.679 54.882 0.751 56.25 ;
     RECT  0.535 60.822 0.751 62.46 ;
     RECT  0.455 58.464 0.787 58.68 ;
     RECT  0.751 54.882 0.823 56.79 ;
     RECT  0.787 58.122 0.823 58.68 ;
     RECT  0.239 99.162 0.851 99.18 ;
     RECT  0.535 76.05 0.859 76.5 ;
     RECT  0.715 52.83 0.895 52.848 ;
     RECT  0.823 104.67 0.895 104.688 ;
     RECT  0.139 66.141 0.931 67.32 ;
     RECT  0.931 73.35 0.967 73.368 ;
     RECT  0.355 29.07 0.995 29.088 ;
     RECT  0.751 60.66 1.003 62.46 ;
     RECT  0.391 63.522 1.003 65.268 ;
     RECT  0.967 73.35 1.003 73.836 ;
     RECT  0.895 104.67 1.003 104.886 ;
     RECT  0.283 35.901 1.031 35.919 ;
     RECT  1.003 72.936 1.039 73.836 ;
     RECT  0.859 75.708 1.111 76.5 ;
     RECT  0.787 59.544 1.147 59.562 ;
     RECT  1.003 60.66 1.147 65.268 ;
     RECT  1.039 72.936 1.147 73.908 ;
     RECT  1.111 46.854 1.363 46.872 ;
     RECT  1.147 72.54 1.435 73.908 ;
     RECT  1.399 79.452 1.471 79.47 ;
     RECT  1.435 72.54 1.507 74.34 ;
     RECT  0.211 51.21 1.543 51.768 ;
     RECT  0.895 52.83 1.543 53.424 ;
     RECT  0.931 66.06 1.579 67.32 ;
     RECT  1.507 72.27 1.615 74.34 ;
     RECT  1.363 46.854 1.651 47.178 ;
     RECT  0.715 48.402 1.651 48.42 ;
     RECT  0.491 69.876 1.651 70.398 ;
     RECT  1.471 79.146 1.651 79.47 ;
     RECT  1.543 52.758 1.831 53.424 ;
     RECT  1.039 46.08 1.867 46.098 ;
     RECT  1.651 46.854 1.867 48.42 ;
     RECT  0.895 68.922 1.867 68.94 ;
     RECT  1.471 81.072 1.975 81.09 ;
     RECT  0.491 83.07 1.975 83.088 ;
     RECT  1.111 75.204 2.011 76.5 ;
     RECT  1.075 77.4 2.011 77.418 ;
     RECT  1.975 81.072 2.047 81.63 ;
     RECT  1.975 82.53 2.047 83.088 ;
     RECT  1.651 79.146 2.083 79.74 ;
     RECT  0.139 85.77 2.083 85.788 ;
     RECT  2.083 79.146 2.119 80.28 ;
     RECT  1.939 32.742 2.16 32.76 ;
     RECT  0.319 34.2 2.16 34.218 ;
     RECT  0.931 37.062 2.16 37.08 ;
     RECT  1.939 40.032 2.16 40.05 ;
     RECT  0.931 43.146 2.16 43.164 ;
     RECT  1.075 44.19 2.16 44.208 ;
     RECT  1.867 46.08 2.16 48.42 ;
     RECT  1.327 50.13 2.16 50.148 ;
     RECT  1.543 51.102 2.16 51.768 ;
     RECT  1.831 52.758 2.16 53.964 ;
     RECT  0.823 54.882 2.16 58.68 ;
     RECT  1.147 59.544 2.16 59.76 ;
     RECT  1.147 60.552 2.16 65.268 ;
     RECT  1.579 66.06 2.16 67.428 ;
     RECT  1.867 68.76 2.16 68.94 ;
     RECT  1.651 69.876 2.16 70.56 ;
     RECT  1.615 71.73 2.16 74.34 ;
     RECT  2.011 75.132 2.16 77.418 ;
     RECT  2.119 78.642 2.16 80.28 ;
     RECT  2.047 81.072 2.16 83.088 ;
     RECT  1.903 84.888 2.16 84.906 ;
     RECT  2.083 85.77 2.16 85.914 ;
     RECT  0.563 86.85 2.16 86.904 ;
     RECT  0.535 89.478 2.16 90.036 ;
     RECT  2.047 91.17 2.16 91.188 ;
     RECT  1.543 92.25 2.16 92.268 ;
     RECT  2.083 94.986 2.16 95.004 ;
     RECT  1.903 96.57 2.16 96.588 ;
     RECT  1.003 104.13 2.16 104.886 ;
     RECT  2.011 109.26 2.16 109.278 ;
     RECT  0.535 111.042 2.16 111.06 ;
     RECT  2.16 2.151 101.52 127.449 ;
     RECT  101.52 42.696 102.011 48.924 ;
     RECT  101.52 52.146 102.011 53.244 ;
     RECT  101.52 58.356 102.011 62.694 ;
     RECT  101.52 64.836 102.011 73.494 ;
     RECT  101.52 40.266 102.047 40.464 ;
     RECT  102.011 42.696 102.047 47.574 ;
     RECT  102.011 58.356 102.047 60.876 ;
     RECT  102.011 61.866 102.047 62.694 ;
     RECT  102.011 64.836 102.047 67.014 ;
     RECT  101.52 74.286 102.047 75.654 ;
     RECT  101.52 91.026 102.047 92.394 ;
     RECT  101.52 93.186 102.047 93.312 ;
     RECT  102.047 40.266 102.083 40.392 ;
     RECT  101.52 41.256 102.551 41.904 ;
     RECT  102.047 42.966 102.551 44.064 ;
     RECT  102.047 44.856 102.551 46.224 ;
     RECT  101.52 54.036 102.551 56.214 ;
     RECT  102.011 67.806 102.551 73.494 ;
     RECT  101.52 84.276 102.551 85.644 ;
     RECT  101.52 88.056 102.551 90.27 ;
     RECT  101.52 36.666 102.587 37.998 ;
     RECT  101.52 38.916 102.587 39.474 ;
     RECT  102.083 40.266 102.587 40.284 ;
     RECT  102.551 41.346 102.587 41.904 ;
     RECT  102.551 43.506 102.587 44.064 ;
     RECT  102.551 44.856 102.587 45.324 ;
     RECT  102.551 46.206 102.587 46.224 ;
     RECT  102.047 47.016 102.587 47.574 ;
     RECT  102.011 48.366 102.587 48.924 ;
     RECT  101.52 49.716 102.587 51.354 ;
     RECT  102.011 52.146 102.587 52.434 ;
     RECT  102.011 53.226 102.587 53.244 ;
     RECT  102.551 54.036 102.587 54.054 ;
     RECT  102.551 54.846 102.587 56.214 ;
     RECT  101.52 57.006 102.587 57.564 ;
     RECT  102.047 58.356 102.587 58.374 ;
     RECT  102.047 59.166 102.587 60.876 ;
     RECT  102.047 61.866 102.587 61.884 ;
     RECT  102.047 62.676 102.587 62.694 ;
     RECT  101.52 63.486 102.587 64.044 ;
     RECT  102.047 64.836 102.587 66.204 ;
     RECT  102.047 66.996 102.587 67.014 ;
     RECT  102.551 67.806 102.587 70.794 ;
     RECT  102.551 71.586 102.587 72.684 ;
     RECT  102.551 73.476 102.587 73.494 ;
     RECT  102.047 74.286 102.587 74.844 ;
     RECT  102.047 75.636 102.587 75.654 ;
     RECT  101.52 76.446 102.587 77.004 ;
     RECT  101.52 77.796 102.587 81.198 ;
     RECT  101.52 82.116 102.587 83.484 ;
     RECT  102.551 84.276 102.587 84.294 ;
     RECT  102.551 85.086 102.587 85.644 ;
     RECT  101.52 86.436 102.587 87.264 ;
     RECT  102.551 88.056 102.587 88.074 ;
     RECT  102.551 88.866 102.587 90.27 ;
     RECT  102.047 91.026 102.587 91.584 ;
     RECT  102.047 92.376 102.587 92.394 ;
     RECT  102.047 93.186 102.587 93.204 ;
     RECT  102.587 37.026 102.623 37.044 ;
     RECT  102.587 60.246 102.623 60.264 ;
     RECT  102.587 68.886 102.623 68.904 ;
    LAYER M3 ;
     RECT  2.415 2.143 2.505 2.413 ;
     RECT  7.815 2.143 7.905 2.413 ;
     RECT  13.215 2.143 13.305 2.413 ;
     RECT  18.615 2.143 18.705 2.413 ;
     RECT  24.015 2.143 24.105 2.413 ;
     RECT  29.415 2.143 29.505 2.413 ;
     RECT  34.815 2.143 34.905 2.413 ;
     RECT  40.215 2.143 40.305 2.413 ;
     RECT  45.615 2.143 45.705 2.413 ;
     RECT  51.015 2.143 51.105 2.413 ;
     RECT  56.415 2.143 56.505 2.413 ;
     RECT  61.815 2.143 61.905 2.413 ;
     RECT  67.215 2.143 67.305 2.413 ;
     RECT  72.615 2.143 72.705 2.413 ;
     RECT  78.015 2.143 78.105 2.413 ;
     RECT  83.415 2.143 83.505 2.413 ;
     RECT  88.815 2.143 88.905 2.413 ;
     RECT  94.215 2.143 94.305 2.413 ;
     RECT  99.615 2.143 99.705 2.413 ;
     RECT  2.415 2.413 2.697 7.531 ;
     RECT  2.268 7.531 2.697 7.963 ;
     RECT  0.216 8.395 0.234 8.827 ;
     RECT  2.268 7.963 3.15 9.259 ;
     RECT  0.216 8.827 0.954 9.691 ;
     RECT  0.108 9.691 0.954 9.821 ;
     RECT  2.268 9.259 3.222 10.123 ;
     RECT  2.268 10.123 3.942 10.987 ;
     RECT  0.216 9.821 0.954 14.875 ;
     RECT  0.108 14.875 0.954 15.005 ;
     RECT  0.216 15.005 0.954 15.739 ;
     RECT  0.144 15.739 0.954 15.835 ;
     RECT  0.072 15.835 0.954 16.939 ;
     RECT  0.036 16.939 0.954 18.763 ;
     RECT  1.944 10.987 3.942 18.763 ;
     RECT  5.976 20.443 5.994 27.067 ;
     RECT  0.036 18.763 3.942 28.453 ;
     RECT  0.036 28.453 4.518 29.795 ;
     RECT  3.924 29.795 4.518 29.911 ;
     RECT  3.924 29.911 5.022 32.881 ;
     RECT  0.036 29.795 3.186 35.179 ;
     RECT  3.924 32.881 5.094 35.179 ;
     RECT  99.615 2.413 99.897 36.481 ;
     RECT  99.615 36.481 100.602 36.625 ;
     RECT  102.564 36.661 102.582 36.701 ;
     RECT  99.615 36.625 101.178 36.895 ;
     RECT  102.6 37.021 102.618 37.133 ;
     RECT  34.815 2.413 35.097 37.285 ;
     RECT  24.015 2.413 24.297 37.291 ;
     RECT  45.615 2.413 45.897 37.291 ;
     RECT  56.415 2.413 56.697 37.291 ;
     RECT  67.215 2.413 67.497 37.291 ;
     RECT  78.015 2.413 78.297 37.291 ;
     RECT  88.815 2.413 89.097 37.291 ;
     RECT  34.704 37.285 35.097 37.325 ;
     RECT  23.904 37.291 24.297 37.328 ;
     RECT  45.504 37.291 45.897 37.328 ;
     RECT  56.304 37.291 56.697 37.328 ;
     RECT  67.104 37.291 67.497 37.328 ;
     RECT  77.904 37.291 78.297 37.328 ;
     RECT  88.704 37.291 89.097 37.328 ;
     RECT  96.948 37.291 96.966 37.328 ;
     RECT  99 36.895 101.178 37.399 ;
     RECT  15.228 37.387 15.246 37.471 ;
     RECT  14.544 37.471 15.246 37.499 ;
     RECT  14.544 37.499 14.562 37.517 ;
     RECT  98.568 37.399 101.178 37.589 ;
     RECT  5.976 27.067 6.498 37.597 ;
     RECT  7.815 2.413 8.097 37.597 ;
     RECT  96.336 37.435 96.498 37.597 ;
     RECT  98.568 37.589 98.694 37.598 ;
     RECT  98.604 37.598 98.694 37.625 ;
     RECT  96.12 37.597 96.498 37.697 ;
     RECT  5.976 37.597 8.097 38.129 ;
     RECT  96.336 37.697 96.498 38.129 ;
     RECT  100.728 37.589 101.178 38.129 ;
     RECT  97.308 37.399 97.398 38.137 ;
     RECT  96.336 38.129 96.354 38.141 ;
     RECT  98.604 37.625 98.622 38.399 ;
     RECT  97.308 38.137 97.506 38.435 ;
     RECT  99.54 37.589 99.954 38.551 ;
     RECT  100.728 38.129 101.106 38.551 ;
     RECT  98.64 38.551 101.106 38.675 ;
     RECT  102.564 37.531 102.582 38.827 ;
     RECT  99.432 38.675 101.106 38.911 ;
     RECT  94.215 2.413 94.497 39.019 ;
     RECT  5.976 38.129 7.002 39.091 ;
     RECT  7.815 38.129 8.097 39.091 ;
     RECT  94.215 39.019 94.662 39.119 ;
     RECT  98.64 38.675 98.658 39.163 ;
     RECT  98.46 39.163 98.658 39.209 ;
     RECT  98.46 39.209 98.478 39.341 ;
     RECT  0.036 35.179 5.094 39.589 ;
     RECT  5.976 39.091 8.097 39.589 ;
     RECT  97.308 38.435 97.362 39.631 ;
     RECT  102.528 38.827 102.582 39.691 ;
     RECT  0.036 39.589 8.097 39.749 ;
     RECT  97.308 39.631 97.506 39.785 ;
     RECT  94.215 39.119 94.497 39.883 ;
     RECT  96.516 39.307 96.534 39.917 ;
     RECT  94.215 39.883 94.77 40.055 ;
     RECT  99.432 38.911 101.178 40.171 ;
     RECT  99.288 40.171 101.178 40.289 ;
     RECT  95.688 40.171 95.706 40.325 ;
     RECT  99.36 40.289 101.178 40.325 ;
     RECT  99.468 40.325 101.178 40.405 ;
     RECT  102.024 39.691 102.582 40.469 ;
     RECT  0.036 39.749 7.002 40.559 ;
     RECT  98.496 40.507 98.514 40.559 ;
     RECT  102.06 40.469 102.582 40.589 ;
     RECT  7.776 39.749 8.097 40.711 ;
     RECT  94.215 40.055 94.662 40.739 ;
     RECT  99.468 40.405 101.214 40.829 ;
     RECT  97.308 39.785 97.326 40.981 ;
     RECT  99.54 40.829 101.214 41.135 ;
     RECT  99.576 41.135 101.214 41.279 ;
     RECT  102.528 40.589 102.582 41.453 ;
     RECT  0.036 40.559 6.93 41.521 ;
     RECT  97.308 40.981 97.578 41.549 ;
     RECT  99.615 41.279 101.214 41.639 ;
     RECT  98.604 41.521 98.622 41.675 ;
     RECT  97.308 41.549 97.506 41.791 ;
     RECT  96.12 41.791 96.138 41.837 ;
     RECT  98.784 41.791 98.802 41.909 ;
     RECT  102.564 41.453 102.582 41.909 ;
     RECT  97.056 41.791 97.506 41.945 ;
     RECT  99.615 41.639 101.178 42.061 ;
     RECT  98.928 42.061 101.178 42.179 ;
     RECT  0.036 41.521 7.038 42.601 ;
     RECT  7.776 40.711 8.298 42.601 ;
     RECT  0.036 42.601 8.298 42.691 ;
     RECT  97.308 41.945 97.506 42.715 ;
     RECT  102.024 42.283 102.042 42.715 ;
     RECT  98.928 42.179 101.034 42.719 ;
     RECT  102.024 42.715 102.546 42.719 ;
     RECT  96.912 42.715 97.506 42.755 ;
     RECT  94.215 40.739 94.497 42.961 ;
     RECT  0.036 42.691 8.766 42.989 ;
     RECT  11.376 36.751 11.394 43.069 ;
     RECT  97.308 42.755 97.506 43.082 ;
     RECT  94.215 42.961 94.662 43.097 ;
     RECT  102.528 42.719 102.546 43.147 ;
     RECT  10.8 43.069 11.394 43.259 ;
     RECT  97.308 43.082 98.01 43.373 ;
     RECT  99.615 42.719 101.034 43.411 ;
     RECT  102.528 43.147 102.582 43.579 ;
     RECT  9.72 38.443 9.738 43.681 ;
     RECT  97.308 43.373 97.326 43.681 ;
     RECT  98.856 43.339 98.874 43.681 ;
     RECT  98.676 43.681 98.874 43.799 ;
     RECT  96.336 43.681 96.498 43.835 ;
     RECT  97.272 43.681 97.326 43.867 ;
     RECT  96.336 43.835 96.354 43.901 ;
     RECT  99.615 43.411 101.142 44.141 ;
     RECT  102.024 43.579 102.582 44.177 ;
     RECT  101.16 44.185 101.178 44.339 ;
     RECT  98.784 43.799 98.874 44.491 ;
     RECT  99.615 44.141 100.386 44.491 ;
     RECT  98.784 44.491 100.386 44.645 ;
     RECT  0.036 42.989 8.37 44.887 ;
     RECT  9.108 43.681 9.738 44.887 ;
     RECT  97.236 43.867 97.326 44.887 ;
     RECT  97.236 44.887 97.47 45.121 ;
     RECT  95.904 45.019 95.922 45.149 ;
     RECT  99.504 44.645 100.386 45.265 ;
     RECT  101.196 44.761 101.214 45.265 ;
     RECT  97.236 45.121 97.722 45.301 ;
     RECT  96.84 45.301 97.722 45.451 ;
     RECT  99.504 45.265 101.214 45.451 ;
     RECT  96.048 45.301 96.066 45.455 ;
     RECT  96.84 45.451 98.298 45.455 ;
     RECT  99.324 45.451 101.214 45.491 ;
     RECT  97.308 45.455 98.298 45.599 ;
     RECT  97.308 45.599 97.434 45.689 ;
     RECT  94.215 43.097 94.497 45.769 ;
     RECT  98.28 45.599 98.298 45.841 ;
     RECT  94.215 45.769 94.662 45.869 ;
     RECT  99.504 45.491 101.214 45.959 ;
     RECT  102.528 44.177 102.582 46.171 ;
     RECT  99.54 45.959 101.178 46.301 ;
     RECT  97.308 45.689 97.326 46.381 ;
     RECT  96.732 46.381 97.326 46.459 ;
     RECT  98.28 45.841 98.37 46.651 ;
     RECT  96.588 46.459 97.326 46.781 ;
     RECT  98.28 46.651 98.55 46.805 ;
     RECT  94.215 45.869 94.497 47.011 ;
     RECT  95.616 46.747 95.634 47.075 ;
     RECT  94.215 47.011 94.662 47.083 ;
     RECT  99.54 46.301 100.35 47.119 ;
     RECT  102.024 46.171 102.582 47.147 ;
     RECT  99.252 47.119 100.35 47.155 ;
     RECT  101.196 46.921 101.214 47.155 ;
     RECT  98.28 46.805 98.298 47.191 ;
     RECT  94.215 47.083 94.734 47.219 ;
     RECT  98.136 47.191 98.298 47.261 ;
     RECT  98.136 47.261 98.154 47.345 ;
     RECT  102.564 47.147 102.582 47.579 ;
     RECT  99.252 47.155 101.214 47.851 ;
     RECT  98.892 47.851 101.214 47.891 ;
     RECT  96.228 48.043 96.246 48.271 ;
     RECT  97.308 46.781 97.326 48.271 ;
     RECT  101.988 47.899 102.006 48.299 ;
     RECT  98.82 48.271 98.838 48.389 ;
     RECT  96.228 48.271 96.39 48.731 ;
     RECT  97.164 48.271 97.326 48.811 ;
     RECT  96.948 48.811 97.326 48.965 ;
     RECT  11.376 43.259 11.394 49.081 ;
     RECT  10.836 49.081 11.394 49.199 ;
     RECT  98.604 48.811 98.766 49.199 ;
     RECT  99.615 47.891 101.214 49.199 ;
     RECT  0.036 44.887 9.738 49.441 ;
     RECT  99.615 49.199 101.178 49.441 ;
     RECT  97.308 48.965 97.326 49.585 ;
     RECT  102.564 48.331 102.582 49.627 ;
     RECT  0.036 49.441 10.278 49.739 ;
     RECT  102.528 49.627 102.582 50.009 ;
     RECT  97.308 49.585 98.046 50.141 ;
     RECT  97.308 50.141 97.686 50.153 ;
     RECT  99.18 49.441 101.178 50.161 ;
     RECT  98.892 50.161 101.178 50.315 ;
     RECT  99.252 50.315 101.178 50.395 ;
     RECT  97.308 50.153 97.326 50.431 ;
     RECT  97.092 50.431 97.326 50.585 ;
     RECT  11.376 49.199 11.394 50.701 ;
     RECT  96.156 50.395 96.174 50.717 ;
     RECT  0.036 49.739 10.17 50.791 ;
     RECT  11.268 50.701 11.394 50.791 ;
     RECT  99.252 50.395 101.214 50.819 ;
     RECT  94.215 47.219 94.497 51.097 ;
     RECT  94.215 51.097 94.662 51.197 ;
     RECT  97.2 50.585 97.326 51.241 ;
     RECT  98.316 50.935 98.334 51.241 ;
     RECT  99.252 50.819 100.926 51.241 ;
     RECT  97.2 51.241 97.506 51.259 ;
     RECT  98.316 51.241 100.926 51.259 ;
     RECT  97.2 51.259 100.926 51.269 ;
     RECT  97.308 51.269 100.926 51.601 ;
     RECT  97.308 51.601 101.034 51.665 ;
     RECT  99.615 51.665 101.034 51.781 ;
     RECT  99.615 51.781 101.214 51.899 ;
     RECT  94.215 51.197 94.497 52.027 ;
     RECT  94.215 52.027 94.662 52.051 ;
     RECT  97.308 51.665 98.622 52.079 ;
     RECT  94.215 52.051 94.698 52.169 ;
     RECT  97.308 52.079 98.55 52.169 ;
     RECT  95.436 52.051 95.454 52.205 ;
     RECT  98.064 52.169 98.55 52.439 ;
     RECT  102.564 50.009 102.582 52.651 ;
     RECT  99.615 51.899 101.178 52.861 ;
     RECT  98.064 52.439 98.082 52.925 ;
     RECT  101.988 52.651 102.582 52.979 ;
     RECT  94.215 52.169 94.662 53.221 ;
     RECT  94.215 53.221 94.698 53.357 ;
     RECT  97.308 52.169 97.326 53.365 ;
     RECT  96.732 53.365 97.326 53.401 ;
     RECT  99 52.861 101.178 53.401 ;
     RECT  98.928 53.401 101.178 53.519 ;
     RECT  94.215 53.357 94.662 53.549 ;
     RECT  96.732 53.401 97.722 53.549 ;
     RECT  97.272 53.549 97.722 53.555 ;
     RECT  97.272 53.555 97.614 53.789 ;
     RECT  97.272 53.789 97.362 53.795 ;
     RECT  102.564 52.979 102.582 53.947 ;
     RECT  99.615 53.519 101.178 54.131 ;
     RECT  98.568 53.671 98.586 54.301 ;
     RECT  97.272 53.795 97.326 54.331 ;
     RECT  98.316 54.301 98.586 54.371 ;
     RECT  99.615 54.131 101.142 54.481 ;
     RECT  99.468 54.481 101.142 54.571 ;
     RECT  97.236 54.331 97.326 54.607 ;
     RECT  98.316 54.371 98.478 54.635 ;
     RECT  99.252 54.571 101.142 54.707 ;
     RECT  102.528 53.947 102.582 54.811 ;
     RECT  102.024 54.811 102.582 54.977 ;
     RECT  97.02 54.607 97.326 55.283 ;
     RECT  99.54 54.707 101.142 55.381 ;
     RECT  96.192 55.561 96.21 55.675 ;
     RECT  96.048 55.675 96.21 55.679 ;
     RECT  96.048 55.679 96.066 55.715 ;
     RECT  99.54 55.381 101.178 55.795 ;
     RECT  97.308 55.283 97.326 55.831 ;
     RECT  98.064 55.111 98.082 55.831 ;
     RECT  97.308 55.831 98.658 55.985 ;
     RECT  98.532 55.985 98.658 56.101 ;
     RECT  99.54 55.795 101.214 56.101 ;
     RECT  102.564 54.977 102.582 56.219 ;
     RECT  98.532 56.101 98.694 56.429 ;
     RECT  99.468 56.101 101.214 56.489 ;
     RECT  97.308 55.985 97.722 56.605 ;
     RECT  94.215 53.549 94.497 56.641 ;
     RECT  96.768 56.605 97.722 56.795 ;
     RECT  96.768 56.795 97.326 56.831 ;
     RECT  97.128 56.831 97.326 56.909 ;
     RECT  99.468 56.489 101.178 56.911 ;
     RECT  102.024 56.539 102.042 56.971 ;
     RECT  98.784 56.911 101.178 57.065 ;
     RECT  102.024 56.971 102.582 57.209 ;
     RECT  0.036 50.791 11.394 57.307 ;
     RECT  95.904 57.307 95.922 57.451 ;
     RECT  94.215 56.641 94.662 57.569 ;
     RECT  95.688 57.451 95.922 57.569 ;
     RECT  98.136 57.451 98.37 57.569 ;
     RECT  95.688 57.569 95.706 57.581 ;
     RECT  98.136 57.569 98.154 57.605 ;
     RECT  97.308 56.909 97.326 57.991 ;
     RECT  0.036 57.307 11.538 58.109 ;
     RECT  99.288 57.065 101.178 58.261 ;
     RECT  102.564 57.209 102.582 58.267 ;
     RECT  0.036 58.109 11.43 58.379 ;
     RECT  102.024 58.267 102.582 58.379 ;
     RECT  99.072 58.261 101.178 58.415 ;
     RECT  97.308 57.991 97.83 58.621 ;
     RECT  95.976 58.423 95.994 58.649 ;
     RECT  95.832 58.651 95.85 58.691 ;
     RECT  102.024 58.379 102.042 58.699 ;
     RECT  96.912 58.621 98.082 58.955 ;
     RECT  94.215 57.569 94.497 59.035 ;
     RECT  101.988 58.699 102.042 59.099 ;
     RECT  99.324 58.415 100.962 59.161 ;
     RECT  95.688 59.071 95.706 59.225 ;
     RECT  94.215 59.035 94.77 59.261 ;
     RECT  99.324 59.161 100.998 59.431 ;
     RECT  97.38 58.955 98.082 59.611 ;
     RECT  99.324 59.431 101.178 59.645 ;
     RECT  99.576 59.645 101.178 59.845 ;
     RECT  99.576 59.845 101.214 59.999 ;
     RECT  97.38 59.611 98.118 60.151 ;
     RECT  102.564 59.131 102.582 60.241 ;
     RECT  96.444 60.151 96.462 60.305 ;
     RECT  95.508 59.995 95.526 60.427 ;
     RECT  95.508 60.427 95.85 60.461 ;
     RECT  102.564 60.241 102.618 60.461 ;
     RECT  94.215 59.261 94.497 60.781 ;
     RECT  99.615 59.999 100.89 60.781 ;
     RECT  95.832 60.461 95.85 60.845 ;
     RECT  102.564 60.461 102.582 60.893 ;
     RECT  99.54 60.781 100.89 60.925 ;
     RECT  97.38 60.151 98.334 60.961 ;
     RECT  99.54 60.925 101.214 60.961 ;
     RECT  96.912 60.961 98.334 61.115 ;
     RECT  99.18 60.961 101.214 61.115 ;
     RECT  96.984 61.115 98.334 61.613 ;
     RECT  101.988 61.291 102.006 61.619 ;
     RECT  99.288 61.115 101.214 61.655 ;
     RECT  98.316 61.613 98.334 61.727 ;
     RECT  99.36 61.655 101.214 62.159 ;
     RECT  96.984 61.613 97.398 62.209 ;
     RECT  94.215 60.781 94.662 62.395 ;
     RECT  99.36 62.159 101.178 62.429 ;
     RECT  94.215 62.395 94.986 62.465 ;
     RECT  102.024 61.723 102.582 62.699 ;
     RECT  98.676 62.968 98.694 63.005 ;
     RECT  0.036 58.379 11.394 63.121 ;
     RECT  97.308 62.209 97.398 63.211 ;
     RECT  0.036 63.121 12.078 63.239 ;
     RECT  96.912 63.211 97.398 63.247 ;
     RECT  14.796 63.049 14.814 63.275 ;
     RECT  96.804 63.247 97.398 63.419 ;
     RECT  101.988 63.019 102.006 63.451 ;
     RECT  98.568 63.247 98.586 63.545 ;
     RECT  99.615 62.429 101.178 63.661 ;
     RECT  101.988 63.451 102.582 63.689 ;
     RECT  99.54 63.661 101.178 63.751 ;
     RECT  98.892 63.751 101.178 63.779 ;
     RECT  98.892 63.779 100.602 63.851 ;
     RECT  98.892 63.851 100.458 64.085 ;
     RECT  96.876 63.419 97.398 64.327 ;
     RECT  13.215 2.413 13.497 64.363 ;
     RECT  96.696 64.327 97.398 64.499 ;
     RECT  96.768 64.499 97.398 64.705 ;
     RECT  99 64.085 100.458 64.741 ;
     RECT  102.564 63.689 102.582 64.747 ;
     RECT  0.036 63.239 11.97 64.895 ;
     RECT  99 64.741 100.926 65.011 ;
     RECT  98.748 65.011 100.926 65.165 ;
     RECT  102.024 64.747 102.582 65.237 ;
     RECT  99.576 65.165 100.926 65.245 ;
     RECT  96.768 64.705 97.686 65.281 ;
     RECT  99.576 65.245 101.142 65.399 ;
     RECT  96.768 65.281 97.722 65.509 ;
     RECT  96.732 65.509 97.722 65.515 ;
     RECT  96.732 65.515 98.082 65.549 ;
     RECT  30.456 61.897 30.474 65.579 ;
     RECT  29.415 2.413 29.697 65.677 ;
     RECT  75.168 65.641 75.186 65.693 ;
     RECT  52.02 65.983 52.038 66.029 ;
     RECT  53.568 65.888 53.586 66.029 ;
     RECT  73.62 65.785 73.638 66.029 ;
     RECT  29.415 65.677 30.222 66.209 ;
     RECT  99.615 65.399 101.034 66.325 ;
     RECT  97.38 65.549 98.082 66.479 ;
     RECT  99.18 66.325 101.178 66.479 ;
     RECT  97.38 66.479 97.506 66.631 ;
     RECT  99.18 66.479 100.782 66.631 ;
     RECT  31.104 66.631 31.122 66.712 ;
     RECT  31.104 66.712 31.194 66.829 ;
     RECT  102.564 65.237 102.582 66.901 ;
     RECT  30.78 66.829 31.59 66.929 ;
     RECT  13.215 64.363 13.914 66.991 ;
     RECT  24.015 37.328 24.297 66.991 ;
     RECT  96.372 66.901 96.39 67.019 ;
     RECT  102.024 66.901 102.582 67.019 ;
     RECT  13.104 66.991 13.914 67.037 ;
     RECT  23.904 66.991 24.297 67.037 ;
     RECT  26.784 66.811 26.802 67.037 ;
     RECT  99 66.631 100.782 67.243 ;
     RECT  98.388 67.243 100.782 67.289 ;
     RECT  0.072 64.895 11.97 67.297 ;
     RECT  97.308 66.631 97.506 67.325 ;
     RECT  96.228 67.171 96.246 67.373 ;
     RECT  90.648 67.261 90.666 67.433 ;
     RECT  98.388 67.289 98.406 67.441 ;
     RECT  99.54 67.289 100.782 67.441 ;
     RECT  94.215 62.465 94.497 67.531 ;
     RECT  95.364 67.441 95.382 67.531 ;
     RECT  94.215 67.531 95.382 67.595 ;
     RECT  94.215 67.595 94.662 67.667 ;
     RECT  98.1 67.441 98.406 67.739 ;
     RECT  101.988 67.339 102.006 67.739 ;
     RECT  99.54 67.441 101.034 67.801 ;
     RECT  0.036 67.297 11.97 68.341 ;
     RECT  99.54 67.801 101.178 68.377 ;
     RECT  99.216 68.377 101.178 68.485 ;
     RECT  99.216 68.485 101.214 68.639 ;
     RECT  97.308 67.325 97.326 68.791 ;
     RECT  98.1 67.739 98.334 68.791 ;
     RECT  99.216 68.639 101.178 68.791 ;
     RECT  102.564 67.771 102.582 68.881 ;
     RECT  96.984 68.791 97.326 68.945 ;
     RECT  98.1 68.791 101.178 68.945 ;
     RECT  94.215 67.667 94.497 68.971 ;
     RECT  96.048 68.635 96.066 69.005 ;
     RECT  94.215 68.971 94.842 69.061 ;
     RECT  102.564 68.881 102.618 69.101 ;
     RECT  0.036 68.341 12.222 69.179 ;
     RECT  94.215 69.061 94.986 69.179 ;
     RECT  13.215 67.037 13.914 69.331 ;
     RECT  94.215 69.179 94.662 69.449 ;
     RECT  97.308 68.945 97.326 69.643 ;
     RECT  98.1 68.945 98.118 69.643 ;
     RECT  99.18 68.945 101.178 69.755 ;
     RECT  97.308 69.643 98.118 69.799 ;
     RECT  97.308 69.799 98.334 70.141 ;
     RECT  0.036 69.179 11.97 70.259 ;
     RECT  96.912 70.141 98.334 70.259 ;
     RECT  96.912 70.259 98.262 70.459 ;
     RECT  100.836 69.755 101.178 70.501 ;
     RECT  96.768 70.459 98.262 70.529 ;
     RECT  100.8 70.501 101.178 70.601 ;
     RECT  99.36 69.755 99.897 70.645 ;
     RECT  99.324 70.645 99.897 70.681 ;
     RECT  102.564 69.101 102.582 70.795 ;
     RECT  97.308 70.529 98.262 70.835 ;
     RECT  101.16 70.601 101.178 70.835 ;
     RECT  102.528 70.795 102.582 71.069 ;
     RECT  99.324 70.681 100.206 71.113 ;
     RECT  99.108 71.113 100.206 71.455 ;
     RECT  98.82 71.455 100.386 71.491 ;
     RECT  98.82 71.491 100.566 71.501 ;
     RECT  98.82 71.501 98.838 71.645 ;
     RECT  0.036 70.259 11.394 71.761 ;
     RECT  97.308 70.835 97.902 71.837 ;
     RECT  99.615 71.501 100.566 71.851 ;
     RECT  97.308 71.837 97.362 72.265 ;
     RECT  96.876 72.265 97.362 72.293 ;
     RECT  96.876 72.293 97.326 72.391 ;
     RECT  98.64 72.301 98.658 72.455 ;
     RECT  18.615 2.413 18.897 72.523 ;
     RECT  99.615 71.851 101.178 72.571 ;
     RECT  0.036 71.761 11.826 72.661 ;
     RECT  18.615 72.523 19.386 72.661 ;
     RECT  0.036 72.661 12.438 72.689 ;
     RECT  18.615 72.661 20.07 72.689 ;
     RECT  96.84 72.391 97.326 72.689 ;
     RECT  20.052 72.689 20.07 72.701 ;
     RECT  96.876 72.689 97.326 72.833 ;
     RECT  12.42 72.689 12.438 72.841 ;
     RECT  13.215 69.331 13.95 72.841 ;
     RECT  0.036 72.689 11.394 72.959 ;
     RECT  99.036 72.571 101.178 72.959 ;
     RECT  99.576 72.959 101.178 73.229 ;
     RECT  98.064 72.841 98.082 73.265 ;
     RECT  102.564 71.069 102.582 73.381 ;
     RECT  96.048 73.381 96.066 73.471 ;
     RECT  95.904 73.471 96.066 73.499 ;
     RECT  98.28 73.345 98.586 73.499 ;
     RECT  102.528 73.381 102.582 73.499 ;
     RECT  95.904 73.499 95.922 73.517 ;
     RECT  98.28 73.499 98.442 73.535 ;
     RECT  99.615 73.229 101.178 73.535 ;
     RECT  18.615 72.689 18.897 73.768 ;
     RECT  96.912 72.833 97.326 73.805 ;
     RECT  18.615 73.768 19.206 73.921 ;
     RECT  98.28 73.535 98.298 74.075 ;
     RECT  18.615 73.921 19.386 74.093 ;
     RECT  102.024 73.819 102.042 74.251 ;
     RECT  99.615 73.535 100.926 74.425 ;
     RECT  0.036 72.959 10.386 74.461 ;
     RECT  11.124 72.959 11.394 74.461 ;
     RECT  102.024 74.251 102.582 74.489 ;
     RECT  96.48 74.425 96.498 74.539 ;
     RECT  0.036 74.461 11.394 74.551 ;
     RECT  0.036 74.551 11.574 74.579 ;
     RECT  96.336 74.539 96.498 74.579 ;
     RECT  97.308 73.805 97.326 74.623 ;
     RECT  99.615 74.425 101.178 74.731 ;
     RECT  98.316 74.683 98.334 74.849 ;
     RECT  97.308 74.623 97.506 74.923 ;
     RECT  99.576 74.731 101.178 74.923 ;
     RECT  97.308 74.923 98.154 74.963 ;
     RECT  99.216 74.923 101.178 74.963 ;
     RECT  18.615 74.093 18.897 74.971 ;
     RECT  18.615 74.971 19.386 75.115 ;
     RECT  18.615 75.115 20.07 75.119 ;
     RECT  99.288 74.963 101.178 75.119 ;
     RECT  20.052 75.119 20.07 75.155 ;
     RECT  97.308 74.963 97.83 75.271 ;
     RECT  97.02 75.271 97.83 75.389 ;
     RECT  99.288 75.119 101.142 75.425 ;
     RECT  0.036 74.579 10.386 75.541 ;
     RECT  11.124 74.579 11.574 75.541 ;
     RECT  102.564 74.489 102.582 75.541 ;
     RECT  12.42 72.841 13.95 75.569 ;
     RECT  102.024 75.541 102.582 75.581 ;
     RECT  0.036 75.541 11.574 75.631 ;
     RECT  12.42 75.569 13.914 75.631 ;
     RECT  0.036 75.631 13.914 75.659 ;
     RECT  96.372 75.541 96.462 75.659 ;
     RECT  102.564 75.581 102.582 75.659 ;
     RECT  97.308 75.389 97.83 75.695 ;
     RECT  99.576 75.425 101.142 75.695 ;
     RECT  96.372 75.659 96.39 75.731 ;
     RECT  97.308 75.695 97.506 75.965 ;
     RECT  99.615 75.695 101.142 75.979 ;
     RECT  98.64 76.309 98.658 76.349 ;
     RECT  99.615 75.979 101.682 76.577 ;
     RECT  97.308 75.965 97.326 76.939 ;
     RECT  94.215 69.449 94.497 76.981 ;
     RECT  97.308 76.939 98.046 77.153 ;
     RECT  12.204 75.659 13.914 77.161 ;
     RECT  99.615 76.577 101.178 77.161 ;
     RECT  102.564 76.411 102.582 77.275 ;
     RECT  99 77.161 101.178 77.431 ;
     RECT  90.684 77.521 90.702 77.693 ;
     RECT  97.308 77.153 97.542 77.701 ;
     RECT  95.4 77.557 95.418 77.837 ;
     RECT  98.604 77.431 101.178 77.855 ;
     RECT  102.024 77.275 102.582 77.927 ;
     RECT  99.615 77.855 101.178 77.935 ;
     RECT  94.215 76.981 94.662 77.999 ;
     RECT  96.912 77.701 97.542 78.061 ;
     RECT  99.615 77.935 101.25 78.089 ;
     RECT  96.912 78.061 98.586 78.359 ;
     RECT  0.036 75.659 11.394 78.701 ;
     RECT  99.615 78.089 101.178 78.709 ;
     RECT  0.072 78.701 11.394 78.781 ;
     RECT  12.168 77.161 13.914 78.781 ;
     RECT  99.576 78.709 101.178 78.781 ;
     RECT  0.072 78.781 13.914 78.899 ;
     RECT  96.912 78.359 98.154 79.051 ;
     RECT  11.196 78.899 13.914 79.079 ;
     RECT  11.196 79.079 11.754 79.169 ;
     RECT  96.84 79.051 98.154 79.177 ;
     RECT  96.732 79.177 98.154 79.229 ;
     RECT  99.432 78.781 101.178 79.285 ;
     RECT  11.196 79.169 11.61 79.439 ;
     RECT  12.564 79.079 13.914 79.439 ;
     RECT  99.432 79.285 101.214 79.439 ;
     RECT  98.064 79.229 98.154 79.483 ;
     RECT  97.308 79.229 97.326 80.131 ;
     RECT  98.064 79.483 98.226 80.131 ;
     RECT  12.636 79.439 13.914 80.159 ;
     RECT  11.304 79.439 11.61 80.221 ;
     RECT  97.308 80.131 98.226 80.329 ;
     RECT  97.164 80.329 98.694 80.381 ;
     RECT  97.308 80.381 98.694 80.393 ;
     RECT  11.268 80.221 11.61 80.401 ;
     RECT  98.676 80.393 98.694 80.401 ;
     RECT  99.432 79.439 101.106 80.401 ;
     RECT  0.072 78.899 10.386 80.491 ;
     RECT  11.196 80.401 11.682 80.491 ;
     RECT  0.072 80.491 11.682 80.519 ;
     RECT  9.648 80.519 11.682 80.555 ;
     RECT  98.676 80.401 101.106 80.599 ;
     RECT  97.308 80.393 97.83 80.669 ;
     RECT  11.196 80.555 11.682 80.671 ;
     RECT  11.196 80.671 12.006 80.789 ;
     RECT  98.676 80.599 101.178 80.825 ;
     RECT  95.256 80.923 95.274 80.941 ;
     RECT  95.256 80.941 95.418 81.059 ;
     RECT  96.192 81.211 96.21 81.365 ;
     RECT  0.072 80.519 8.838 81.481 ;
     RECT  9.648 80.555 10.386 81.481 ;
     RECT  0.072 81.481 10.386 81.571 ;
     RECT  11.196 80.789 11.646 81.571 ;
     RECT  0.072 81.571 11.646 81.599 ;
     RECT  0.072 81.599 11.574 81.607 ;
     RECT  99.18 80.825 101.178 81.635 ;
     RECT  13.215 80.159 13.914 82.021 ;
     RECT  102.564 77.927 102.582 82.027 ;
     RECT  0.036 81.607 11.574 82.175 ;
     RECT  99.288 81.635 101.178 82.175 ;
     RECT  12.528 82.021 13.914 82.409 ;
     RECT  102.024 82.027 102.582 82.517 ;
     RECT  98.064 82.291 98.082 82.525 ;
     RECT  99.288 82.175 101.034 82.561 ;
     RECT  98.064 82.525 98.118 82.589 ;
     RECT  99.216 82.561 101.034 82.759 ;
     RECT  97.308 80.669 97.326 82.795 ;
     RECT  96.588 82.795 97.326 82.831 ;
     RECT  96.588 82.831 97.542 82.985 ;
     RECT  99.036 82.759 101.034 83.179 ;
     RECT  0.036 82.175 11.538 83.191 ;
     RECT  0.036 83.191 11.574 83.219 ;
     RECT  96.588 82.985 97.326 83.219 ;
     RECT  98.928 83.179 101.034 83.219 ;
     RECT  98.964 83.219 101.034 83.605 ;
     RECT  96.84 83.219 97.326 83.767 ;
     RECT  96.84 83.767 97.434 83.837 ;
     RECT  98.964 83.605 101.178 84.065 ;
     RECT  102.564 82.517 102.582 84.187 ;
     RECT  9.396 83.219 11.574 84.209 ;
     RECT  96.84 83.837 97.326 84.299 ;
     RECT  98.46 84.181 98.478 84.335 ;
     RECT  99.615 84.065 101.178 84.335 ;
     RECT  98.352 84.343 98.37 84.605 ;
     RECT  9.756 84.209 11.574 84.721 ;
     RECT  98.244 84.991 98.262 85.099 ;
     RECT  0.036 83.219 8.586 85.225 ;
     RECT  97.308 84.299 97.326 85.225 ;
     RECT  98.1 85.099 98.262 85.225 ;
     RECT  99.615 84.335 100.926 85.225 ;
     RECT  99.615 85.225 101.106 85.261 ;
     RECT  99.036 85.261 101.106 85.351 ;
     RECT  97.308 85.225 98.262 85.423 ;
     RECT  99.036 85.351 101.178 85.423 ;
     RECT  97.308 85.423 101.178 85.451 ;
     RECT  9.756 84.721 11.61 85.649 ;
     RECT  97.308 85.451 101.106 85.721 ;
     RECT  102.528 84.187 102.582 85.915 ;
     RECT  96.156 85.765 96.174 85.949 ;
     RECT  97.308 85.721 97.578 85.949 ;
     RECT  98.46 85.721 101.106 85.955 ;
     RECT  98.712 85.955 101.106 86.341 ;
     RECT  0.036 85.225 8.838 86.459 ;
     RECT  98.712 86.341 101.214 86.495 ;
     RECT  0.036 86.459 8.262 86.567 ;
     RECT  98.712 86.495 101.106 86.603 ;
     RECT  97.308 85.949 97.326 86.635 ;
     RECT  9.756 85.649 11.538 86.845 ;
     RECT  94.215 77.999 94.497 86.845 ;
     RECT  98.712 86.603 98.73 86.881 ;
     RECT  102.312 85.915 102.582 86.909 ;
     RECT  94.215 86.845 94.662 86.999 ;
     RECT  9.648 86.845 11.538 87.007 ;
     RECT  13.215 82.409 13.914 87.071 ;
     RECT  96.804 86.635 97.326 87.179 ;
     RECT  98.064 86.881 98.73 87.197 ;
     RECT  0.036 86.567 8.19 87.269 ;
     RECT  98.064 87.197 98.622 87.305 ;
     RECT  96.912 87.179 97.326 87.421 ;
     RECT  96.912 87.421 97.578 87.539 ;
     RECT  9.432 87.007 11.538 87.643 ;
     RECT  8.964 87.643 11.538 87.691 ;
     RECT  95.58 87.781 95.598 87.821 ;
     RECT  96.912 87.539 97.326 87.821 ;
     RECT  98.604 87.305 98.622 87.845 ;
     RECT  99.54 86.603 101.106 87.845 ;
     RECT  8.856 87.691 11.538 87.953 ;
     RECT  90.648 87.817 90.666 87.989 ;
     RECT  102.564 86.909 102.582 88.075 ;
     RECT  96.516 87.961 96.534 88.115 ;
     RECT  10.8 87.953 11.538 88.231 ;
     RECT  99.54 87.845 100.422 88.231 ;
     RECT  0.036 87.269 8.097 88.321 ;
     RECT  8.856 87.953 9.99 88.321 ;
     RECT  10.8 88.231 11.574 88.349 ;
     RECT  102.528 88.075 102.582 88.349 ;
     RECT  97.308 87.821 97.326 88.501 ;
     RECT  10.98 88.349 11.574 88.529 ;
     RECT  97.308 88.501 97.722 88.603 ;
     RECT  99.432 88.231 100.422 88.603 ;
     RECT  99.324 88.603 100.422 88.655 ;
     RECT  0.036 88.321 9.99 88.771 ;
     RECT  97.308 88.603 97.902 88.771 ;
     RECT  99.615 88.655 100.422 88.771 ;
     RECT  101.16 88.051 101.178 88.771 ;
     RECT  0.036 88.771 10.026 88.861 ;
     RECT  97.308 88.771 98.514 88.925 ;
     RECT  0.036 88.861 10.206 89.159 ;
     RECT  10.98 88.529 11.394 89.159 ;
     RECT  9.108 89.159 10.206 89.311 ;
     RECT  99.615 88.771 101.214 89.401 ;
     RECT  10.98 89.159 10.998 89.429 ;
     RECT  13.215 87.071 13.497 89.473 ;
     RECT  97.308 88.925 97.902 89.573 ;
     RECT  94.215 86.999 94.497 89.707 ;
     RECT  99.396 89.401 101.214 89.707 ;
     RECT  0.036 89.159 8.262 89.735 ;
     RECT  98.748 89.707 101.214 89.735 ;
     RECT  9.108 89.311 10.242 89.779 ;
     RECT  97.308 89.573 97.326 89.851 ;
     RECT  98.748 89.735 98.766 89.851 ;
     RECT  9.108 89.779 10.71 89.879 ;
     RECT  94.215 89.707 94.662 89.879 ;
     RECT  0.072 89.735 8.262 89.969 ;
     RECT  98.388 89.851 98.766 89.969 ;
     RECT  96.66 89.851 97.326 90.005 ;
     RECT  95.724 89.815 95.742 90.077 ;
     RECT  7.815 89.969 8.262 90.247 ;
     RECT  9.108 89.879 10.638 90.247 ;
     RECT  0.072 89.969 7.074 90.581 ;
     RECT  99.54 89.735 101.214 90.581 ;
     RECT  0.072 90.581 6.966 90.589 ;
     RECT  7.815 90.247 10.638 90.617 ;
     RECT  98.388 89.969 98.694 90.625 ;
     RECT  98.064 90.625 98.694 90.653 ;
     RECT  94.215 89.879 94.497 90.661 ;
     RECT  99.54 90.581 99.918 90.661 ;
     RECT  10.044 90.617 10.638 90.779 ;
     RECT  94.215 90.661 94.662 90.779 ;
     RECT  100.908 90.581 101.214 90.779 ;
     RECT  13.215 89.473 13.662 90.823 ;
     RECT  14.436 90.619 14.454 90.823 ;
     RECT  99.468 90.661 99.918 90.931 ;
     RECT  98.064 90.653 98.082 90.989 ;
     RECT  13.215 90.823 14.454 91.057 ;
     RECT  99 90.931 99.918 91.085 ;
     RECT  7.815 90.617 9.09 91.193 ;
     RECT  10.836 90.931 10.926 91.193 ;
     RECT  99.396 91.085 99.918 91.319 ;
     RECT  13.215 91.057 14.85 91.327 ;
     RECT  100.908 90.779 101.106 91.471 ;
     RECT  102.564 88.349 102.582 91.531 ;
     RECT  100.836 91.471 101.106 91.561 ;
     RECT  7.815 91.193 9.018 91.589 ;
     RECT  10.044 90.779 10.062 91.589 ;
     RECT  13.215 91.327 15.03 91.589 ;
     RECT  14.94 91.589 15.03 91.597 ;
     RECT  7.815 91.589 8.838 91.661 ;
     RECT  10.836 91.193 10.854 91.661 ;
     RECT  14.94 91.597 15.138 91.661 ;
     RECT  0.036 90.589 6.966 91.705 ;
     RECT  7.815 91.661 8.19 91.705 ;
     RECT  100.764 91.561 101.106 91.705 ;
     RECT  97.308 90.005 97.326 91.741 ;
     RECT  96.264 91.195 96.282 91.757 ;
     RECT  15.012 91.661 15.138 91.769 ;
     RECT  15.012 91.769 15.03 91.859 ;
     RECT  56.415 37.328 56.697 91.867 ;
     RECT  94.215 90.779 94.497 91.903 ;
     RECT  99.615 91.319 99.918 92.011 ;
     RECT  100.764 91.705 101.214 92.011 ;
     RECT  98.604 91.741 98.622 92.245 ;
     RECT  99.615 92.011 101.214 92.245 ;
     RECT  98.604 92.245 101.214 92.333 ;
     RECT  9.792 91.741 9.81 92.399 ;
     RECT  85.608 92.395 85.626 92.435 ;
     RECT  55.332 91.597 55.35 92.437 ;
     RECT  97.308 91.741 97.506 92.479 ;
     RECT  96.732 92.479 97.506 92.551 ;
     RECT  55.152 92.437 55.35 92.573 ;
     RECT  94.215 91.903 94.662 92.641 ;
     RECT  56.124 91.867 56.697 92.669 ;
     RECT  99.324 92.333 101.214 92.669 ;
     RECT  9.9 92.551 9.918 92.705 ;
     RECT  96.732 92.551 97.686 92.705 ;
     RECT  98.46 92.551 98.478 92.705 ;
     RECT  94.215 92.641 95.166 92.779 ;
     RECT  85.536 92.443 85.554 92.813 ;
     RECT  87.156 92.551 87.174 92.813 ;
     RECT  96.732 92.705 97.326 92.849 ;
     RECT  55.332 92.573 55.35 92.939 ;
     RECT  94.215 92.779 95.778 93.011 ;
     RECT  99.615 92.669 101.214 93.011 ;
     RECT  96.732 92.849 97.146 93.055 ;
     RECT  94.215 93.011 95.166 93.209 ;
     RECT  96.48 93.055 97.146 93.209 ;
     RECT  102.024 91.531 102.582 93.209 ;
     RECT  97.056 93.209 97.074 93.245 ;
     RECT  100.944 93.011 101.214 93.245 ;
     RECT  102.024 93.209 102.042 93.317 ;
     RECT  0.036 91.705 8.19 95.369 ;
     RECT  0.036 95.369 8.097 95.639 ;
     RECT  56.196 92.669 56.697 95.639 ;
     RECT  55.368 95.755 55.386 96.179 ;
     RECT  0.036 95.639 5.85 96.251 ;
     RECT  55.08 96.331 55.098 96.449 ;
     RECT  53.244 96.379 53.262 96.457 ;
     RECT  53.244 96.457 53.982 96.493 ;
     RECT  53.244 96.493 54.162 96.727 ;
     RECT  52.992 96.727 54.162 96.871 ;
     RECT  52.416 96.871 54.162 96.907 ;
     RECT  52.272 96.907 54.162 96.989 ;
     RECT  52.992 96.989 54.162 97.025 ;
     RECT  53.208 97.025 54.162 97.061 ;
     RECT  53.208 97.061 53.622 97.259 ;
     RECT  53.532 97.259 53.622 97.295 ;
     RECT  53.568 97.295 53.622 97.529 ;
     RECT  53.604 97.529 53.622 97.601 ;
     RECT  6.624 95.639 8.097 99.689 ;
     RECT  0.036 96.251 3.906 100.973 ;
     RECT  0.108 100.973 3.906 101.309 ;
     RECT  0.216 101.309 3.906 102.605 ;
     RECT  4.824 96.251 5.85 105.359 ;
     RECT  0.396 102.605 3.906 105.367 ;
     RECT  4.824 105.359 5.562 105.367 ;
     RECT  52.236 97.375 52.254 105.629 ;
     RECT  0.396 105.367 5.562 106.061 ;
     RECT  6.696 99.689 8.097 111.029 ;
     RECT  0.828 106.061 5.562 111.037 ;
     RECT  0.54 111.037 5.562 111.677 ;
     RECT  52.308 105.745 52.326 113.459 ;
     RECT  0.828 111.677 5.562 114.269 ;
     RECT  1.476 114.269 5.562 115.133 ;
     RECT  1.476 115.133 3.546 115.997 ;
     RECT  1.476 115.997 3.258 116.861 ;
     RECT  1.548 116.861 3.258 117.293 ;
     RECT  0.108 117.595 0.126 117.725 ;
     RECT  4.824 115.133 5.562 118.157 ;
     RECT  1.908 117.293 3.258 118.589 ;
     RECT  2.088 118.589 3.258 119.021 ;
     RECT  4.824 118.157 4.842 119.837 ;
     RECT  7.092 111.029 8.097 120.317 ;
     RECT  2.088 119.021 2.898 120.749 ;
     RECT  2.232 120.749 2.898 121.181 ;
     RECT  2.415 121.181 2.898 121.613 ;
     RECT  52.092 113.575 52.11 121.666 ;
     RECT  52.092 121.666 52.146 121.667 ;
     RECT  2.415 121.613 2.826 122.011 ;
     RECT  2.304 122.011 2.826 122.141 ;
     RECT  2.415 122.141 2.697 127.187 ;
     RECT  7.815 120.317 8.097 127.187 ;
     RECT  13.215 91.589 13.497 127.187 ;
     RECT  18.615 75.119 18.897 127.187 ;
     RECT  24.015 67.037 24.297 127.187 ;
     RECT  29.415 66.209 29.697 127.187 ;
     RECT  34.815 37.325 35.097 127.187 ;
     RECT  40.215 2.413 40.497 127.187 ;
     RECT  45.615 37.328 45.897 127.187 ;
     RECT  51.015 2.413 51.297 127.187 ;
     RECT  56.415 95.639 56.697 127.187 ;
     RECT  61.815 2.413 62.097 127.187 ;
     RECT  67.215 37.328 67.497 127.187 ;
     RECT  72.615 2.413 72.897 127.187 ;
     RECT  78.015 37.328 78.297 127.187 ;
     RECT  83.415 2.413 83.697 127.187 ;
     RECT  88.815 37.328 89.097 127.187 ;
     RECT  94.215 93.209 94.497 127.187 ;
     RECT  99.615 93.011 99.897 127.187 ;
     RECT  2.415 127.187 2.505 127.457 ;
     RECT  7.815 127.187 7.905 127.457 ;
     RECT  13.215 127.187 13.305 127.457 ;
     RECT  18.615 127.187 18.705 127.457 ;
     RECT  24.015 127.187 24.105 127.457 ;
     RECT  29.415 127.187 29.505 127.457 ;
     RECT  34.815 127.187 34.905 127.457 ;
     RECT  40.215 127.187 40.305 127.457 ;
     RECT  45.615 127.187 45.705 127.457 ;
     RECT  51.015 127.187 51.105 127.457 ;
     RECT  56.415 127.187 56.505 127.457 ;
     RECT  61.815 127.187 61.905 127.457 ;
     RECT  67.215 127.187 67.305 127.457 ;
     RECT  72.615 127.187 72.705 127.457 ;
     RECT  78.015 127.187 78.105 127.457 ;
     RECT  83.415 127.187 83.505 127.457 ;
     RECT  88.815 127.187 88.905 127.457 ;
     RECT  94.215 127.187 94.305 127.457 ;
     RECT  99.615 127.187 99.705 127.457 ;
     RECT  52.128 121.667 52.146 127.661 ;
    LAYER M4 ;
     RECT  0.025 16.944 0.06 16.968 ;
     RECT  0.025 100.944 0.06 100.968 ;
     RECT  0.06 7.536 0.137 122.04 ;
     RECT  0.137 61.536 0.173 122.04 ;
     RECT  0.173 61.536 0.245 99.576 ;
     RECT  0.245 95.664 0.275 98.28 ;
     RECT  0.275 95.664 0.281 96.12 ;
     RECT  0.137 7.536 0.317 16.2 ;
     RECT  0.281 96.096 0.317 96.12 ;
     RECT  0.137 17.472 0.353 60.264 ;
     RECT  0.275 97.392 0.353 98.28 ;
     RECT  0.353 97.392 0.389 97.416 ;
     RECT  0.245 61.536 0.569 94.392 ;
     RECT  0.569 61.968 0.821 86.28 ;
     RECT  0.317 16.176 0.851 16.2 ;
     RECT  0.317 7.536 0.893 15 ;
     RECT  0.893 13.584 0.929 15 ;
     RECT  0.173 100.848 0.929 122.04 ;
     RECT  0.893 7.536 0.965 12.312 ;
     RECT  0.821 61.968 0.965 69.336 ;
     RECT  0.965 61.968 0.995 63.336 ;
     RECT  0.965 64.56 1.001 69.336 ;
     RECT  0.821 70.608 1.037 86.28 ;
     RECT  0.929 101.712 1.037 113.4 ;
     RECT  1.001 64.56 1.073 68.472 ;
     RECT  1.037 101.712 1.073 112.968 ;
     RECT  1.037 70.608 1.109 70.632 ;
     RECT  0.353 17.904 1.181 60.264 ;
     RECT  1.037 71.904 1.181 86.28 ;
     RECT  1.073 67.584 1.325 68.472 ;
     RECT  1.073 64.56 1.361 66.312 ;
     RECT  1.361 64.56 1.397 65.496 ;
     RECT  1.181 17.904 1.433 57.672 ;
     RECT  0.929 114.672 2.293 122.04 ;
     RECT  0.965 7.536 2.408 7.992 ;
     RECT  0.965 9.264 2.408 12.312 ;
     RECT  0.929 14.448 2.408 15 ;
     RECT  1.433 17.904 2.408 23.112 ;
     RECT  1.433 24.384 2.408 57.672 ;
     RECT  1.181 58.656 2.408 59.832 ;
     RECT  0.995 61.968 2.408 63.288 ;
     RECT  1.397 64.992 2.408 65.496 ;
     RECT  1.325 67.584 2.408 68.424 ;
     RECT  1.181 71.904 2.408 74.952 ;
     RECT  1.181 75.936 2.408 86.28 ;
     RECT  0.569 87.888 2.408 89.208 ;
     RECT  0.569 90.48 2.408 94.392 ;
     RECT  0.245 99.552 2.408 99.576 ;
     RECT  1.073 101.712 2.408 103.032 ;
     RECT  1.073 104.736 2.408 112.968 ;
     RECT  2.293 114.672 2.408 122.136 ;
     RECT  2.408 2.148 2.512 127.452 ;
     RECT  2.512 2.418 2.704 127.182 ;
     RECT  2.704 52.992 2.765 54.216 ;
     RECT  2.704 36.912 2.801 36.936 ;
     RECT  2.704 39.072 2.801 39.096 ;
     RECT  2.704 43.152 2.801 43.848 ;
     RECT  2.704 107.328 2.801 107.352 ;
     RECT  2.704 48.144 2.819 51.72 ;
     RECT  2.704 62.736 2.837 65.016 ;
     RECT  2.704 121.584 2.837 122.136 ;
     RECT  2.704 56.88 2.867 61.272 ;
     RECT  2.704 66.72 2.867 66.744 ;
     RECT  2.819 50.304 2.873 51.72 ;
     RECT  2.704 75.936 2.873 83.88 ;
     RECT  2.704 84.864 2.873 88.968 ;
     RECT  2.704 110.784 2.873 110.808 ;
     RECT  2.837 62.736 2.909 64.968 ;
     RECT  2.837 121.584 2.909 121.608 ;
     RECT  2.704 31.728 2.915 35.208 ;
     RECT  2.819 48.144 2.981 49.032 ;
     RECT  2.765 52.992 3.017 53.88 ;
     RECT  2.704 108.624 3.017 108.648 ;
     RECT  2.704 14.448 3.053 15 ;
     RECT  3.053 14.448 3.089 14.472 ;
     RECT  3.017 53.856 3.089 53.88 ;
     RECT  2.704 11.424 3.125 12.312 ;
     RECT  2.704 68.4 3.125 69.048 ;
     RECT  2.704 112.512 3.125 112.968 ;
     RECT  2.704 7.968 3.161 7.992 ;
     RECT  3.125 11.424 3.197 11.448 ;
     RECT  2.704 71.904 3.197 74.712 ;
     RECT  2.704 9.264 3.233 10.152 ;
     RECT  2.704 117.6 3.233 120.312 ;
     RECT  2.704 26.112 3.251 27.912 ;
     RECT  3.233 118.128 3.269 120.312 ;
     RECT  2.867 56.976 3.299 61.272 ;
     RECT  2.915 34.752 3.305 35.208 ;
     RECT  2.704 45.168 3.305 45.576 ;
     RECT  3.197 72.768 3.305 74.712 ;
     RECT  2.915 31.728 3.347 33.576 ;
     RECT  3.305 72.768 3.377 74.616 ;
     RECT  3.305 34.752 3.395 34.776 ;
     RECT  2.909 63.456 3.413 64.968 ;
     RECT  2.873 86.64 3.413 88.968 ;
     RECT  3.413 63.456 3.449 64.44 ;
     RECT  2.704 22.752 3.491 22.776 ;
     RECT  2.704 46.56 3.521 47.112 ;
     RECT  2.704 70.128 3.521 70.152 ;
     RECT  3.377 72.96 3.521 74.616 ;
     RECT  2.704 114.672 3.557 115.992 ;
     RECT  2.873 84.864 3.629 85.512 ;
     RECT  3.125 112.944 3.629 112.968 ;
     RECT  2.704 29.232 3.635 30.456 ;
     RECT  2.801 43.152 3.665 43.272 ;
     RECT  2.981 48.48 3.665 49.032 ;
     RECT  2.704 55.248 3.769 55.512 ;
     RECT  2.873 75.936 3.773 83.832 ;
     RECT  3.347 33.552 3.779 33.576 ;
     RECT  3.413 86.64 3.817 88.104 ;
     RECT  3.521 46.56 3.845 46.872 ;
     RECT  3.125 68.976 3.845 69.048 ;
     RECT  3.773 75.936 3.845 77.112 ;
     RECT  3.773 78.24 3.845 83.832 ;
     RECT  3.233 9.792 3.875 10.152 ;
     RECT  3.665 48.48 3.881 48.504 ;
     RECT  3.521 73.152 3.881 74.616 ;
     RECT  3.845 78.24 3.881 81.432 ;
     RECT  3.635 29.232 3.923 29.256 ;
     RECT  3.875 10.128 3.953 10.152 ;
     RECT  3.299 58.32 3.953 61.272 ;
     RECT  3.881 78.24 3.961 80.424 ;
     RECT  3.953 59.232 4.019 61.272 ;
     RECT  3.769 66.432 4.057 66.456 ;
     RECT  3.845 46.56 4.061 46.824 ;
     RECT  4.057 66.288 4.093 66.456 ;
     RECT  4.019 60.048 4.097 61.272 ;
     RECT  3.449 64.08 4.097 64.44 ;
     RECT  3.769 55.248 4.129 55.656 ;
     RECT  2.704 17.904 4.163 18.456 ;
     RECT  4.093 66.288 4.165 66.552 ;
     RECT  3.769 67.536 4.165 67.56 ;
     RECT  4.085 62.688 4.169 62.712 ;
     RECT  3.557 114.672 4.169 115.128 ;
     RECT  2.873 50.496 4.201 51.72 ;
     RECT  3.845 82.656 4.201 83.832 ;
     RECT  3.629 84.864 4.201 84.888 ;
     RECT  4.163 17.904 4.211 17.928 ;
     RECT  3.299 56.976 4.241 57 ;
     RECT  4.097 64.416 4.249 64.44 ;
     RECT  4.165 66.288 4.277 67.56 ;
     RECT  4.169 114.672 4.277 114.696 ;
     RECT  4.201 50.064 4.309 51.72 ;
     RECT  4.309 50.064 4.349 52.344 ;
     RECT  3.635 30.432 4.355 30.456 ;
     RECT  4.201 82.656 4.357 84.888 ;
     RECT  2.704 90.384 4.453 90.408 ;
     RECT  4.097 60.048 4.457 60.408 ;
     RECT  4.349 50.736 4.493 52.344 ;
     RECT  4.493 52.32 4.529 52.344 ;
     RECT  4.061 46.8 4.595 46.824 ;
     RECT  2.704 91.872 4.595 94.392 ;
     RECT  3.881 73.536 4.597 74.616 ;
     RECT  4.129 54.672 4.601 55.656 ;
     RECT  4.457 60.048 4.601 60.072 ;
     RECT  4.597 73.536 4.601 74.856 ;
     RECT  3.961 78.24 4.637 79.608 ;
     RECT  4.597 70.512 4.669 70.536 ;
     RECT  3.817 86.688 4.673 88.104 ;
     RECT  4.357 83.088 4.709 84.888 ;
     RECT  4.493 50.736 4.781 50.76 ;
     RECT  4.709 83.136 4.781 84.888 ;
     RECT  4.381 42.768 4.813 42.792 ;
     RECT  4.669 70.224 4.813 70.536 ;
     RECT  4.277 67.536 4.817 67.56 ;
     RECT  4.781 83.136 4.817 83.832 ;
     RECT  3.251 26.544 4.835 27.912 ;
     RECT  3.269 119.808 4.853 120.312 ;
     RECT  2.704 103.008 4.889 103.032 ;
     RECT  4.813 42.768 4.921 43.512 ;
     RECT  4.601 74.064 4.921 74.856 ;
     RECT  4.453 90.384 4.957 90.552 ;
     RECT  4.673 86.688 4.993 87.528 ;
     RECT  4.921 42.768 5.005 43.608 ;
     RECT  5.005 42.768 5.02 43.464 ;
     RECT  3.845 68.976 5.029 69 ;
     RECT  5.02 42.768 5.033 43.176 ;
     RECT  3.347 31.728 5.075 32.28 ;
     RECT  4.993 86.064 5.077 87.528 ;
     RECT  3.881 81.408 5.101 81.432 ;
     RECT  4.817 83.808 5.105 83.832 ;
     RECT  2.704 20.064 5.123 20.472 ;
     RECT  5.033 42.768 5.141 43.032 ;
     RECT  5.057 57.6 5.141 57.624 ;
     RECT  4.957 90.384 5.141 90.648 ;
     RECT  4.489 61.392 5.177 61.416 ;
     RECT  4.597 63.216 5.177 63.24 ;
     RECT  4.957 71.856 5.209 71.88 ;
     RECT  4.637 78.24 5.209 78.264 ;
     RECT  4.601 54.672 5.267 54.744 ;
     RECT  5.209 78.096 5.293 78.264 ;
     RECT  3.845 76.128 5.321 77.112 ;
     RECT  4.637 79.584 5.425 79.608 ;
     RECT  5.321 76.224 5.501 77.112 ;
     RECT  4.835 27.072 5.507 27.912 ;
     RECT  5.425 79.584 5.509 79.848 ;
     RECT  4.921 74.064 5.537 75.144 ;
     RECT  5.141 90.384 5.537 90.6 ;
     RECT  5.537 90.528 5.573 90.6 ;
     RECT  3.269 118.128 5.573 118.152 ;
     RECT  4.595 91.872 5.641 93.096 ;
     RECT  5.564 63.12 5.651 63.144 ;
     RECT  5.101 81.312 5.677 81.432 ;
     RECT  5.677 80.928 5.717 81.432 ;
     RECT  3.305 45.168 5.747 45.192 ;
     RECT  5.267 54.672 5.753 54.696 ;
     RECT  5.077 86.688 5.753 87.528 ;
     RECT  5.573 90.528 5.753 90.552 ;
     RECT  5.677 53.568 5.789 53.592 ;
     RECT  5.641 91.632 5.789 93.096 ;
     RECT  5.708 40.704 5.795 40.728 ;
     RECT  5.708 41.76 5.795 41.784 ;
     RECT  5.209 71.856 5.821 72.744 ;
     RECT  5.501 76.272 5.825 77.112 ;
     RECT  5.753 86.688 5.861 86.808 ;
     RECT  5.293 78.24 5.965 78.264 ;
     RECT  5.509 79.584 5.965 79.608 ;
     RECT  5.789 93.072 5.969 93.096 ;
     RECT  4.781 84.864 5.989 84.888 ;
     RECT  5.123 20.448 6.005 20.472 ;
     RECT  5.075 31.728 6.035 31.752 ;
     RECT  5.029 68.88 6.037 69 ;
     RECT  5.821 71.856 6.041 72.984 ;
     RECT  5.605 47.28 6.073 47.304 ;
     RECT  6.073 47.28 6.085 48.264 ;
     RECT  4.813 70.224 6.109 70.632 ;
     RECT  6.037 67.776 6.113 69 ;
     RECT  5.965 78.24 6.113 79.608 ;
     RECT  6.109 70.032 6.145 70.632 ;
     RECT  6.041 71.856 6.145 72.936 ;
     RECT  6.113 78.24 6.149 78.648 ;
     RECT  6.085 46.656 6.177 48.264 ;
     RECT  5.141 43.008 6.277 43.032 ;
     RECT  4.595 94.368 6.329 94.392 ;
     RECT  6.145 70.032 6.397 72.936 ;
     RECT  5.425 39.6 6.437 39.624 ;
     RECT  4.277 66.288 6.473 66.312 ;
     RECT  6.397 69.552 6.473 72.936 ;
     RECT  5.717 80.928 6.473 81.336 ;
     RECT  6.433 45.552 6.505 45.576 ;
     RECT  6.177 46.656 6.505 46.68 ;
     RECT  5.507 27.072 6.509 27.096 ;
     RECT  6.505 45.552 6.545 46.68 ;
     RECT  5.537 74.064 6.577 74.088 ;
     RECT  5.537 75.12 6.577 75.144 ;
     RECT  6.473 69.552 6.581 70.056 ;
     RECT  6.149 78.624 6.581 78.648 ;
     RECT  6.581 70.032 6.653 70.056 ;
     RECT  6.113 67.776 6.689 68.424 ;
     RECT  6.473 71.136 6.761 72.936 ;
     RECT  6.577 74.064 6.761 75.144 ;
     RECT  5.989 84.864 6.761 85.512 ;
     RECT  6.277 43.008 6.805 43.56 ;
     RECT  6.473 81.312 6.829 81.336 ;
     RECT  6.505 83.04 6.829 83.064 ;
     RECT  5.825 76.56 6.833 77.112 ;
     RECT  6.761 84.864 6.833 84.888 ;
     RECT  6.829 81.312 6.853 81.384 ;
     RECT  6.829 82.656 6.853 83.064 ;
     RECT  5.567 64.56 7.153 64.584 ;
     RECT  6.793 65.616 7.153 65.64 ;
     RECT  5.861 86.784 7.189 86.808 ;
     RECT  6.649 54.48 7.388 54.504 ;
     RECT  5.317 56.064 7.388 56.088 ;
     RECT  6.037 59.184 7.429 59.208 ;
     RECT  7.388 54.48 7.477 56.088 ;
     RECT  7.153 64.56 7.621 65.64 ;
     RECT  7.541 66.72 7.621 66.744 ;
     RECT  6.689 67.776 7.621 68.136 ;
     RECT  7.477 53.952 7.657 56.088 ;
     RECT  6.577 61.344 7.657 61.368 ;
     RECT  7.649 63.12 7.665 63.144 ;
     RECT  7.621 64.56 7.665 68.136 ;
     RECT  6.805 42.96 7.808 43.56 ;
     RECT  6.545 45.552 7.808 46.152 ;
     RECT  6.177 48.24 7.808 48.264 ;
     RECT  6.685 50.688 7.808 50.712 ;
     RECT  6.829 52.464 7.808 52.488 ;
     RECT  7.657 53.808 7.808 56.088 ;
     RECT  7.657 57.312 7.808 57.336 ;
     RECT  7.429 59.184 7.808 59.736 ;
     RECT  7.657 61.104 7.808 61.368 ;
     RECT  7.665 63.12 7.808 68.136 ;
     RECT  6.761 71.856 7.808 72.936 ;
     RECT  6.761 74.064 7.808 74.088 ;
     RECT  6.761 75.12 7.808 75.144 ;
     RECT  6.833 76.56 7.808 76.872 ;
     RECT  6.853 81.312 7.808 83.064 ;
     RECT  7.189 86.208 7.808 86.808 ;
     RECT  5.789 91.632 7.808 91.656 ;
     RECT  4.853 120.288 7.808 120.312 ;
     RECT  7.808 2.148 7.912 127.452 ;
     RECT  7.912 2.418 8.104 127.182 ;
     RECT  8.104 72.432 8.237 73.8 ;
     RECT  8.104 81.36 8.273 81.384 ;
     RECT  8.104 90.576 8.291 91.656 ;
     RECT  8.237 73.248 8.309 73.8 ;
     RECT  8.104 71.328 8.345 71.448 ;
     RECT  8.309 73.296 8.381 73.8 ;
     RECT  8.104 64.944 8.435 64.968 ;
     RECT  8.345 71.424 8.489 71.448 ;
     RECT  8.104 61.008 8.597 61.128 ;
     RECT  8.104 66.864 8.597 68.376 ;
     RECT  8.104 52.464 8.669 52.488 ;
     RECT  8.104 63.792 8.771 63.816 ;
     RECT  8.104 56.976 8.777 58.152 ;
     RECT  8.597 66.864 8.819 67.224 ;
     RECT  8.104 62.592 8.849 62.616 ;
     RECT  8.291 91.632 8.849 91.656 ;
     RECT  8.104 87.648 8.993 87.768 ;
     RECT  8.104 59.184 9.101 59.208 ;
     RECT  8.104 74.976 9.109 76.824 ;
     RECT  9.109 74.976 9.155 76.968 ;
     RECT  9.155 74.976 9.389 75.576 ;
     RECT  8.291 90.576 9.389 90.6 ;
     RECT  9.349 62.304 9.443 62.328 ;
     RECT  8.597 68.352 9.637 68.376 ;
     RECT  8.104 70.08 9.637 70.104 ;
     RECT  8.597 61.008 9.713 61.032 ;
     RECT  8.819 66.864 9.731 67.032 ;
     RECT  9.389 74.976 9.74 75 ;
     RECT  9.637 68.352 9.749 70.104 ;
     RECT  9.421 83.184 9.781 83.784 ;
     RECT  9.781 82.656 9.821 83.784 ;
     RECT  9.74 74.928 9.827 75 ;
     RECT  8.993 87.744 9.893 87.768 ;
     RECT  9.821 82.656 9.929 83.208 ;
     RECT  8.104 53.808 9.953 53.832 ;
     RECT  9.397 72.528 9.961 72.552 ;
     RECT  8.381 73.776 9.961 73.8 ;
     RECT  9.929 82.656 9.971 82.68 ;
     RECT  8.104 88.944 9.971 88.968 ;
     RECT  8.777 56.976 10.001 57 ;
     RECT  9.953 53.808 10.019 54.744 ;
     RECT  10.019 54.72 10.037 54.744 ;
     RECT  8.104 85.392 10.109 85.416 ;
     RECT  9.961 72.528 10.213 73.8 ;
     RECT  9.749 70.08 10.259 70.104 ;
     RECT  9.205 81.504 10.289 81.528 ;
     RECT  10.213 71.616 10.547 73.8 ;
     RECT  10.547 71.616 10.605 72.792 ;
     RECT  10.177 79.824 11.036 79.848 ;
     RECT  9.155 76.944 11.045 76.968 ;
     RECT  11.036 79.824 11.077 80.52 ;
     RECT  11.077 79.2 11.123 80.52 ;
     RECT  9.749 68.352 11.297 68.376 ;
     RECT  10.605 72.528 11.297 72.792 ;
     RECT  11.123 79.2 11.621 79.224 ;
     RECT  9.731 67.008 13.208 67.032 ;
     RECT  11.297 72.528 13.208 72.552 ;
     RECT  10.547 73.776 13.208 73.8 ;
     RECT  9.827 74.976 13.208 75 ;
     RECT  13.208 2.148 13.312 127.452 ;
     RECT  13.312 2.418 13.504 127.182 ;
     RECT  14.492 37.488 14.579 37.512 ;
     RECT  13.504 90.624 14.579 90.648 ;
     RECT  15.217 37.392 18.608 37.416 ;
     RECT  13.504 67.008 18.608 67.032 ;
     RECT  13.504 72.528 18.608 72.552 ;
     RECT  13.504 73.776 18.608 73.8 ;
     RECT  13.504 74.976 18.608 75 ;
     RECT  18.608 2.148 18.712 127.452 ;
     RECT  18.712 2.418 18.904 127.182 ;
     RECT  18.904 73.776 19.217 75 ;
     RECT  18.904 72.528 19.397 72.552 ;
     RECT  19.217 74.064 19.397 75 ;
     RECT  19.397 74.688 20.041 75 ;
     RECT  18.904 37.296 24.008 37.32 ;
     RECT  18.904 67.008 24.008 67.032 ;
     RECT  20.041 72.672 24.008 72.696 ;
     RECT  20.041 74.688 24.008 75.144 ;
     RECT  24.008 2.148 24.112 127.452 ;
     RECT  24.112 2.418 24.304 127.182 ;
     RECT  24.304 67.008 26.773 67.032 ;
     RECT  26.773 66.816 26.813 67.032 ;
     RECT  24.304 37.296 29.408 37.32 ;
     RECT  26.813 66.816 29.408 66.84 ;
     RECT  24.304 72.672 29.408 72.696 ;
     RECT  24.304 74.688 29.408 75.144 ;
     RECT  29.408 2.148 29.512 127.452 ;
     RECT  29.512 2.418 29.704 127.182 ;
     RECT  29.704 66.816 31.133 66.84 ;
     RECT  31.165 66.72 31.285 66.744 ;
     RECT  31.285 66 31.331 66.744 ;
     RECT  29.704 37.296 34.808 37.32 ;
     RECT  31.331 66 34.808 66.024 ;
     RECT  29.704 72.672 34.808 72.696 ;
     RECT  29.704 74.688 34.808 75.144 ;
     RECT  34.808 2.148 34.912 127.452 ;
     RECT  34.912 2.418 35.104 127.182 ;
     RECT  35.104 37.296 40.208 37.32 ;
     RECT  35.104 66 40.208 66.024 ;
     RECT  35.104 72.672 40.208 72.696 ;
     RECT  35.104 74.688 40.208 75.144 ;
     RECT  40.208 2.148 40.312 127.452 ;
     RECT  40.312 2.418 40.504 127.182 ;
     RECT  40.504 37.296 45.608 37.32 ;
     RECT  40.504 66 45.608 66.024 ;
     RECT  40.504 72.672 45.608 72.696 ;
     RECT  40.504 74.688 45.608 75.144 ;
     RECT  45.608 2.148 45.712 127.452 ;
     RECT  45.712 2.418 45.904 127.182 ;
     RECT  45.904 37.296 51.008 37.32 ;
     RECT  45.904 66 51.008 66.024 ;
     RECT  45.904 72.672 51.008 72.696 ;
     RECT  45.904 74.688 51.008 75.144 ;
     RECT  51.008 2.148 51.112 127.452 ;
     RECT  51.112 2.418 51.304 127.452 ;
     RECT  51.304 65.904 52.049 66.024 ;
     RECT  52.021 127.632 52.157 127.656 ;
     RECT  51.304 96.912 53.228 96.936 ;
     RECT  53.228 96.384 53.273 96.936 ;
     RECT  53.273 96.384 53.315 96.408 ;
     RECT  52.049 65.904 53.557 65.928 ;
     RECT  53.557 65.904 53.597 66.024 ;
     RECT  53.269 92.544 55.141 92.568 ;
     RECT  55.141 92.448 55.181 92.568 ;
     RECT  51.304 37.296 56.408 37.32 ;
     RECT  53.597 66 56.408 66.024 ;
     RECT  51.304 72.672 56.408 72.696 ;
     RECT  51.304 74.688 56.408 75.144 ;
     RECT  55.181 92.448 56.408 92.472 ;
     RECT  56.408 2.148 56.512 127.452 ;
     RECT  56.512 2.418 56.704 127.182 ;
     RECT  56.704 37.296 61.808 37.32 ;
     RECT  56.704 66 61.808 66.024 ;
     RECT  56.704 72.672 61.808 72.696 ;
     RECT  56.704 74.688 61.808 75.144 ;
     RECT  56.704 92.448 61.808 92.472 ;
     RECT  61.808 2.148 61.912 127.452 ;
     RECT  61.912 2.418 62.104 127.182 ;
     RECT  62.104 37.296 67.208 37.32 ;
     RECT  62.104 66 67.208 66.024 ;
     RECT  62.104 72.672 67.208 72.696 ;
     RECT  62.104 74.688 67.208 75.144 ;
     RECT  62.104 92.448 67.208 92.472 ;
     RECT  67.208 2.148 67.312 127.452 ;
     RECT  67.312 2.418 67.504 127.182 ;
     RECT  67.504 37.296 72.608 37.32 ;
     RECT  67.504 66 72.608 66.024 ;
     RECT  67.504 72.672 72.608 72.696 ;
     RECT  67.504 74.688 72.608 75.144 ;
     RECT  67.504 92.448 72.608 92.472 ;
     RECT  72.608 2.148 72.712 127.452 ;
     RECT  72.712 2.418 72.904 127.182 ;
     RECT  72.904 66 73.649 66.024 ;
     RECT  72.904 37.296 78.008 37.32 ;
     RECT  75.157 65.664 78.008 65.688 ;
     RECT  72.904 72.672 78.008 72.696 ;
     RECT  72.904 74.688 78.008 75.144 ;
     RECT  72.904 92.448 78.008 92.472 ;
     RECT  78.008 2.148 78.112 127.452 ;
     RECT  78.112 2.418 78.304 127.182 ;
     RECT  78.304 37.296 83.408 37.32 ;
     RECT  78.304 65.664 83.408 65.688 ;
     RECT  78.304 72.672 83.408 72.696 ;
     RECT  78.304 74.688 83.408 75.144 ;
     RECT  78.304 92.448 83.408 92.472 ;
     RECT  83.408 2.148 83.512 127.452 ;
     RECT  83.512 2.418 83.704 127.182 ;
     RECT  83.704 92.448 85.525 92.472 ;
     RECT  85.525 92.448 85.597 92.808 ;
     RECT  83.704 37.296 88.808 37.32 ;
     RECT  83.704 65.664 88.808 65.688 ;
     RECT  83.704 72.672 88.808 72.696 ;
     RECT  83.704 74.688 88.808 75.144 ;
     RECT  85.597 92.4 88.808 92.808 ;
     RECT  88.808 2.148 88.912 127.452 ;
     RECT  88.912 2.418 89.104 127.182 ;
     RECT  89.104 37.296 94.208 37.32 ;
     RECT  89.104 65.664 94.208 65.688 ;
     RECT  89.104 72.672 94.208 72.696 ;
     RECT  89.104 74.688 94.208 75.144 ;
     RECT  89.104 92.4 94.208 92.808 ;
     RECT  94.208 2.148 94.312 127.452 ;
     RECT  94.312 2.418 94.504 127.182 ;
     RECT  94.504 52.032 94.673 52.056 ;
     RECT  94.504 62.16 95.219 62.424 ;
     RECT  94.504 59.232 95.548 60.456 ;
     RECT  95.548 59.232 95.701 59.256 ;
     RECT  95.701 58.656 95.747 59.256 ;
     RECT  95.677 57.552 95.761 57.576 ;
     RECT  95.747 58.656 95.861 58.68 ;
     RECT  95.548 60.432 95.861 60.456 ;
     RECT  94.504 72.672 95.893 72.696 ;
     RECT  94.504 68.976 96.037 69 ;
     RECT  96.145 50.688 96.181 50.712 ;
     RECT  96.181 50.688 96.229 50.808 ;
     RECT  94.504 65.664 96.229 65.688 ;
     RECT  94.504 92.4 96.229 92.808 ;
     RECT  96.229 91.728 96.253 92.808 ;
     RECT  96.188 48.048 96.275 48.072 ;
     RECT  96.037 68.64 96.275 69 ;
     RECT  96.253 91.2 96.275 92.808 ;
     RECT  94.504 74.688 96.284 75.144 ;
     RECT  96.275 91.2 96.316 92.472 ;
     RECT  94.504 67.344 96.321 67.368 ;
     RECT  95.713 90.048 96.323 90.072 ;
     RECT  94.504 37.296 96.325 37.32 ;
     RECT  96.284 74.544 96.325 75.144 ;
     RECT  96.316 91.2 96.337 91.224 ;
     RECT  95.893 72.672 96.371 73.512 ;
     RECT  96.325 74.544 96.371 75.624 ;
     RECT  96.371 74.688 96.473 75.624 ;
     RECT  94.504 39.888 96.505 39.912 ;
     RECT  96.505 39.312 96.545 39.912 ;
     RECT  95.605 46.752 96.565 46.776 ;
     RECT  96.565 46.464 96.617 46.776 ;
     RECT  96.617 46.464 96.652 46.488 ;
     RECT  96.275 68.976 96.755 69 ;
     RECT  96.229 65.52 96.757 65.688 ;
     RECT  96.145 85.92 96.793 85.944 ;
     RECT  96.709 69.984 96.797 70.488 ;
     RECT  96.325 37.296 96.851 38.136 ;
     RECT  96.793 85.92 96.877 86.664 ;
     RECT  96.109 41.808 96.901 41.832 ;
     RECT  95.569 87.792 96.941 87.816 ;
     RECT  96.851 37.296 96.977 37.32 ;
     RECT  96.037 55.68 97.004 55.704 ;
     RECT  95.219 62.16 97.007 62.184 ;
     RECT  97.007 61.824 97.013 62.184 ;
     RECT  97.004 55.248 97.045 55.704 ;
     RECT  96.757 64.848 97.045 65.688 ;
     RECT  97.045 55.248 97.091 56.424 ;
     RECT  97.045 64.848 97.091 66.12 ;
     RECT  97.091 56.4 97.117 56.424 ;
     RECT  94.504 80.928 97.141 80.952 ;
     RECT  96.877 85.92 97.141 85.944 ;
     RECT  97.141 80.352 97.187 80.952 ;
     RECT  94.504 53.52 97.225 53.544 ;
     RECT  97.187 80.352 97.228 80.664 ;
     RECT  96.229 50.784 97.229 50.808 ;
     RECT  95.893 45.024 97.265 45.048 ;
     RECT  97.013 61.824 97.297 61.848 ;
     RECT  97.297 61.584 97.331 61.848 ;
     RECT  96.545 39.312 97.333 39.336 ;
     RECT  96.371 72.672 97.333 72.696 ;
     RECT  97.333 45.12 97.369 45.144 ;
     RECT  94.504 77.808 97.369 77.832 ;
     RECT  97.369 77.808 97.409 78.168 ;
     RECT  97.333 38.736 97.417 39.336 ;
     RECT  97.369 45.12 97.42 45.576 ;
     RECT  96.797 69.984 97.429 70.008 ;
     RECT  97.42 45.456 97.453 45.576 ;
     RECT  97.409 78.048 97.453 78.168 ;
     RECT  97.091 66.096 97.475 66.12 ;
     RECT  97.453 78.048 97.475 78.072 ;
     RECT  96.901 41.808 97.477 42.744 ;
     RECT  96.325 43.872 97.477 43.896 ;
     RECT  97.429 69.648 97.481 70.008 ;
     RECT  97.481 69.648 97.516 69.672 ;
     RECT  97.477 41.52 97.523 43.896 ;
     RECT  97.117 56.4 97.523 56.904 ;
     RECT  97.523 41.52 97.589 43.368 ;
     RECT  97.141 85.584 97.589 85.944 ;
     RECT  97.091 64.848 97.697 64.872 ;
     RECT  97.333 71.808 97.729 72.696 ;
     RECT  97.729 71.472 97.913 72.696 ;
     RECT  97.225 53.52 98.005 54.36 ;
     RECT  97.589 42.144 98.021 43.368 ;
     RECT  96.721 79.2 98.021 79.224 ;
     RECT  98.005 52.896 98.051 54.36 ;
     RECT  96.316 92.4 98.053 92.472 ;
     RECT  98.051 52.896 98.093 52.92 ;
     RECT  97.657 50.112 98.099 50.136 ;
     RECT  98.012 90.96 98.099 90.984 ;
     RECT  98.053 92.304 98.099 92.472 ;
     RECT  97.945 51.264 98.345 51.288 ;
     RECT  96.473 74.688 98.345 75.144 ;
     RECT  98.053 66.432 98.377 66.456 ;
     RECT  97.913 72.672 98.413 72.696 ;
     RECT  97.417 39.312 98.449 39.336 ;
     RECT  98.377 66.432 98.461 67.272 ;
     RECT  98.444 40.512 98.531 40.536 ;
     RECT  98.449 39.168 98.553 39.336 ;
     RECT  98.051 54.336 98.561 54.36 ;
     RECT  97.523 56.4 98.561 56.424 ;
     RECT  97.228 80.64 98.581 80.664 ;
     RECT  97.331 61.584 98.627 61.608 ;
     RECT  98.485 62.832 98.627 63 ;
     RECT  98.581 80.64 98.627 81.528 ;
     RECT  98.017 76.944 98.629 76.968 ;
     RECT  98.089 82.56 98.629 82.584 ;
     RECT  97.405 83.808 98.629 83.832 ;
     RECT  98.629 86.544 98.677 86.664 ;
     RECT  98.629 76.32 98.773 76.968 ;
     RECT  98.269 47.232 98.869 47.256 ;
     RECT  98.553 39.168 98.876 39.192 ;
     RECT  98.917 37.008 99.608 37.032 ;
     RECT  98.876 38.64 99.608 39.192 ;
     RECT  98.021 42.144 99.608 42.168 ;
     RECT  98.021 43.344 99.608 43.368 ;
     RECT  97.453 45.456 99.608 45.48 ;
     RECT  98.869 47.232 99.608 47.88 ;
     RECT  98.593 49.008 99.608 49.032 ;
     RECT  97.477 58.08 99.608 58.104 ;
     RECT  98.089 59.616 99.608 59.64 ;
     RECT  98.627 62.976 99.608 63 ;
     RECT  98.461 66.432 99.608 66.456 ;
     RECT  97.913 71.472 99.608 71.496 ;
     RECT  98.413 72.672 99.608 73.512 ;
     RECT  98.345 74.928 99.608 75.144 ;
     RECT  98.773 76.32 99.608 77.544 ;
     RECT  98.627 81.504 99.608 81.528 ;
     RECT  98.629 82.56 99.608 83.832 ;
     RECT  98.089 85.104 99.608 85.128 ;
     RECT  98.677 86.544 99.608 87.192 ;
     RECT  97.549 88.608 99.608 88.632 ;
     RECT  98.099 92.304 99.608 92.328 ;
     RECT  99.608 2.148 99.712 127.452 ;
     RECT  99.712 2.418 99.904 127.182 ;
     RECT  101.977 47.904 102.013 47.928 ;
     RECT  101.977 58.704 102.013 58.728 ;
     RECT  101.977 61.296 102.013 61.32 ;
     RECT  101.977 63.024 102.013 63.048 ;
     RECT  101.977 67.344 102.013 67.368 ;
     RECT  101.653 75.984 102.013 76.008 ;
     RECT  102.013 39.696 102.049 39.72 ;
     RECT  102.049 39.696 102.517 40.584 ;
     RECT  102.013 42.288 102.517 42.312 ;
     RECT  102.013 43.584 102.517 43.608 ;
     RECT  102.013 54.816 102.517 54.84 ;
     RECT  102.013 73.824 102.517 73.848 ;
     RECT  102.301 85.92 102.517 85.944 ;
     RECT  102.517 38.832 102.553 43.608 ;
     RECT  102.517 44.88 102.553 44.904 ;
     RECT  102.013 46.176 102.553 47.928 ;
     RECT  102.517 49.632 102.553 49.656 ;
     RECT  101.977 52.656 102.553 52.68 ;
     RECT  102.517 53.952 102.553 54.84 ;
     RECT  102.013 56.544 102.553 56.568 ;
     RECT  102.013 58.272 102.553 58.728 ;
     RECT  102.013 61.296 102.553 63.048 ;
     RECT  102.013 64.752 102.553 64.776 ;
     RECT  102.013 66.912 102.553 67.368 ;
     RECT  102.517 70.8 102.553 70.824 ;
     RECT  102.517 73.392 102.553 73.848 ;
     RECT  102.013 75.552 102.553 76.008 ;
     RECT  102.013 77.28 102.553 77.304 ;
     RECT  102.013 82.032 102.553 82.056 ;
     RECT  102.517 84.192 102.553 85.944 ;
     RECT  102.517 88.08 102.553 88.104 ;
     RECT  102.013 91.536 102.553 92.424 ;
     RECT  102.553 36.672 103.644 92.856 ;
    LAYER M5 ;
     RECT  2.4 2.137 2.52 2.151 ;
     RECT  7.8 2.137 7.92 2.151 ;
     RECT  13.2 2.137 13.32 2.151 ;
     RECT  18.6 2.137 18.72 2.151 ;
     RECT  24 2.137 24.12 2.151 ;
     RECT  29.4 2.137 29.52 2.151 ;
     RECT  34.8 2.137 34.92 2.151 ;
     RECT  40.2 2.137 40.32 2.151 ;
     RECT  45.6 2.137 45.72 2.151 ;
     RECT  51 2.137 51.12 2.151 ;
     RECT  56.4 2.137 56.52 2.151 ;
     RECT  61.8 2.137 61.92 2.151 ;
     RECT  67.2 2.137 67.32 2.151 ;
     RECT  72.6 2.137 72.72 2.151 ;
     RECT  78 2.137 78.12 2.151 ;
     RECT  83.4 2.137 83.52 2.151 ;
     RECT  88.8 2.137 88.92 2.151 ;
     RECT  94.2 2.137 94.32 2.151 ;
     RECT  99.6 2.137 99.72 2.151 ;
     RECT  3.84 9.781 3.864 17.893 ;
     RECT  3.84 17.893 4.2 20.053 ;
     RECT  2.4 2.151 2.712 22.741 ;
     RECT  3.84 20.053 5.112 22.741 ;
     RECT  0.816 16.165 0.84 23.941 ;
     RECT  0.816 23.941 1.416 25.237 ;
     RECT  2.4 22.741 5.112 25.237 ;
     RECT  0.816 25.237 5.112 27.877 ;
     RECT  0.384 27.877 5.496 28.019 ;
     RECT  0.816 28.019 5.496 31.717 ;
     RECT  99.6 2.151 99.912 36.997 ;
     RECT  96.816 38.101 96.84 38.725 ;
     RECT  98.928 36.997 99.912 39.203 ;
     RECT  96.816 38.725 97.368 39.347 ;
     RECT  98.496 39.301 98.52 40.547 ;
     RECT  97.344 39.347 97.368 41.509 ;
     RECT  0.816 31.717 6.024 42.949 ;
     RECT  7.8 2.151 8.112 42.949 ;
     RECT  0.816 42.949 8.112 43.571 ;
     RECT  97.344 41.509 97.512 43.907 ;
     RECT  97.344 43.907 97.368 45.013 ;
     RECT  7.8 43.571 8.112 45.541 ;
     RECT  96.576 45.013 97.368 45.541 ;
     RECT  96.576 45.541 97.416 46.499 ;
     RECT  0.816 43.571 6.024 46.645 ;
     RECT  99.6 39.203 99.912 47.221 ;
     RECT  0.816 46.645 6.12 47.315 ;
     RECT  96.24 46.741 96.264 48.083 ;
     RECT  98.88 47.221 99.912 49.043 ;
     RECT  97.392 46.499 97.416 50.101 ;
     RECT  96.192 50.677 96.216 50.819 ;
     RECT  97.392 50.101 98.088 51.299 ;
     RECT  97.392 51.299 97.416 52.885 ;
     RECT  0.816 47.315 6.024 53.509 ;
     RECT  97.392 52.885 98.04 53.749 ;
     RECT  97.296 53.749 98.04 54.371 ;
     RECT  9.984 53.797 10.008 54.755 ;
     RECT  7.536 45.541 8.112 55.237 ;
     RECT  97.296 54.371 97.32 55.237 ;
     RECT  7.44 55.237 8.112 56.099 ;
     RECT  97.056 55.237 97.32 56.389 ;
     RECT  97.056 56.389 97.512 56.435 ;
     RECT  97.296 56.435 97.512 58.115 ;
     RECT  7.536 56.099 8.112 59.173 ;
     RECT  94.2 2.151 94.512 59.221 ;
     RECT  95.712 57.541 95.736 59.221 ;
     RECT  94.2 59.221 95.736 59.267 ;
     RECT  7.44 59.173 8.112 59.747 ;
     RECT  94.2 59.267 95.496 60.035 ;
     RECT  97.296 58.115 97.32 61.813 ;
     RECT  97.056 61.813 97.32 61.859 ;
     RECT  94.2 60.035 95.208 62.435 ;
     RECT  7.632 59.747 8.112 62.581 ;
     RECT  9.408 62.293 9.432 62.581 ;
     RECT  98.592 61.573 98.616 62.821 ;
     RECT  98.496 62.821 98.616 62.867 ;
     RECT  98.496 62.867 98.52 63.011 ;
     RECT  7.632 62.581 9.432 63.827 ;
     RECT  7.632 63.827 8.112 64.933 ;
     RECT  97.056 61.859 97.08 65.509 ;
     RECT  7.632 64.933 8.424 65.605 ;
     RECT  51 2.151 51.312 65.989 ;
     RECT  96.24 65.509 97.08 66.085 ;
     RECT  96.24 66.085 97.464 66.131 ;
     RECT  97.44 66.131 97.464 66.421 ;
     RECT  7.584 65.605 8.424 66.755 ;
     RECT  31.296 65.989 31.32 66.755 ;
     RECT  9.408 63.827 9.432 66.853 ;
     RECT  7.632 66.755 8.424 66.899 ;
     RECT  9.408 66.853 9.72 66.997 ;
     RECT  7.8 66.899 8.424 67.189 ;
     RECT  9.408 66.997 9.816 67.189 ;
     RECT  97.44 66.421 98.424 67.283 ;
     RECT  96.24 66.131 96.264 68.675 ;
     RECT  97.44 67.283 97.464 68.965 ;
     RECT  7.8 67.189 9.816 70.069 ;
     RECT  96.72 68.965 97.464 70.499 ;
     RECT  99.6 49.043 99.912 71.461 ;
     RECT  7.8 70.069 10.248 71.605 ;
     RECT  7.8 71.605 10.536 72.563 ;
     RECT  9.792 72.563 10.536 72.995 ;
     RECT  99.024 71.461 99.912 73.523 ;
     RECT  18.6 2.151 18.912 74.053 ;
     RECT  18.6 74.053 19.368 74.723 ;
     RECT  99.6 73.523 99.912 74.917 ;
     RECT  7.8 72.563 8.808 75.011 ;
     RECT  9.792 72.995 9.816 75.541 ;
     RECT  96.336 73.477 96.36 75.635 ;
     RECT  9.12 75.541 9.816 76.979 ;
     RECT  98.784 74.917 99.912 77.555 ;
     RECT  97.44 70.499 97.464 78.083 ;
     RECT  97.392 78.133 97.416 79.189 ;
     RECT  11.088 79.189 11.112 80.531 ;
     RECT  0.144 53.509 6.024 80.627 ;
     RECT  97.152 79.189 97.416 80.963 ;
     RECT  1.968 80.627 6.024 81.349 ;
     RECT  7.8 75.011 8.112 81.349 ;
     RECT  98.592 80.629 98.616 81.539 ;
     RECT  1.968 81.349 8.112 82.355 ;
     RECT  99.6 77.555 99.912 82.549 ;
     RECT  9.792 76.979 9.816 82.645 ;
     RECT  9.792 82.645 9.96 82.691 ;
     RECT  98.928 82.549 99.912 83.173 ;
     RECT  0.144 80.627 0.936 83.267 ;
     RECT  1.968 82.355 6.024 85.523 ;
     RECT  97.392 80.963 97.416 85.573 ;
     RECT  97.152 85.573 97.416 85.619 ;
     RECT  97.152 85.619 97.176 85.909 ;
     RECT  1.968 85.523 5.736 86.099 ;
     RECT  96.816 85.909 97.176 86.675 ;
     RECT  98.64 83.173 99.912 86.675 ;
     RECT  0.144 83.267 0.312 86.773 ;
     RECT  0.144 86.773 0.504 86.915 ;
     RECT  98.688 86.675 99.912 88.643 ;
     RECT  1.968 86.099 4.584 88.691 ;
     RECT  2.4 88.691 4.584 88.979 ;
     RECT  9.936 82.691 9.96 88.979 ;
     RECT  97.152 86.675 97.176 90.037 ;
     RECT  7.8 82.355 8.112 90.565 ;
     RECT  14.544 37.477 14.568 90.659 ;
     RECT  96.288 90.037 97.176 90.949 ;
     RECT  7.8 90.565 8.28 91.667 ;
     RECT  96.288 90.949 98.088 91.717 ;
     RECT  5.712 86.099 5.736 91.907 ;
     RECT  96.24 91.717 98.088 92.435 ;
     RECT  98.064 92.435 98.088 92.483 ;
     RECT  96.24 92.435 96.264 92.819 ;
     RECT  3.984 88.979 4.584 93.539 ;
     RECT  3.984 93.539 4.008 93.923 ;
     RECT  0.144 86.915 0.312 95.267 ;
     RECT  53.28 92.533 53.304 96.419 ;
     RECT  0.192 95.267 0.312 96.563 ;
     RECT  0.24 96.563 0.312 96.995 ;
     RECT  0.288 96.995 0.312 97.859 ;
     RECT  2.4 88.979 2.712 127.449 ;
     RECT  7.8 91.667 8.112 127.449 ;
     RECT  13.2 2.151 13.512 127.449 ;
     RECT  18.6 74.723 18.912 127.449 ;
     RECT  24 2.151 24.312 127.449 ;
     RECT  29.4 2.151 29.712 127.449 ;
     RECT  34.8 2.151 35.112 127.449 ;
     RECT  40.2 2.151 40.512 127.449 ;
     RECT  45.6 2.151 45.912 127.449 ;
     RECT  56.4 2.151 56.712 127.449 ;
     RECT  61.8 2.151 62.112 127.449 ;
     RECT  67.2 2.151 67.512 127.449 ;
     RECT  72.6 2.151 72.912 127.449 ;
     RECT  78 2.151 78.312 127.449 ;
     RECT  83.4 2.151 83.712 127.449 ;
     RECT  88.8 2.151 89.112 127.449 ;
     RECT  94.2 62.435 94.512 127.449 ;
     RECT  99.6 88.643 99.912 127.449 ;
     RECT  2.4 127.449 2.52 127.463 ;
     RECT  7.8 127.449 7.92 127.463 ;
     RECT  13.2 127.449 13.32 127.463 ;
     RECT  18.6 127.449 18.72 127.463 ;
     RECT  24 127.449 24.12 127.463 ;
     RECT  29.4 127.449 29.52 127.463 ;
     RECT  34.8 127.449 34.92 127.463 ;
     RECT  40.2 127.449 40.32 127.463 ;
     RECT  45.6 127.449 45.72 127.463 ;
     RECT  51 65.989 51.624 127.463 ;
     RECT  56.4 127.449 56.52 127.463 ;
     RECT  61.8 127.449 61.92 127.463 ;
     RECT  67.2 127.449 67.32 127.463 ;
     RECT  72.6 127.449 72.72 127.463 ;
     RECT  78 127.449 78.12 127.463 ;
     RECT  83.4 127.449 83.52 127.463 ;
     RECT  88.8 127.449 88.92 127.463 ;
     RECT  94.2 127.449 94.32 127.463 ;
     RECT  99.6 127.449 99.72 127.463 ;
     RECT  51.6 127.463 51.624 127.621 ;
     RECT  51.6 127.621 52.056 129.552 ;
     RECT  2.712 9.781 3.84 22.741 ;
     RECT  1.416 23.941 2.4 25.237 ;
     RECT  13.512 37.477 14.544 90.659 ;
     RECT  98.928 39.203 99.6 39.301 ;
     RECT  97.368 39.301 98.496 40.547 ;
     RECT  98.52 39.301 99.6 40.547 ;
     RECT  97.368 40.547 97.512 41.509 ;
     RECT  6.024 45.541 7.536 46.645 ;
     RECT  96.576 46.499 97.392 46.741 ;
     RECT  6.12 46.645 7.536 47.315 ;
     RECT  96.264 46.741 97.392 48.083 ;
     RECT  97.416 47.221 98.88 49.043 ;
     RECT  6.024 47.315 7.536 55.237 ;
     RECT  97.416 49.043 99.6 50.101 ;
     RECT  98.088 50.101 99.6 51.299 ;
     RECT  96.216 50.677 97.392 50.819 ;
     RECT  6.024 55.237 7.44 56.099 ;
     RECT  6.024 56.099 7.536 59.173 ;
     RECT  94.512 57.541 95.712 59.221 ;
     RECT  6.024 59.173 7.44 59.747 ;
     RECT  97.32 61.573 98.592 61.859 ;
     RECT  98.616 61.573 99.6 62.867 ;
     RECT  97.08 61.859 98.592 62.821 ;
     RECT  8.112 62.293 9.408 62.581 ;
     RECT  97.08 62.821 98.496 63.011 ;
     RECT  98.52 62.867 99.6 63.011 ;
     RECT  8.112 63.827 9.408 64.933 ;
     RECT  8.424 64.933 9.408 67.189 ;
     RECT  96.264 66.131 97.44 68.675 ;
     RECT  98.424 66.421 99.6 67.283 ;
     RECT  96.72 68.675 97.44 68.965 ;
     RECT  8.808 72.563 9.792 75.011 ;
     RECT  96.36 73.477 97.44 75.635 ;
     RECT  99.024 73.523 99.6 74.917 ;
     RECT  97.464 74.917 98.784 77.555 ;
     RECT  8.112 75.011 9.792 75.541 ;
     RECT  8.112 75.541 9.12 76.979 ;
     RECT  9.816 79.189 11.088 80.531 ;
     RECT  0.936 80.627 1.968 83.267 ;
     RECT  97.416 80.629 98.592 81.539 ;
     RECT  98.616 80.629 99.6 81.539 ;
     RECT  97.416 81.539 99.6 82.549 ;
     RECT  97.416 82.549 98.928 83.173 ;
     RECT  97.416 83.173 98.64 85.619 ;
     RECT  97.176 85.619 98.64 86.675 ;
     RECT  4.584 86.099 5.712 91.907 ;
     RECT  97.176 86.675 98.688 88.643 ;
     RECT  0.504 86.773 1.968 86.915 ;
     RECT  2.712 88.979 3.984 93.923 ;
     RECT  98.088 90.949 99.6 92.483 ;
  END
END dsfd_vm_static_read_q4
END LIBRARY
